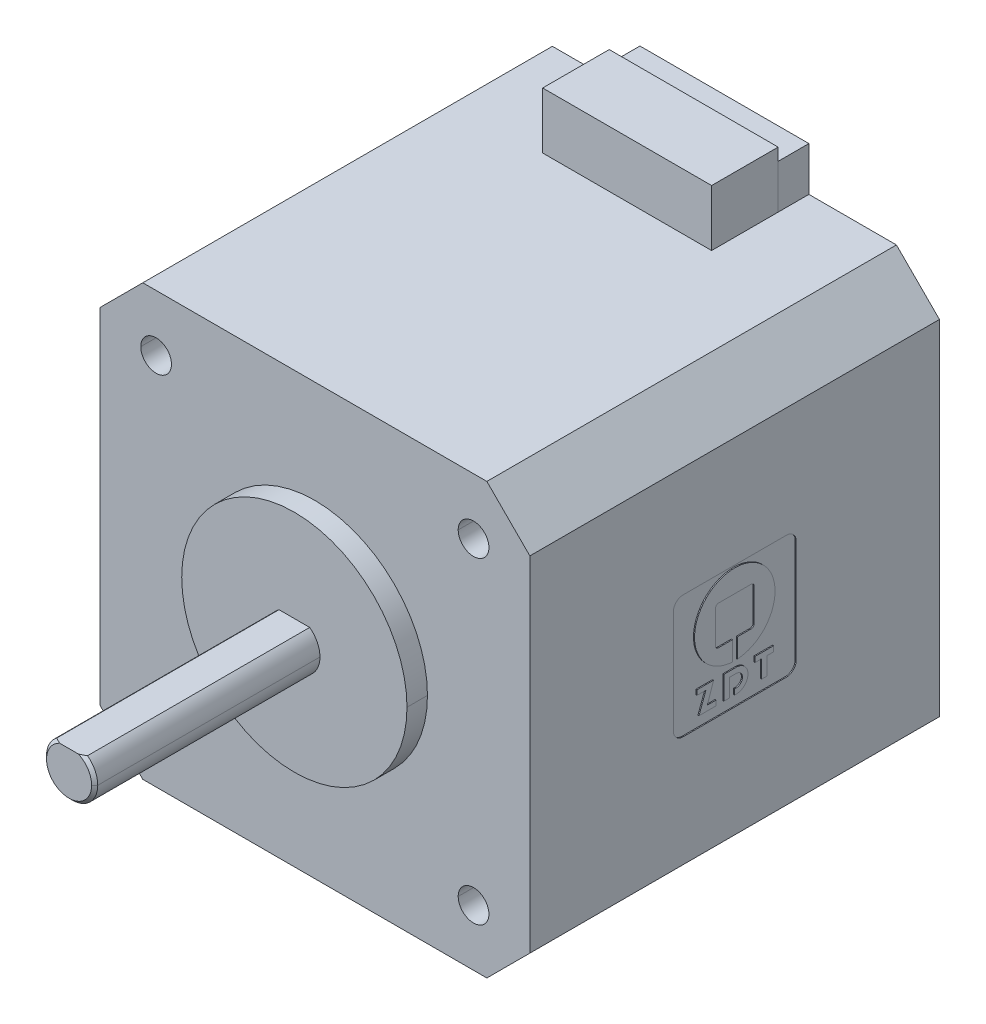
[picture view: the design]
ISO-10303-21;
HEADER;
FILE_DESCRIPTION(('STEP AP214'),'2;1');
FILE_NAME('part.step','',(''),(''),'','','');
FILE_SCHEMA(('AUTOMOTIVE_DESIGN { 1 0 10303 214 1 1 1 1 }'));
ENDSEC;
DATA;
#1=APPLICATION_CONTEXT('core data for automotive mechanical design processes');
#2=APPLICATION_PROTOCOL_DEFINITION('international standard','automotive_design',2000,#1);
#3=PRODUCT_CONTEXT('',#1,'mechanical');
#4=PRODUCT('Part','Part','',(#3));
#5=PRODUCT_RELATED_PRODUCT_CATEGORY('part','',(#4));
#6=PRODUCT_DEFINITION_FORMATION('','',#4);
#7=PRODUCT_DEFINITION_CONTEXT('part definition',#1,'design');
#8=PRODUCT_DEFINITION('design','',#6,#7);
#9=PRODUCT_DEFINITION_SHAPE('','',#8);
#10=(LENGTH_UNIT() NAMED_UNIT(*) SI_UNIT(.MILLI.,.METRE.));
#11=(NAMED_UNIT(*) PLANE_ANGLE_UNIT() SI_UNIT($,.RADIAN.));
#12=(NAMED_UNIT(*) SI_UNIT($,.STERADIAN.) SOLID_ANGLE_UNIT());
#13=UNCERTAINTY_MEASURE_WITH_UNIT(LENGTH_MEASURE(1.E-05),#10,'distance_accuracy_value','');
#14=(GEOMETRIC_REPRESENTATION_CONTEXT(3) GLOBAL_UNCERTAINTY_ASSIGNED_CONTEXT((#13)) GLOBAL_UNIT_ASSIGNED_CONTEXT((#10,
#11,#12)) REPRESENTATION_CONTEXT('',''));
#15=CARTESIAN_POINT('',(0.,0.,0.));
#16=DIRECTION('',(0.,0.,1.));
#17=DIRECTION('',(1.,0.,0.));
#18=AXIS2_PLACEMENT_3D('',#15,#16,#17);
#19=CARTESIAN_POINT('',(0.,21.,0.));
#20=DIRECTION('',(0.,1.,0.));
#21=DIRECTION('',(1.,0.,0.));
#22=AXIS2_PLACEMENT_3D('',#19,#20,#21);
#23=PLANE('',#22);
#24=DIRECTION('',(1.,0.,0.));
#25=VECTOR('',#24,1.);
#26=CARTESIAN_POINT('',(0.,21.,3.));
#27=LINE('',#26,#25);
#28=CARTESIAN_POINT('',(-8.25,21.,3.));
#29=VERTEX_POINT('',#28);
#30=CARTESIAN_POINT('',(8.25,21.,3.));
#31=VERTEX_POINT('',#30);
#32=EDGE_CURVE('P0_E73',#29,#31,#27,.T.);
#33=ORIENTED_EDGE('',*,*,#32,.T.);
#34=DIRECTION('',(0.,0.,1.));
#35=VECTOR('',#34,1.);
#36=CARTESIAN_POINT('',(8.25,21.,0.));
#37=LINE('',#36,#35);
#38=CARTESIAN_POINT('',(8.25,21.,9.5));
#39=VERTEX_POINT('',#38);
#40=EDGE_CURVE('P0_E25',#31,#39,#37,.T.);
#41=ORIENTED_EDGE('',*,*,#40,.T.);
#42=DIRECTION('',(1.,0.,0.));
#43=VECTOR('',#42,1.);
#44=CARTESIAN_POINT('',(0.,21.,9.5));
#45=LINE('',#44,#43);
#46=CARTESIAN_POINT('',(-8.25,21.,9.5));
#47=VERTEX_POINT('',#46);
#48=EDGE_CURVE('P0_E74',#47,#39,#45,.T.);
#49=ORIENTED_EDGE('',*,*,#48,.F.);
#50=DIRECTION('',(0.,0.,1.));
#51=VECTOR('',#50,1.);
#52=CARTESIAN_POINT('',(-8.25,21.,0.));
#53=LINE('',#52,#51);
#54=EDGE_CURVE('P0_E69',#29,#47,#53,.T.);
#55=ORIENTED_EDGE('',*,*,#54,.F.);
#56=EDGE_LOOP('',(#33,#41,#49,#55));
#57=FACE_BOUND('',#56,.T.);
#58=ADVANCED_FACE('P0_F17',(#57),#23,.F.);
#59=CARTESIAN_POINT('',(0.,26.5,0.));
#60=DIRECTION('',(0.,1.,0.));
#61=DIRECTION('',(1.,0.,0.));
#62=AXIS2_PLACEMENT_3D('',#59,#60,#61);
#63=PLANE('',#62);
#64=DIRECTION('',(1.,0.,0.));
#65=VECTOR('',#64,1.);
#66=CARTESIAN_POINT('',(0.,26.5,3.));
#67=LINE('',#66,#65);
#68=CARTESIAN_POINT('',(-8.25,26.5,3.));
#69=VERTEX_POINT('',#68);
#70=CARTESIAN_POINT('',(8.25,26.5,3.));
#71=VERTEX_POINT('',#70);
#72=EDGE_CURVE('P0_E95',#69,#71,#67,.T.);
#73=ORIENTED_EDGE('',*,*,#72,.F.);
#74=DIRECTION('',(0.,0.,1.));
#75=VECTOR('',#74,1.);
#76=CARTESIAN_POINT('',(-8.25,26.5,0.));
#77=LINE('',#76,#75);
#78=CARTESIAN_POINT('',(-8.25,26.5,9.5));
#79=VERTEX_POINT('',#78);
#80=EDGE_CURVE('P0_E87',#69,#79,#77,.T.);
#81=ORIENTED_EDGE('',*,*,#80,.T.);
#82=DIRECTION('',(1.,0.,0.));
#83=VECTOR('',#82,1.);
#84=CARTESIAN_POINT('',(0.,26.5,9.5));
#85=LINE('',#84,#83);
#86=CARTESIAN_POINT('',(8.25,26.5,9.5));
#87=VERTEX_POINT('',#86);
#88=EDGE_CURVE('P0_E111',#79,#87,#85,.T.);
#89=ORIENTED_EDGE('',*,*,#88,.T.);
#90=DIRECTION('',(0.,0.,1.));
#91=VECTOR('',#90,1.);
#92=CARTESIAN_POINT('',(8.25,26.5,0.));
#93=LINE('',#92,#91);
#94=EDGE_CURVE('P0_E11',#71,#87,#93,.T.);
#95=ORIENTED_EDGE('',*,*,#94,.F.);
#96=EDGE_LOOP('',(#73,#81,#89,#95));
#97=FACE_BOUND('',#96,.T.);
#98=ADVANCED_FACE('P0_F165',(#97),#63,.T.);
#99=CARTESIAN_POINT('',(8.25,26.5,0.));
#100=DIRECTION('',(1.,0.,0.));
#101=DIRECTION('',(0.,1.,0.));
#102=AXIS2_PLACEMENT_3D('',#99,#100,#101);
#103=PLANE('',#102);
#104=ORIENTED_EDGE('',*,*,#40,.F.);
#105=DIRECTION('',(0.,-1.,0.));
#106=VECTOR('',#105,1.);
#107=CARTESIAN_POINT('',(8.25,26.5,3.));
#108=LINE('',#107,#106);
#109=EDGE_CURVE('P0_E81',#71,#31,#108,.T.);
#110=ORIENTED_EDGE('',*,*,#109,.F.);
#111=ORIENTED_EDGE('',*,*,#94,.T.);
#112=DIRECTION('',(0.,-1.,0.));
#113=VECTOR('',#112,1.);
#114=CARTESIAN_POINT('',(8.25,26.5,9.5));
#115=LINE('',#114,#113);
#116=EDGE_CURVE('P0_E112',#87,#39,#115,.T.);
#117=ORIENTED_EDGE('',*,*,#116,.T.);
#118=EDGE_LOOP('',(#104,#110,#111,#117));
#119=FACE_BOUND('',#118,.T.);
#120=ADVANCED_FACE('P0_F155',(#119),#103,.T.);
#121=CARTESIAN_POINT('',(0.,26.5,9.5));
#122=DIRECTION('',(0.,0.,-1.));
#123=DIRECTION('',(-1.,0.,0.));
#124=AXIS2_PLACEMENT_3D('',#121,#122,#123);
#125=PLANE('',#124);
#126=ORIENTED_EDGE('',*,*,#48,.T.);
#127=ORIENTED_EDGE('',*,*,#116,.F.);
#128=ORIENTED_EDGE('',*,*,#88,.F.);
#129=DIRECTION('',(0.,-1.,0.));
#130=VECTOR('',#129,1.);
#131=CARTESIAN_POINT('',(-8.25,26.5,9.5));
#132=LINE('',#131,#130);
#133=EDGE_CURVE('P0_E79',#79,#47,#132,.T.);
#134=ORIENTED_EDGE('',*,*,#133,.T.);
#135=EDGE_LOOP('',(#126,#127,#128,#134));
#136=FACE_BOUND('',#135,.T.);
#137=ADVANCED_FACE('P0_F141',(#136),#125,.F.);
#138=CARTESIAN_POINT('',(-8.25,26.5,0.));
#139=DIRECTION('',(1.,0.,0.));
#140=DIRECTION('',(0.,0.,-1.));
#141=AXIS2_PLACEMENT_3D('',#138,#139,#140);
#142=PLANE('',#141);
#143=ORIENTED_EDGE('',*,*,#54,.T.);
#144=ORIENTED_EDGE('',*,*,#133,.F.);
#145=ORIENTED_EDGE('',*,*,#80,.F.);
#146=DIRECTION('',(0.,-1.,0.));
#147=VECTOR('',#146,1.);
#148=CARTESIAN_POINT('',(-8.25,26.5,3.));
#149=LINE('',#148,#147);
#150=EDGE_CURVE('P0_E82',#69,#29,#149,.T.);
#151=ORIENTED_EDGE('',*,*,#150,.T.);
#152=EDGE_LOOP('',(#143,#144,#145,#151));
#153=FACE_BOUND('',#152,.T.);
#154=ADVANCED_FACE('P0_F84',(#153),#142,.F.);
#155=CARTESIAN_POINT('',(0.,26.5,3.));
#156=DIRECTION('',(0.,0.,-1.));
#157=DIRECTION('',(-1.,0.,0.));
#158=AXIS2_PLACEMENT_3D('',#155,#156,#157);
#159=PLANE('',#158);
#160=ORIENTED_EDGE('',*,*,#32,.F.);
#161=ORIENTED_EDGE('',*,*,#150,.F.);
#162=ORIENTED_EDGE('',*,*,#72,.T.);
#163=ORIENTED_EDGE('',*,*,#109,.T.);
#164=EDGE_LOOP('',(#160,#161,#162,#163));
#165=FACE_BOUND('',#164,.T.);
#166=ADVANCED_FACE('P0_F92',(#165),#159,.T.);
#167=CLOSED_SHELL('',(#58,#98,#120,#137,#154,#166));
#168=MANIFOLD_SOLID_BREP('P0_B1',#167);
#169=CARTESIAN_POINT('',(21.,16.8,40.));
#170=DIRECTION('',(-1.,0.,0.));
#171=DIRECTION('',(0.,1.,0.));
#172=AXIS2_PLACEMENT_3D('',#169,#170,#171);
#173=PLANE('',#172);
#174=DIRECTION('',(0.,0.,1.));
#175=VECTOR('',#174,1.);
#176=CARTESIAN_POINT('',(21.,-2.68631850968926,22.0616));
#177=LINE('',#176,#175);
#178=CARTESIAN_POINT('',(21.,-2.68631850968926,22.0616));
#179=VERTEX_POINT('',#178);
#180=CARTESIAN_POINT('',(21.,-2.68631850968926,23.6787));
#181=VERTEX_POINT('',#180);
#182=EDGE_CURVE('P1_E995',#179,#181,#177,.T.);
#183=ORIENTED_EDGE('',*,*,#182,.T.);
#184=DIRECTION('',(0.,-1.,0.));
#185=VECTOR('',#184,1.);
#186=CARTESIAN_POINT('',(21.,-2.68631850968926,23.6787));
#187=LINE('',#186,#185);
#188=CARTESIAN_POINT('',(21.,-3.15601850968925,23.6787));
#189=VERTEX_POINT('',#188);
#190=EDGE_CURVE('P1_E11',#181,#189,#187,.T.);
#191=ORIENTED_EDGE('',*,*,#190,.T.);
#192=DIRECTION('',(0.,0.,-1.));
#193=VECTOR('',#192,1.);
#194=CARTESIAN_POINT('',(21.,-3.15601850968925,23.6787));
#195=LINE('',#194,#193);
#196=CARTESIAN_POINT('',(21.,-3.15601850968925,22.8051));
#197=VERTEX_POINT('',#196);
#198=EDGE_CURVE('P1_E48',#189,#197,#195,.T.);
#199=ORIENTED_EDGE('',*,*,#198,.T.);
#200=DIRECTION('',(0.,-0.936094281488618,0.351749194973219));
#201=VECTOR('',#200,1.);
#202=CARTESIAN_POINT('',(21.,-3.15601850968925,22.8051));
#203=LINE('',#202,#201);
#204=CARTESIAN_POINT('',(21.,-4.97551850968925,23.4888));
#205=VERTEX_POINT('',#204);
#206=EDGE_CURVE('P1_E1090',#197,#205,#203,.T.);
#207=ORIENTED_EDGE('',*,*,#206,.T.);
#208=DIRECTION('',(0.,0.,-1.));
#209=VECTOR('',#208,1.);
#210=CARTESIAN_POINT('',(21.,-4.97551850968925,23.4888));
#211=LINE('',#210,#209);
#212=CARTESIAN_POINT('',(21.,-4.97551850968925,21.8183));
#213=VERTEX_POINT('',#212);
#214=EDGE_CURVE('P1_E1079',#205,#213,#211,.T.);
#215=ORIENTED_EDGE('',*,*,#214,.T.);
#216=DIRECTION('',(0.,1.,0.));
#217=VECTOR('',#216,1.);
#218=CARTESIAN_POINT('',(21.,-4.97551850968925,21.8183));
#219=LINE('',#218,#217);
#220=CARTESIAN_POINT('',(21.,-4.48721850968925,21.8183));
#221=VERTEX_POINT('',#220);
#222=EDGE_CURVE('P1_E1074',#213,#221,#219,.T.);
#223=ORIENTED_EDGE('',*,*,#222,.T.);
#224=DIRECTION('',(0.,0.,1.));
#225=VECTOR('',#224,1.);
#226=CARTESIAN_POINT('',(21.,-4.48721850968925,21.8183));
#227=LINE('',#226,#225);
#228=CARTESIAN_POINT('',(21.,-4.48721850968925,22.6607));
#229=VERTEX_POINT('',#228);
#230=EDGE_CURVE('P1_E1067',#221,#229,#227,.T.);
#231=ORIENTED_EDGE('',*,*,#230,.T.);
#232=DIRECTION('',(0.,0.948882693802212,-0.315628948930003));
#233=VECTOR('',#232,1.);
#234=CARTESIAN_POINT('',(21.,-4.48721850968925,22.6607));
#235=LINE('',#234,#233);
#236=CARTESIAN_POINT('',(21.,-3.15601850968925,22.2179));
#237=VERTEX_POINT('',#236);
#238=EDGE_CURVE('P1_E1065',#229,#237,#235,.T.);
#239=ORIENTED_EDGE('',*,*,#238,.T.);
#240=DIRECTION('',(0.,0.948844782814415,-0.315742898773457));
#241=VECTOR('',#240,1.);
#242=CARTESIAN_POINT('',(21.,-3.15601850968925,22.2179));
#243=LINE('',#242,#241);
#244=EDGE_CURVE('P1_E1053',#237,#179,#243,.T.);
#245=ORIENTED_EDGE('',*,*,#244,.T.);
#246=EDGE_LOOP('',(#183,#191,#199,#207,#215,#223,#231,#239,#245));
#247=FACE_BOUND('',#246,.T.);
#248=ADVANCED_FACE('P1_F18',(#247),#173,.F.);
#249=CARTESIAN_POINT('',(21.,16.8,40.));
#250=DIRECTION('',(-1.,0.,0.));
#251=DIRECTION('',(0.,1.,0.));
#252=AXIS2_PLACEMENT_3D('',#249,#250,#251);
#253=PLANE('',#252);
#254=CARTESIAN_POINT('',(21.,-3.21791850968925,19.8494));
#255=CARTESIAN_POINT('',(21.,-3.21791850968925,19.5131));
#256=CARTESIAN_POINT('',(21.,-3.49311850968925,19.2382));
#257=CARTESIAN_POINT('',(21.,-3.82921850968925,19.2382));
#258=(BOUNDED_CURVE() B_SPLINE_CURVE(3,(#254,#255,#256,#257),.UNSPECIFIED.,.F.,
.F.) B_SPLINE_CURVE_WITH_KNOTS((4,4),(0.4375,0.5),
.UNSPECIFIED.) CURVE() GEOMETRIC_REPRESENTATION_ITEM() RATIONAL_B_SPLINE_CURVE((1.,1.,1.,1.)) REPRESENTATION_ITEM(''));
#259=CARTESIAN_POINT('',(21.,-3.21791850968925,19.8494));
#260=VERTEX_POINT('',#259);
#261=CARTESIAN_POINT('',(21.,-3.82921850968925,19.2382));
#262=VERTEX_POINT('',#261);
#263=EDGE_CURVE('P1_E768',#260,#262,#258,.T.);
#264=ORIENTED_EDGE('',*,*,#263,.T.);
#265=CARTESIAN_POINT('',(21.,-3.82921850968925,19.2382));
#266=CARTESIAN_POINT('',(21.,-4.16521850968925,19.2382));
#267=CARTESIAN_POINT('',(21.,-4.44041850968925,19.5131));
#268=CARTESIAN_POINT('',(21.,-4.44041850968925,19.8494));
#269=(BOUNDED_CURVE() B_SPLINE_CURVE(3,(#265,#266,#267,#268),.UNSPECIFIED.,.F.,
.F.) B_SPLINE_CURVE_WITH_KNOTS((4,4),(0.5,0.5625),
.UNSPECIFIED.) CURVE() GEOMETRIC_REPRESENTATION_ITEM() RATIONAL_B_SPLINE_CURVE((1.,1.,1.,1.)) REPRESENTATION_ITEM(''));
#270=CARTESIAN_POINT('',(21.,-4.44041850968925,19.8494));
#271=VERTEX_POINT('',#270);
#272=EDGE_CURVE('P1_E862',#262,#271,#269,.T.);
#273=ORIENTED_EDGE('',*,*,#272,.T.);
#274=DIRECTION('',(0.,0.,1.));
#275=VECTOR('',#274,1.);
#276=CARTESIAN_POINT('',(21.,-4.44041850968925,19.8494));
#277=LINE('',#276,#275);
#278=CARTESIAN_POINT('',(21.,-4.44041850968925,20.));
#279=VERTEX_POINT('',#278);
#280=EDGE_CURVE('P1_E853',#271,#279,#277,.T.);
#281=ORIENTED_EDGE('',*,*,#280,.T.);
#282=DIRECTION('',(0.,-1.,0.));
#283=VECTOR('',#282,1.);
#284=CARTESIAN_POINT('',(21.,-4.44041850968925,20.));
#285=LINE('',#284,#283);
#286=CARTESIAN_POINT('',(21.,-4.96361850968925,20.));
#287=VERTEX_POINT('',#286);
#288=EDGE_CURVE('P1_E813',#279,#287,#285,.T.);
#289=ORIENTED_EDGE('',*,*,#288,.T.);
#290=DIRECTION('',(0.,0.,-1.));
#291=VECTOR('',#290,1.);
#292=CARTESIAN_POINT('',(21.,-4.96361850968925,20.));
#293=LINE('',#292,#291);
#294=CARTESIAN_POINT('',(21.,-4.96361850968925,19.8307));
#295=VERTEX_POINT('',#294);
#296=EDGE_CURVE('P1_E812',#287,#295,#293,.T.);
#297=ORIENTED_EDGE('',*,*,#296,.T.);
#298=CARTESIAN_POINT('',(21.,-4.96361850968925,19.8307));
#299=CARTESIAN_POINT('',(21.,-4.96361850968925,19.2067));
#300=CARTESIAN_POINT('',(21.,-4.45321850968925,18.6962));
#301=CARTESIAN_POINT('',(21.,-3.82921850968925,18.6962));
#302=(BOUNDED_CURVE() B_SPLINE_CURVE(3,(#298,#299,#300,#301),.UNSPECIFIED.,.F.,
.F.) B_SPLINE_CURVE_WITH_KNOTS((4,4),(0.75,0.8125),
.UNSPECIFIED.) CURVE() GEOMETRIC_REPRESENTATION_ITEM() RATIONAL_B_SPLINE_CURVE((1.,1.,1.,1.)) REPRESENTATION_ITEM(''));
#303=CARTESIAN_POINT('',(21.,-3.82921850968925,18.6962));
#304=VERTEX_POINT('',#303);
#305=EDGE_CURVE('P1_E828',#295,#304,#302,.T.);
#306=ORIENTED_EDGE('',*,*,#305,.T.);
#307=CARTESIAN_POINT('',(21.,-3.82921850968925,18.6962));
#308=CARTESIAN_POINT('',(21.,-3.20521850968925,18.6962));
#309=CARTESIAN_POINT('',(21.,-2.69471850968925,19.2067));
#310=CARTESIAN_POINT('',(21.,-2.69471850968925,19.8307));
#311=(BOUNDED_CURVE() B_SPLINE_CURVE(3,(#307,#308,#309,#310),.UNSPECIFIED.,.F.,
.F.) B_SPLINE_CURVE_WITH_KNOTS((4,4),(0.875,0.9375),
.UNSPECIFIED.) CURVE() GEOMETRIC_REPRESENTATION_ITEM() RATIONAL_B_SPLINE_CURVE((1.,1.,1.,1.)) REPRESENTATION_ITEM(''));
#312=CARTESIAN_POINT('',(21.,-2.69471850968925,19.8307));
#313=VERTEX_POINT('',#312);
#314=EDGE_CURVE('P1_E818',#304,#313,#311,.T.);
#315=ORIENTED_EDGE('',*,*,#314,.T.);
#316=DIRECTION('',(0.,0.,1.));
#317=VECTOR('',#316,1.);
#318=CARTESIAN_POINT('',(21.,-2.69471850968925,19.8307));
#319=LINE('',#318,#317);
#320=CARTESIAN_POINT('',(21.,-2.69471850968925,21.0456));
#321=VERTEX_POINT('',#320);
#322=EDGE_CURVE('P1_E804',#313,#321,#319,.T.);
#323=ORIENTED_EDGE('',*,*,#322,.T.);
#324=DIRECTION('',(0.,-1.,0.));
#325=VECTOR('',#324,1.);
#326=CARTESIAN_POINT('',(21.,-2.69471850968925,21.0456));
#327=LINE('',#326,#325);
#328=CARTESIAN_POINT('',(21.,-4.96361850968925,21.0456));
#329=VERTEX_POINT('',#328);
#330=EDGE_CURVE('P1_E799',#321,#329,#327,.T.);
#331=ORIENTED_EDGE('',*,*,#330,.T.);
#332=DIRECTION('',(0.,0.,-1.));
#333=VECTOR('',#332,1.);
#334=CARTESIAN_POINT('',(21.,-4.96361850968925,21.0456));
#335=LINE('',#334,#333);
#336=CARTESIAN_POINT('',(21.,-4.96361850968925,20.5036));
#337=VERTEX_POINT('',#336);
#338=EDGE_CURVE('P1_E791',#329,#337,#335,.T.);
#339=ORIENTED_EDGE('',*,*,#338,.T.);
#340=DIRECTION('',(0.,1.,0.));
#341=VECTOR('',#340,1.);
#342=CARTESIAN_POINT('',(21.,-4.05351850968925,20.5036));
#343=LINE('',#342,#341);
#344=CARTESIAN_POINT('',(21.,-3.21791850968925,20.5036));
#345=VERTEX_POINT('',#344);
#346=EDGE_CURVE('P1_E694',#337,#345,#343,.T.);
#347=ORIENTED_EDGE('',*,*,#346,.T.);
#348=DIRECTION('',(0.,0.,-1.));
#349=VECTOR('',#348,1.);
#350=CARTESIAN_POINT('',(21.,-3.21791850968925,20.5036));
#351=LINE('',#350,#349);
#352=EDGE_CURVE('P1_E693',#345,#260,#351,.T.);
#353=ORIENTED_EDGE('',*,*,#352,.T.);
#354=EDGE_LOOP('',(#264,#273,#281,#289,#297,#306,#315,#323,#331,#339,#347,#353));
#355=FACE_BOUND('',#354,.T.);
#356=ADVANCED_FACE('P1_F1170',(#355),#253,.F.);
#357=CARTESIAN_POINT('',(21.,16.8,40.));
#358=DIRECTION('',(-1.,0.,0.));
#359=DIRECTION('',(0.,1.,0.));
#360=AXIS2_PLACEMENT_3D('',#357,#358,#359);
#361=PLANE('',#360);
#362=CARTESIAN_POINT('',(21.,-2.06441850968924,19.7418));
#363=CARTESIAN_POINT('',(21.,-1.93761850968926,17.6866));
#364=CARTESIAN_POINT('',(21.,-0.23111850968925,16.0587));
#365=CARTESIAN_POINT('',(21.,1.85608149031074,16.0587));
#366=(BOUNDED_CURVE() B_SPLINE_CURVE(3,(#362,#363,#364,#365),.UNSPECIFIED.,.F.,
.F.) B_SPLINE_CURVE_WITH_KNOTS((4,4),(0.125,0.1875),
.UNSPECIFIED.) CURVE() GEOMETRIC_REPRESENTATION_ITEM() RATIONAL_B_SPLINE_CURVE((1.,1.,1.,1.)) REPRESENTATION_ITEM(''));
#367=CARTESIAN_POINT('',(21.,-2.06441850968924,19.7418));
#368=VERTEX_POINT('',#367);
#369=CARTESIAN_POINT('',(21.,1.85608149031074,16.0587));
#370=VERTEX_POINT('',#369);
#371=EDGE_CURVE('P1_E869',#368,#370,#366,.T.);
#372=ORIENTED_EDGE('',*,*,#371,.T.);
#373=CARTESIAN_POINT('',(21.,1.85608149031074,16.0587));
#374=CARTESIAN_POINT('',(21.,4.02578149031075,16.0587));
#375=CARTESIAN_POINT('',(21.,5.78458149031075,17.8178));
#376=CARTESIAN_POINT('',(21.,5.78458149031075,19.9874));
#377=(BOUNDED_CURVE() B_SPLINE_CURVE(3,(#373,#374,#375,#376),.UNSPECIFIED.,.F.,
.F.) B_SPLINE_CURVE_WITH_KNOTS((4,4),(0.1875,0.25),
.UNSPECIFIED.) CURVE() GEOMETRIC_REPRESENTATION_ITEM() RATIONAL_B_SPLINE_CURVE((1.,1.,1.,1.)) REPRESENTATION_ITEM(''));
#378=CARTESIAN_POINT('',(21.,5.78458149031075,19.9874));
#379=VERTEX_POINT('',#378);
#380=EDGE_CURVE('P1_E861',#370,#379,#377,.T.);
#381=ORIENTED_EDGE('',*,*,#380,.T.);
#382=CARTESIAN_POINT('',(21.,5.78458149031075,19.9874));
#383=CARTESIAN_POINT('',(21.,5.78458149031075,22.1568));
#384=CARTESIAN_POINT('',(21.,4.02578149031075,23.9159));
#385=CARTESIAN_POINT('',(21.,1.85608149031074,23.9159));
#386=(BOUNDED_CURVE() B_SPLINE_CURVE(3,(#382,#383,#384,#385),.UNSPECIFIED.,.F.,
.F.) B_SPLINE_CURVE_WITH_KNOTS((4,4),(0.25,0.3125),
.UNSPECIFIED.) CURVE() GEOMETRIC_REPRESENTATION_ITEM() RATIONAL_B_SPLINE_CURVE((1.,1.,1.,1.)) REPRESENTATION_ITEM(''));
#387=CARTESIAN_POINT('',(21.,1.85608149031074,23.9159));
#388=VERTEX_POINT('',#387);
#389=EDGE_CURVE('P1_E864',#379,#388,#386,.T.);
#390=ORIENTED_EDGE('',*,*,#389,.T.);
#391=CARTESIAN_POINT('',(21.,1.85608149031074,23.9159));
#392=CARTESIAN_POINT('',(21.,-0.23111850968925,23.9159));
#393=CARTESIAN_POINT('',(21.,-1.93761850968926,22.288));
#394=CARTESIAN_POINT('',(21.,-2.06441850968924,20.2328));
#395=(BOUNDED_CURVE() B_SPLINE_CURVE(3,(#391,#392,#393,#394),.UNSPECIFIED.,.F.,
.F.) B_SPLINE_CURVE_WITH_KNOTS((4,4),(0.3125,0.375),
.UNSPECIFIED.) CURVE() GEOMETRIC_REPRESENTATION_ITEM() RATIONAL_B_SPLINE_CURVE((1.,1.,1.,1.)) REPRESENTATION_ITEM(''));
#396=CARTESIAN_POINT('',(21.,-2.06441850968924,20.2328));
#397=VERTEX_POINT('',#396);
#398=EDGE_CURVE('P1_E990',#388,#397,#395,.T.);
#399=ORIENTED_EDGE('',*,*,#398,.T.);
#400=DIRECTION('',(0.,1.,0.));
#401=VECTOR('',#400,1.);
#402=CARTESIAN_POINT('',(21.,-2.06441850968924,20.2328));
#403=LINE('',#402,#401);
#404=CARTESIAN_POINT('',(21.,-0.175218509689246,20.2328));
#405=VERTEX_POINT('',#404);
#406=EDGE_CURVE('P1_E985',#397,#405,#403,.T.);
#407=ORIENTED_EDGE('',*,*,#406,.T.);
#408=DIRECTION('',(0.,0.,1.));
#409=VECTOR('',#408,1.);
#410=CARTESIAN_POINT('',(21.,-0.175218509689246,20.2328));
#411=LINE('',#410,#409);
#412=CARTESIAN_POINT('',(21.,-0.175218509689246,21.5695));
#413=VERTEX_POINT('',#412);
#414=EDGE_CURVE('P1_E972',#405,#413,#411,.T.);
#415=ORIENTED_EDGE('',*,*,#414,.T.);
#416=CARTESIAN_POINT('',(21.,-0.175218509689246,21.5695));
#417=CARTESIAN_POINT('',(21.,-0.175218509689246,21.7375));
#418=CARTESIAN_POINT('',(21.,-0.0379185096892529,21.8747));
#419=CARTESIAN_POINT('',(21.,0.129781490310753,21.8747));
#420=(BOUNDED_CURVE() B_SPLINE_CURVE(3,(#416,#417,#418,#419),.UNSPECIFIED.,.F.,
.F.) B_SPLINE_CURVE_WITH_KNOTS((4,4),(0.5,0.5625),
.UNSPECIFIED.) CURVE() GEOMETRIC_REPRESENTATION_ITEM() RATIONAL_B_SPLINE_CURVE((1.,1.,1.,1.)) REPRESENTATION_ITEM(''));
#421=CARTESIAN_POINT('',(21.,0.129781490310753,21.8747));
#422=VERTEX_POINT('',#421);
#423=EDGE_CURVE('P1_E964',#413,#422,#420,.T.);
#424=ORIENTED_EDGE('',*,*,#423,.T.);
#425=DIRECTION('',(0.,1.,0.));
#426=VECTOR('',#425,1.);
#427=CARTESIAN_POINT('',(21.,0.129781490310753,21.8747));
#428=LINE('',#427,#426);
#429=CARTESIAN_POINT('',(21.,3.29448149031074,21.8747));
#430=VERTEX_POINT('',#429);
#431=EDGE_CURVE('P1_E910',#422,#430,#428,.T.);
#432=ORIENTED_EDGE('',*,*,#431,.T.);
#433=CARTESIAN_POINT('',(21.,3.29448149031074,21.8747));
#434=CARTESIAN_POINT('',(21.,3.46218149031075,21.8747));
#435=CARTESIAN_POINT('',(21.,3.59968149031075,21.7375));
#436=CARTESIAN_POINT('',(21.,3.59968149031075,21.5695));
#437=(BOUNDED_CURVE() B_SPLINE_CURVE(3,(#433,#434,#435,#436),.UNSPECIFIED.,.F.,
.F.) B_SPLINE_CURVE_WITH_KNOTS((4,4),(0.625,0.6875),
.UNSPECIFIED.) CURVE() GEOMETRIC_REPRESENTATION_ITEM() RATIONAL_B_SPLINE_CURVE((1.,1.,1.,1.)) REPRESENTATION_ITEM(''));
#438=CARTESIAN_POINT('',(21.,3.59968149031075,21.5695));
#439=VERTEX_POINT('',#438);
#440=EDGE_CURVE('P1_E947',#430,#439,#437,.T.);
#441=ORIENTED_EDGE('',*,*,#440,.T.);
#442=DIRECTION('',(0.,0.,-1.));
#443=VECTOR('',#442,1.);
#444=CARTESIAN_POINT('',(21.,3.59968149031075,21.5695));
#445=LINE('',#444,#443);
#446=CARTESIAN_POINT('',(21.,3.59968149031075,18.4051));
#447=VERTEX_POINT('',#446);
#448=EDGE_CURVE('P1_E940',#439,#447,#445,.T.);
#449=ORIENTED_EDGE('',*,*,#448,.T.);
#450=CARTESIAN_POINT('',(21.,3.59968149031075,18.4051));
#451=CARTESIAN_POINT('',(21.,3.59968149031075,18.2371));
#452=CARTESIAN_POINT('',(21.,3.46218149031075,18.0999));
#453=CARTESIAN_POINT('',(21.,3.29448149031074,18.0999));
#454=(BOUNDED_CURVE() B_SPLINE_CURVE(3,(#450,#451,#452,#453),.UNSPECIFIED.,.F.,
.F.) B_SPLINE_CURVE_WITH_KNOTS((4,4),(0.75,0.8125),
.UNSPECIFIED.) CURVE() GEOMETRIC_REPRESENTATION_ITEM() RATIONAL_B_SPLINE_CURVE((1.,1.,1.,1.)) REPRESENTATION_ITEM(''));
#455=CARTESIAN_POINT('',(21.,3.29448149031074,18.0999));
#456=VERTEX_POINT('',#455);
#457=EDGE_CURVE('P1_E924',#447,#456,#454,.T.);
#458=ORIENTED_EDGE('',*,*,#457,.T.);
#459=DIRECTION('',(0.,-1.,0.));
#460=VECTOR('',#459,1.);
#461=CARTESIAN_POINT('',(21.,3.29448149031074,18.0999));
#462=LINE('',#461,#460);
#463=CARTESIAN_POINT('',(21.,0.129781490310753,18.0999));
#464=VERTEX_POINT('',#463);
#465=EDGE_CURVE('P1_E916',#456,#464,#462,.T.);
#466=ORIENTED_EDGE('',*,*,#465,.T.);
#467=CARTESIAN_POINT('',(21.,0.129781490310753,18.0999));
#468=CARTESIAN_POINT('',(21.,-0.0379185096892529,18.0999));
#469=CARTESIAN_POINT('',(21.,-0.175218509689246,18.2371));
#470=CARTESIAN_POINT('',(21.,-0.175218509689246,18.4051));
#471=(BOUNDED_CURVE() B_SPLINE_CURVE(3,(#467,#468,#469,#470),.UNSPECIFIED.,.F.,
.F.) B_SPLINE_CURVE_WITH_KNOTS((4,4),(0.875,0.9375),
.UNSPECIFIED.) CURVE() GEOMETRIC_REPRESENTATION_ITEM() RATIONAL_B_SPLINE_CURVE((1.,1.,1.,1.)) REPRESENTATION_ITEM(''));
#472=CARTESIAN_POINT('',(21.,-0.175218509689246,18.4051));
#473=VERTEX_POINT('',#472);
#474=EDGE_CURVE('P1_E901',#464,#473,#471,.T.);
#475=ORIENTED_EDGE('',*,*,#474,.T.);
#476=DIRECTION('',(0.,0.,1.));
#477=VECTOR('',#476,1.);
#478=CARTESIAN_POINT('',(21.,-0.175218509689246,18.4051));
#479=LINE('',#478,#477);
#480=CARTESIAN_POINT('',(21.,-0.175218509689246,19.7418));
#481=VERTEX_POINT('',#480);
#482=EDGE_CURVE('P1_E896',#473,#481,#479,.T.);
#483=ORIENTED_EDGE('',*,*,#482,.T.);
#484=DIRECTION('',(0.,-1.,0.));
#485=VECTOR('',#484,1.);
#486=CARTESIAN_POINT('',(21.,-0.175218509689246,19.7418));
#487=LINE('',#486,#485);
#488=EDGE_CURVE('P1_E890',#481,#368,#487,.T.);
#489=ORIENTED_EDGE('',*,*,#488,.T.);
#490=EDGE_LOOP('',(#372,#381,#390,#399,#407,#415,#424,#432,#441,#449,#458,#466,#475,#483,#489));
#491=FACE_BOUND('',#490,.T.);
#492=ADVANCED_FACE('P1_F1163',(#491),#361,.F.);
#493=CARTESIAN_POINT('',(21.,16.8,40.));
#494=DIRECTION('',(-1.,0.,0.));
#495=DIRECTION('',(0.,1.,0.));
#496=AXIS2_PLACEMENT_3D('',#493,#494,#495);
#497=PLANE('',#496);
#498=DIRECTION('',(0.,0.,1.));
#499=VECTOR('',#498,1.);
#500=CARTESIAN_POINT('',(21.,-2.69881850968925,16.1943));
#501=LINE('',#500,#499);
#502=CARTESIAN_POINT('',(21.,-2.69881850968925,16.1943));
#503=VERTEX_POINT('',#502);
#504=CARTESIAN_POINT('',(21.,-2.69881850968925,18.0146));
#505=VERTEX_POINT('',#504);
#506=EDGE_CURVE('P1_E1001',#503,#505,#501,.T.);
#507=ORIENTED_EDGE('',*,*,#506,.T.);
#508=DIRECTION('',(0.,-1.,0.));
#509=VECTOR('',#508,1.);
#510=CARTESIAN_POINT('',(21.,-2.69881850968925,18.0146));
#511=LINE('',#510,#509);
#512=CARTESIAN_POINT('',(21.,-3.21521850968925,18.0146));
#513=VERTEX_POINT('',#512);
#514=EDGE_CURVE('P1_E996',#505,#513,#511,.T.);
#515=ORIENTED_EDGE('',*,*,#514,.T.);
#516=DIRECTION('',(0.,0.,-1.));
#517=VECTOR('',#516,1.);
#518=CARTESIAN_POINT('',(21.,-3.21521850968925,18.0146));
#519=LINE('',#518,#517);
#520=CARTESIAN_POINT('',(21.,-3.21521850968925,17.3627));
#521=VERTEX_POINT('',#520);
#522=EDGE_CURVE('P1_E939',#513,#521,#519,.T.);
#523=ORIENTED_EDGE('',*,*,#522,.T.);
#524=DIRECTION('',(0.,-1.,0.));
#525=VECTOR('',#524,1.);
#526=CARTESIAN_POINT('',(21.,-3.21521850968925,17.3627));
#527=LINE('',#526,#525);
#528=CARTESIAN_POINT('',(21.,-4.94241850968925,17.3627));
#529=VERTEX_POINT('',#528);
#530=EDGE_CURVE('P1_E1028',#521,#529,#527,.T.);
#531=ORIENTED_EDGE('',*,*,#530,.T.);
#532=DIRECTION('',(0.,0.,-1.));
#533=VECTOR('',#532,1.);
#534=CARTESIAN_POINT('',(21.,-4.94241850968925,17.3627));
#535=LINE('',#534,#533);
#536=CARTESIAN_POINT('',(21.,-4.94241850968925,16.8462));
#537=VERTEX_POINT('',#536);
#538=EDGE_CURVE('P1_E1033',#529,#537,#535,.T.);
#539=ORIENTED_EDGE('',*,*,#538,.T.);
#540=DIRECTION('',(0.,1.,0.));
#541=VECTOR('',#540,1.);
#542=CARTESIAN_POINT('',(21.,-4.94241850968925,16.8462));
#543=LINE('',#542,#541);
#544=CARTESIAN_POINT('',(21.,-3.21521850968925,16.8462));
#545=VERTEX_POINT('',#544);
#546=EDGE_CURVE('P1_E1022',#537,#545,#543,.T.);
#547=ORIENTED_EDGE('',*,*,#546,.T.);
#548=DIRECTION('',(0.,0.,-1.));
#549=VECTOR('',#548,1.);
#550=CARTESIAN_POINT('',(21.,-3.21521850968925,16.8462));
#551=LINE('',#550,#549);
#552=CARTESIAN_POINT('',(21.,-3.21521850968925,16.1943));
#553=VERTEX_POINT('',#552);
#554=EDGE_CURVE('P1_E841',#545,#553,#551,.T.);
#555=ORIENTED_EDGE('',*,*,#554,.T.);
#556=DIRECTION('',(0.,1.,0.));
#557=VECTOR('',#556,1.);
#558=CARTESIAN_POINT('',(21.,-3.21521850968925,16.1943));
#559=LINE('',#558,#557);
#560=EDGE_CURVE('P1_E1012',#553,#503,#559,.T.);
#561=ORIENTED_EDGE('',*,*,#560,.T.);
#562=EDGE_LOOP('',(#507,#515,#523,#531,#539,#547,#555,#561));
#563=FACE_BOUND('',#562,.T.);
#564=ADVANCED_FACE('P1_F20',(#563),#497,.F.);
#565=CARTESIAN_POINT('',(20.9,-2.68631850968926,23.6787));
#566=DIRECTION('',(0.,0.,1.));
#567=DIRECTION('',(1.,0.,0.));
#568=AXIS2_PLACEMENT_3D('',#565,#566,#567);
#569=PLANE('',#568);
#570=ORIENTED_EDGE('',*,*,#190,.F.);
#571=DIRECTION('',(1.,0.,0.));
#572=VECTOR('',#571,1.);
#573=CARTESIAN_POINT('',(20.9,-2.68631850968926,23.6787));
#574=LINE('',#573,#572);
#575=CARTESIAN_POINT('',(20.9,-2.68631850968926,23.6787));
#576=VERTEX_POINT('',#575);
#577=EDGE_CURVE('P1_E1048',#576,#181,#574,.T.);
#578=ORIENTED_EDGE('',*,*,#577,.F.);
#579=DIRECTION('',(0.,-1.,0.));
#580=VECTOR('',#579,1.);
#581=CARTESIAN_POINT('',(20.9,-2.68631850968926,23.6787));
#582=LINE('',#581,#580);
#583=CARTESIAN_POINT('',(20.9,-3.15601850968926,23.6787));
#584=VERTEX_POINT('',#583);
#585=EDGE_CURVE('P1_E1623',#576,#584,#582,.T.);
#586=ORIENTED_EDGE('',*,*,#585,.T.);
#587=DIRECTION('',(1.,0.,0.));
#588=VECTOR('',#587,1.);
#589=CARTESIAN_POINT('',(20.9,-3.15601850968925,23.6787));
#590=LINE('',#589,#588);
#591=EDGE_CURVE('P1_E29',#584,#189,#590,.T.);
#592=ORIENTED_EDGE('',*,*,#591,.T.);
#593=EDGE_LOOP('',(#570,#578,#586,#592));
#594=FACE_BOUND('',#593,.T.);
#595=ADVANCED_FACE('P1_F1190',(#594),#569,.T.);
#596=CARTESIAN_POINT('',(20.9,-3.15601850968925,23.6787));
#597=DIRECTION('',(0.,-1.,0.));
#598=DIRECTION('',(0.,0.,-1.));
#599=AXIS2_PLACEMENT_3D('',#596,#597,#598);
#600=PLANE('',#599);
#601=ORIENTED_EDGE('',*,*,#198,.F.);
#602=ORIENTED_EDGE('',*,*,#591,.F.);
#603=DIRECTION('',(0.,0.,-1.));
#604=VECTOR('',#603,1.);
#605=CARTESIAN_POINT('',(20.9,-3.15601850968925,23.6787));
#606=LINE('',#605,#604);
#607=CARTESIAN_POINT('',(20.9,-3.15601850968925,22.8051));
#608=VERTEX_POINT('',#607);
#609=EDGE_CURVE('P1_E1454',#584,#608,#606,.T.);
#610=ORIENTED_EDGE('',*,*,#609,.T.);
#611=DIRECTION('',(1.,0.,0.));
#612=VECTOR('',#611,1.);
#613=CARTESIAN_POINT('',(20.9,-3.15601850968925,22.8051));
#614=LINE('',#613,#612);
#615=EDGE_CURVE('P1_E1084',#608,#197,#614,.T.);
#616=ORIENTED_EDGE('',*,*,#615,.T.);
#617=EDGE_LOOP('',(#601,#602,#610,#616));
#618=FACE_BOUND('',#617,.T.);
#619=ADVANCED_FACE('P1_F1195',(#618),#600,.T.);
#620=CARTESIAN_POINT('',(20.9,-3.15601850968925,22.8051));
#621=DIRECTION('',(0.,0.351749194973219,0.936094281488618));
#622=DIRECTION('',(1.,0.,0.));
#623=AXIS2_PLACEMENT_3D('',#620,#621,#622);
#624=PLANE('',#623);
#625=ORIENTED_EDGE('',*,*,#206,.F.);
#626=ORIENTED_EDGE('',*,*,#615,.F.);
#627=DIRECTION('',(0.,-0.936094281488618,0.351749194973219));
#628=VECTOR('',#627,1.);
#629=CARTESIAN_POINT('',(20.9,-3.15601850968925,22.8051));
#630=LINE('',#629,#628);
#631=CARTESIAN_POINT('',(20.9,-4.97551850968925,23.4888));
#632=VERTEX_POINT('',#631);
#633=EDGE_CURVE('P1_E1451',#608,#632,#630,.T.);
#634=ORIENTED_EDGE('',*,*,#633,.T.);
#635=DIRECTION('',(1.,0.,0.));
#636=VECTOR('',#635,1.);
#637=CARTESIAN_POINT('',(20.9,-4.97551850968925,23.4888));
#638=LINE('',#637,#636);
#639=EDGE_CURVE('P1_E1081',#632,#205,#638,.T.);
#640=ORIENTED_EDGE('',*,*,#639,.T.);
#641=EDGE_LOOP('',(#625,#626,#634,#640));
#642=FACE_BOUND('',#641,.T.);
#643=ADVANCED_FACE('P1_F3212',(#642),#624,.T.);
#644=CARTESIAN_POINT('',(20.9,-4.97551850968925,23.4888));
#645=DIRECTION('',(0.,-1.,0.));
#646=DIRECTION('',(0.,0.,-1.));
#647=AXIS2_PLACEMENT_3D('',#644,#645,#646);
#648=PLANE('',#647);
#649=ORIENTED_EDGE('',*,*,#214,.F.);
#650=ORIENTED_EDGE('',*,*,#639,.F.);
#651=DIRECTION('',(0.,0.,-1.));
#652=VECTOR('',#651,1.);
#653=CARTESIAN_POINT('',(20.9,-4.97551850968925,23.4888));
#654=LINE('',#653,#652);
#655=CARTESIAN_POINT('',(20.9,-4.97551850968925,21.8183));
#656=VERTEX_POINT('',#655);
#657=EDGE_CURVE('P1_E1457',#632,#656,#654,.T.);
#658=ORIENTED_EDGE('',*,*,#657,.T.);
#659=DIRECTION('',(1.,0.,0.));
#660=VECTOR('',#659,1.);
#661=CARTESIAN_POINT('',(20.9,-4.97551850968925,21.8183));
#662=LINE('',#661,#660);
#663=EDGE_CURVE('P1_E1078',#656,#213,#662,.T.);
#664=ORIENTED_EDGE('',*,*,#663,.T.);
#665=EDGE_LOOP('',(#649,#650,#658,#664));
#666=FACE_BOUND('',#665,.T.);
#667=ADVANCED_FACE('P1_F3220',(#666),#648,.T.);
#668=CARTESIAN_POINT('',(20.9,-4.97551850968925,21.8183));
#669=DIRECTION('',(0.,0.,-1.));
#670=DIRECTION('',(0.,-1.,0.));
#671=AXIS2_PLACEMENT_3D('',#668,#669,#670);
#672=PLANE('',#671);
#673=ORIENTED_EDGE('',*,*,#222,.F.);
#674=ORIENTED_EDGE('',*,*,#663,.F.);
#675=DIRECTION('',(0.,1.,0.));
#676=VECTOR('',#675,1.);
#677=CARTESIAN_POINT('',(20.9,-4.97551850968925,21.8183));
#678=LINE('',#677,#676);
#679=CARTESIAN_POINT('',(20.9,-4.48721850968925,21.8183));
#680=VERTEX_POINT('',#679);
#681=EDGE_CURVE('P1_E1566',#656,#680,#678,.T.);
#682=ORIENTED_EDGE('',*,*,#681,.T.);
#683=DIRECTION('',(1.,0.,0.));
#684=VECTOR('',#683,1.);
#685=CARTESIAN_POINT('',(20.9,-4.48721850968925,21.8183));
#686=LINE('',#685,#684);
#687=EDGE_CURVE('P1_E1068',#680,#221,#686,.T.);
#688=ORIENTED_EDGE('',*,*,#687,.T.);
#689=EDGE_LOOP('',(#673,#674,#682,#688));
#690=FACE_BOUND('',#689,.T.);
#691=ADVANCED_FACE('P1_F3372',(#690),#672,.T.);
#692=CARTESIAN_POINT('',(20.9,-4.48721850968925,21.8183));
#693=DIRECTION('',(0.,1.,0.));
#694=DIRECTION('',(1.,0.,0.));
#695=AXIS2_PLACEMENT_3D('',#692,#693,#694);
#696=PLANE('',#695);
#697=ORIENTED_EDGE('',*,*,#230,.F.);
#698=ORIENTED_EDGE('',*,*,#687,.F.);
#699=DIRECTION('',(0.,0.,1.));
#700=VECTOR('',#699,1.);
#701=CARTESIAN_POINT('',(20.9,-4.48721850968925,21.8183));
#702=LINE('',#701,#700);
#703=CARTESIAN_POINT('',(20.9,-4.48721850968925,22.6607));
#704=VERTEX_POINT('',#703);
#705=EDGE_CURVE('P1_E1610',#680,#704,#702,.T.);
#706=ORIENTED_EDGE('',*,*,#705,.T.);
#707=DIRECTION('',(1.,0.,0.));
#708=VECTOR('',#707,1.);
#709=CARTESIAN_POINT('',(20.9,-4.48721850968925,22.6607));
#710=LINE('',#709,#708);
#711=EDGE_CURVE('P1_E1062',#704,#229,#710,.T.);
#712=ORIENTED_EDGE('',*,*,#711,.T.);
#713=EDGE_LOOP('',(#697,#698,#706,#712));
#714=FACE_BOUND('',#713,.T.);
#715=ADVANCED_FACE('P1_F3365',(#714),#696,.T.);
#716=CARTESIAN_POINT('',(20.9,-4.48721850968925,22.6607));
#717=DIRECTION('',(0.,-0.315628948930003,-0.948882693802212));
#718=DIRECTION('',(0.,-0.948882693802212,0.315628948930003));
#719=AXIS2_PLACEMENT_3D('',#716,#717,#718);
#720=PLANE('',#719);
#721=ORIENTED_EDGE('',*,*,#238,.F.);
#722=ORIENTED_EDGE('',*,*,#711,.F.);
#723=DIRECTION('',(0.,0.948882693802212,-0.315628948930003));
#724=VECTOR('',#723,1.);
#725=CARTESIAN_POINT('',(20.9,-4.48721850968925,22.6607));
#726=LINE('',#725,#724);
#727=CARTESIAN_POINT('',(20.9,-3.15601850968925,22.2179));
#728=VERTEX_POINT('',#727);
#729=EDGE_CURVE('P1_E1606',#704,#728,#726,.T.);
#730=ORIENTED_EDGE('',*,*,#729,.T.);
#731=DIRECTION('',(1.,0.,0.));
#732=VECTOR('',#731,1.);
#733=CARTESIAN_POINT('',(20.9,-3.15601850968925,22.2179));
#734=LINE('',#733,#732);
#735=EDGE_CURVE('P1_E1060',#728,#237,#734,.T.);
#736=ORIENTED_EDGE('',*,*,#735,.T.);
#737=EDGE_LOOP('',(#721,#722,#730,#736));
#738=FACE_BOUND('',#737,.T.);
#739=ADVANCED_FACE('P1_F1254',(#738),#720,.T.);
#740=CARTESIAN_POINT('',(20.9,-3.15601850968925,22.2179));
#741=DIRECTION('',(0.,-0.315742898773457,-0.948844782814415));
#742=DIRECTION('',(0.,-0.948844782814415,0.315742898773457));
#743=AXIS2_PLACEMENT_3D('',#740,#741,#742);
#744=PLANE('',#743);
#745=ORIENTED_EDGE('',*,*,#244,.F.);
#746=ORIENTED_EDGE('',*,*,#735,.F.);
#747=DIRECTION('',(0.,0.948844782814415,-0.315742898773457));
#748=VECTOR('',#747,1.);
#749=CARTESIAN_POINT('',(20.9,-3.15601850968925,22.2179));
#750=LINE('',#749,#748);
#751=CARTESIAN_POINT('',(20.9,-2.68631850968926,22.0616));
#752=VERTEX_POINT('',#751);
#753=EDGE_CURVE('P1_E1602',#728,#752,#750,.T.);
#754=ORIENTED_EDGE('',*,*,#753,.T.);
#755=DIRECTION('',(1.,0.,0.));
#756=VECTOR('',#755,1.);
#757=CARTESIAN_POINT('',(20.9,-2.68631850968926,22.0616));
#758=LINE('',#757,#756);
#759=EDGE_CURVE('P1_E993',#752,#179,#758,.T.);
#760=ORIENTED_EDGE('',*,*,#759,.T.);
#761=EDGE_LOOP('',(#745,#746,#754,#760));
#762=FACE_BOUND('',#761,.T.);
#763=ADVANCED_FACE('P1_F1251',(#762),#744,.T.);
#764=CARTESIAN_POINT('',(20.9,-2.68631850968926,22.0616));
#765=DIRECTION('',(0.,1.,0.));
#766=DIRECTION('',(1.,0.,0.));
#767=AXIS2_PLACEMENT_3D('',#764,#765,#766);
#768=PLANE('',#767);
#769=ORIENTED_EDGE('',*,*,#182,.F.);
#770=ORIENTED_EDGE('',*,*,#759,.F.);
#771=DIRECTION('',(0.,0.,1.));
#772=VECTOR('',#771,1.);
#773=CARTESIAN_POINT('',(20.9,-2.68631850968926,22.0616));
#774=LINE('',#773,#772);
#775=EDGE_CURVE('P1_E1628',#752,#576,#774,.T.);
#776=ORIENTED_EDGE('',*,*,#775,.T.);
#777=ORIENTED_EDGE('',*,*,#577,.T.);
#778=EDGE_LOOP('',(#769,#770,#776,#777));
#779=FACE_BOUND('',#778,.T.);
#780=ADVANCED_FACE('P1_F1252',(#779),#768,.T.);
#781=CARTESIAN_POINT('',(20.9,-2.69881850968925,18.0146));
#782=DIRECTION('',(0.,0.,1.));
#783=DIRECTION('',(1.,0.,0.));
#784=AXIS2_PLACEMENT_3D('',#781,#782,#783);
#785=PLANE('',#784);
#786=ORIENTED_EDGE('',*,*,#514,.F.);
#787=DIRECTION('',(1.,0.,0.));
#788=VECTOR('',#787,1.);
#789=CARTESIAN_POINT('',(20.9,-2.69881850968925,18.0146));
#790=LINE('',#789,#788);
#791=CARTESIAN_POINT('',(20.9,-2.69881850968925,18.0146));
#792=VERTEX_POINT('',#791);
#793=EDGE_CURVE('P1_E1015',#792,#505,#790,.T.);
#794=ORIENTED_EDGE('',*,*,#793,.F.);
#795=DIRECTION('',(0.,-1.,0.));
#796=VECTOR('',#795,1.);
#797=CARTESIAN_POINT('',(20.9,-2.69881850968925,18.0146));
#798=LINE('',#797,#796);
#799=CARTESIAN_POINT('',(20.9,-3.21521850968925,18.0146));
#800=VERTEX_POINT('',#799);
#801=EDGE_CURVE('P1_E1425',#792,#800,#798,.T.);
#802=ORIENTED_EDGE('',*,*,#801,.T.);
#803=DIRECTION('',(1.,0.,0.));
#804=VECTOR('',#803,1.);
#805=CARTESIAN_POINT('',(20.9,-3.21521850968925,18.0146));
#806=LINE('',#805,#804);
#807=EDGE_CURVE('P1_E941',#800,#513,#806,.T.);
#808=ORIENTED_EDGE('',*,*,#807,.T.);
#809=EDGE_LOOP('',(#786,#794,#802,#808));
#810=FACE_BOUND('',#809,.T.);
#811=ADVANCED_FACE('P1_F3337',(#810),#785,.T.);
#812=CARTESIAN_POINT('',(20.9,-3.21521850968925,18.0146));
#813=DIRECTION('',(0.,-1.,0.));
#814=DIRECTION('',(0.,0.,-1.));
#815=AXIS2_PLACEMENT_3D('',#812,#813,#814);
#816=PLANE('',#815);
#817=ORIENTED_EDGE('',*,*,#522,.F.);
#818=ORIENTED_EDGE('',*,*,#807,.F.);
#819=DIRECTION('',(0.,0.,-1.));
#820=VECTOR('',#819,1.);
#821=CARTESIAN_POINT('',(20.9,-3.21521850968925,18.0146));
#822=LINE('',#821,#820);
#823=CARTESIAN_POINT('',(20.9,-3.21521850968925,17.3627));
#824=VERTEX_POINT('',#823);
#825=EDGE_CURVE('P1_E1641',#800,#824,#822,.T.);
#826=ORIENTED_EDGE('',*,*,#825,.T.);
#827=DIRECTION('',(1.,0.,0.));
#828=VECTOR('',#827,1.);
#829=CARTESIAN_POINT('',(20.9,-3.21521850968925,17.3627));
#830=LINE('',#829,#828);
#831=EDGE_CURVE('P1_E942',#824,#521,#830,.T.);
#832=ORIENTED_EDGE('',*,*,#831,.T.);
#833=EDGE_LOOP('',(#817,#818,#826,#832));
#834=FACE_BOUND('',#833,.T.);
#835=ADVANCED_FACE('P1_F3333',(#834),#816,.T.);
#836=CARTESIAN_POINT('',(20.9,-3.21521850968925,17.3627));
#837=DIRECTION('',(0.,0.,1.));
#838=DIRECTION('',(1.,0.,0.));
#839=AXIS2_PLACEMENT_3D('',#836,#837,#838);
#840=PLANE('',#839);
#841=ORIENTED_EDGE('',*,*,#530,.F.);
#842=ORIENTED_EDGE('',*,*,#831,.F.);
#843=DIRECTION('',(0.,-1.,0.));
#844=VECTOR('',#843,1.);
#845=CARTESIAN_POINT('',(20.9,-3.21521850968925,17.3627));
#846=LINE('',#845,#844);
#847=CARTESIAN_POINT('',(20.9,-4.94241850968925,17.3627));
#848=VERTEX_POINT('',#847);
#849=EDGE_CURVE('P1_E1640',#824,#848,#846,.T.);
#850=ORIENTED_EDGE('',*,*,#849,.T.);
#851=DIRECTION('',(1.,0.,0.));
#852=VECTOR('',#851,1.);
#853=CARTESIAN_POINT('',(20.9,-4.94241850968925,17.3627));
#854=LINE('',#853,#852);
#855=EDGE_CURVE('P1_E1036',#848,#529,#854,.T.);
#856=ORIENTED_EDGE('',*,*,#855,.T.);
#857=EDGE_LOOP('',(#841,#842,#850,#856));
#858=FACE_BOUND('',#857,.T.);
#859=ADVANCED_FACE('P1_F3030',(#858),#840,.T.);
#860=CARTESIAN_POINT('',(20.9,-4.94241850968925,17.3627));
#861=DIRECTION('',(0.,-1.,0.));
#862=DIRECTION('',(0.,0.,-1.));
#863=AXIS2_PLACEMENT_3D('',#860,#861,#862);
#864=PLANE('',#863);
#865=ORIENTED_EDGE('',*,*,#538,.F.);
#866=ORIENTED_EDGE('',*,*,#855,.F.);
#867=DIRECTION('',(0.,0.,-1.));
#868=VECTOR('',#867,1.);
#869=CARTESIAN_POINT('',(20.9,-4.94241850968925,17.3627));
#870=LINE('',#869,#868);
#871=CARTESIAN_POINT('',(20.9,-4.94241850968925,16.8462));
#872=VERTEX_POINT('',#871);
#873=EDGE_CURVE('P1_E1632',#848,#872,#870,.T.);
#874=ORIENTED_EDGE('',*,*,#873,.T.);
#875=DIRECTION('',(1.,0.,0.));
#876=VECTOR('',#875,1.);
#877=CARTESIAN_POINT('',(20.9,-4.94241850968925,16.8462));
#878=LINE('',#877,#876);
#879=EDGE_CURVE('P1_E1029',#872,#537,#878,.T.);
#880=ORIENTED_EDGE('',*,*,#879,.T.);
#881=EDGE_LOOP('',(#865,#866,#874,#880));
#882=FACE_BOUND('',#881,.T.);
#883=ADVANCED_FACE('P1_F3022',(#882),#864,.T.);
#884=CARTESIAN_POINT('',(20.9,-4.94241850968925,16.8462));
#885=DIRECTION('',(0.,0.,-1.));
#886=DIRECTION('',(0.,-1.,0.));
#887=AXIS2_PLACEMENT_3D('',#884,#885,#886);
#888=PLANE('',#887);
#889=ORIENTED_EDGE('',*,*,#546,.F.);
#890=ORIENTED_EDGE('',*,*,#879,.F.);
#891=DIRECTION('',(0.,1.,0.));
#892=VECTOR('',#891,1.);
#893=CARTESIAN_POINT('',(20.9,-4.94241850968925,16.8462));
#894=LINE('',#893,#892);
#895=CARTESIAN_POINT('',(20.9,-3.21521850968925,16.8462));
#896=VERTEX_POINT('',#895);
#897=EDGE_CURVE('P1_E1633',#872,#896,#894,.T.);
#898=ORIENTED_EDGE('',*,*,#897,.T.);
#899=DIRECTION('',(1.,0.,0.));
#900=VECTOR('',#899,1.);
#901=CARTESIAN_POINT('',(20.9,-3.21521850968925,16.8462));
#902=LINE('',#901,#900);
#903=EDGE_CURVE('P1_E844',#896,#545,#902,.T.);
#904=ORIENTED_EDGE('',*,*,#903,.T.);
#905=EDGE_LOOP('',(#889,#890,#898,#904));
#906=FACE_BOUND('',#905,.T.);
#907=ADVANCED_FACE('P1_F1228',(#906),#888,.T.);
#908=CARTESIAN_POINT('',(20.9,-3.21521850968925,16.8462));
#909=DIRECTION('',(0.,-1.,0.));
#910=DIRECTION('',(0.,0.,-1.));
#911=AXIS2_PLACEMENT_3D('',#908,#909,#910);
#912=PLANE('',#911);
#913=ORIENTED_EDGE('',*,*,#554,.F.);
#914=ORIENTED_EDGE('',*,*,#903,.F.);
#915=DIRECTION('',(0.,0.,-1.));
#916=VECTOR('',#915,1.);
#917=CARTESIAN_POINT('',(20.9,-3.21521850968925,16.8462));
#918=LINE('',#917,#916);
#919=CARTESIAN_POINT('',(20.9,-3.21521850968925,16.1943));
#920=VERTEX_POINT('',#919);
#921=EDGE_CURVE('P1_E1636',#896,#920,#918,.T.);
#922=ORIENTED_EDGE('',*,*,#921,.T.);
#923=DIRECTION('',(1.,0.,0.));
#924=VECTOR('',#923,1.);
#925=CARTESIAN_POINT('',(20.9,-3.21521850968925,16.1943));
#926=LINE('',#925,#924);
#927=EDGE_CURVE('P1_E846',#920,#553,#926,.T.);
#928=ORIENTED_EDGE('',*,*,#927,.T.);
#929=EDGE_LOOP('',(#913,#914,#922,#928));
#930=FACE_BOUND('',#929,.T.);
#931=ADVANCED_FACE('P1_F1222',(#930),#912,.T.);
#932=CARTESIAN_POINT('',(20.9,-3.21521850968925,16.1943));
#933=DIRECTION('',(0.,0.,-1.));
#934=DIRECTION('',(0.,-1.,0.));
#935=AXIS2_PLACEMENT_3D('',#932,#933,#934);
#936=PLANE('',#935);
#937=ORIENTED_EDGE('',*,*,#560,.F.);
#938=ORIENTED_EDGE('',*,*,#927,.F.);
#939=DIRECTION('',(0.,1.,0.));
#940=VECTOR('',#939,1.);
#941=CARTESIAN_POINT('',(20.9,-3.21521850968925,16.1943));
#942=LINE('',#941,#940);
#943=CARTESIAN_POINT('',(20.9,-2.69881850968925,16.1943));
#944=VERTEX_POINT('',#943);
#945=EDGE_CURVE('P1_E1629',#920,#944,#942,.T.);
#946=ORIENTED_EDGE('',*,*,#945,.T.);
#947=DIRECTION('',(1.,0.,0.));
#948=VECTOR('',#947,1.);
#949=CARTESIAN_POINT('',(20.9,-2.69881850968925,16.1943));
#950=LINE('',#949,#948);
#951=EDGE_CURVE('P1_E1008',#944,#503,#950,.T.);
#952=ORIENTED_EDGE('',*,*,#951,.T.);
#953=EDGE_LOOP('',(#937,#938,#946,#952));
#954=FACE_BOUND('',#953,.T.);
#955=ADVANCED_FACE('P1_F1226',(#954),#936,.T.);
#956=CARTESIAN_POINT('',(20.9,-2.69881850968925,16.1943));
#957=DIRECTION('',(0.,1.,0.));
#958=DIRECTION('',(1.,0.,0.));
#959=AXIS2_PLACEMENT_3D('',#956,#957,#958);
#960=PLANE('',#959);
#961=ORIENTED_EDGE('',*,*,#506,.F.);
#962=ORIENTED_EDGE('',*,*,#951,.F.);
#963=DIRECTION('',(0.,0.,1.));
#964=VECTOR('',#963,1.);
#965=CARTESIAN_POINT('',(20.9,-2.69881850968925,16.1943));
#966=LINE('',#965,#964);
#967=EDGE_CURVE('P1_E1420',#944,#792,#966,.T.);
#968=ORIENTED_EDGE('',*,*,#967,.T.);
#969=ORIENTED_EDGE('',*,*,#793,.T.);
#970=EDGE_LOOP('',(#961,#962,#968,#969));
#971=FACE_BOUND('',#970,.T.);
#972=ADVANCED_FACE('P1_F1260',(#971),#960,.T.);
#973=CARTESIAN_POINT('',(20.9,1.85608149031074,16.0587));
#974=CARTESIAN_POINT('',(21.,1.85608149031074,16.0587));
#975=CARTESIAN_POINT('',(20.9,4.02578149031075,16.0587));
#976=CARTESIAN_POINT('',(21.,4.02578149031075,16.0587));
#977=CARTESIAN_POINT('',(20.9,5.78458149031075,17.8178));
#978=CARTESIAN_POINT('',(21.,5.78458149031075,17.8178));
#979=CARTESIAN_POINT('',(20.9,5.78458149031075,19.9874));
#980=CARTESIAN_POINT('',(21.,5.78458149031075,19.9874));
#981=(BOUNDED_SURFACE() B_SPLINE_SURFACE(3,1,((#973,#974),(#975,#976),(#977,#978),(#979,#980)),
.UNSPECIFIED.,.F.,.F.,.F.) B_SPLINE_SURFACE_WITH_KNOTS((4,4),(2,2),(0.1875,0.25),(0.,1.),
.UNSPECIFIED.) GEOMETRIC_REPRESENTATION_ITEM() RATIONAL_B_SPLINE_SURFACE(((1.,1.),(1.,1.),(1.,
1.),(1.,1.))) REPRESENTATION_ITEM('') SURFACE());
#982=DIRECTION('',(1.,0.,0.));
#983=VECTOR('',#982,1.);
#984=CARTESIAN_POINT('',(20.9,1.85608149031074,16.0587));
#985=LINE('',#984,#983);
#986=CARTESIAN_POINT('',(20.9,1.85608149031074,16.0587));
#987=VERTEX_POINT('',#986);
#988=EDGE_CURVE('P1_E886',#987,#370,#985,.T.);
#989=CARTESIAN_POINT('',(20.9,1.85608149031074,16.0587));
#990=CARTESIAN_POINT('',(20.9,4.02578149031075,16.0587));
#991=CARTESIAN_POINT('',(20.9,5.78458149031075,17.8178));
#992=CARTESIAN_POINT('',(20.9,5.78458149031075,19.9874));
#993=(BOUNDED_CURVE() B_SPLINE_CURVE(3,(#989,#990,#991,#992),.UNSPECIFIED.,.F.,
.F.) B_SPLINE_CURVE_WITH_KNOTS((4,4),(0.1875,0.25),
.UNSPECIFIED.) CURVE() GEOMETRIC_REPRESENTATION_ITEM() RATIONAL_B_SPLINE_CURVE((1.,1.,1.,1.)) REPRESENTATION_ITEM(''));
#994=CARTESIAN_POINT('',(20.9,5.78458149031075,19.9874));
#995=VERTEX_POINT('',#994);
#996=EDGE_CURVE('P1_E721',#987,#995,#993,.T.);
#997=DIRECTION('',(1.,0.,0.));
#998=VECTOR('',#997,1.);
#999=CARTESIAN_POINT('',(20.9,5.78458149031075,19.9874));
#1000=LINE('',#999,#998);
#1001=EDGE_CURVE('P1_E860',#995,#379,#1000,.T.);
#1002=ORIENTED_EDGE('',*,*,#380,.F.);
#1003=ORIENTED_EDGE('',*,*,#988,.F.);
#1004=ORIENTED_EDGE('',*,*,#996,.T.);
#1005=ORIENTED_EDGE('',*,*,#1001,.T.);
#1006=EDGE_LOOP('',(#1002,#1003,#1004,#1005));
#1007=FACE_BOUND('',#1006,.T.);
#1008=ADVANCED_FACE('P1_F1259',(#1007),#981,.T.);
#1009=CARTESIAN_POINT('',(20.9,5.78458149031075,19.9874));
#1010=CARTESIAN_POINT('',(21.,5.78458149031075,19.9874));
#1011=CARTESIAN_POINT('',(20.9,5.78458149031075,22.1568));
#1012=CARTESIAN_POINT('',(21.,5.78458149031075,22.1568));
#1013=CARTESIAN_POINT('',(20.9,4.02578149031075,23.9159));
#1014=CARTESIAN_POINT('',(21.,4.02578149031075,23.9159));
#1015=CARTESIAN_POINT('',(20.9,1.85608149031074,23.9159));
#1016=CARTESIAN_POINT('',(21.,1.85608149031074,23.9159));
#1017=(BOUNDED_SURFACE() B_SPLINE_SURFACE(3,1,((#1009,#1010),(#1011,#1012),(#1013,#1014),(#1015,
#1016)),.UNSPECIFIED.,.F.,.F.,.F.) B_SPLINE_SURFACE_WITH_KNOTS((4,4),(2,2),(0.25,0.3125),(0.,
1.),.UNSPECIFIED.) GEOMETRIC_REPRESENTATION_ITEM() RATIONAL_B_SPLINE_SURFACE(((1.,1.),(1.,1.),
(1.,1.),(1.,1.))) REPRESENTATION_ITEM('') SURFACE());
#1018=CARTESIAN_POINT('',(20.9,5.78458149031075,19.9874));
#1019=CARTESIAN_POINT('',(20.9,5.78458149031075,22.1568));
#1020=CARTESIAN_POINT('',(20.9,4.02578149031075,23.9159));
#1021=CARTESIAN_POINT('',(20.9,1.85608149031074,23.9159));
#1022=(BOUNDED_CURVE() B_SPLINE_CURVE(3,(#1018,#1019,#1020,#1021),.UNSPECIFIED.,.F.,
.F.) B_SPLINE_CURVE_WITH_KNOTS((4,4),(0.25,0.3125),
.UNSPECIFIED.) CURVE() GEOMETRIC_REPRESENTATION_ITEM() RATIONAL_B_SPLINE_CURVE((1.,1.,1.,1.)) REPRESENTATION_ITEM(''));
#1023=CARTESIAN_POINT('',(20.9,1.85608149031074,23.9159));
#1024=VERTEX_POINT('',#1023);
#1025=EDGE_CURVE('P1_E1693',#995,#1024,#1022,.T.);
#1026=DIRECTION('',(1.,0.,0.));
#1027=VECTOR('',#1026,1.);
#1028=CARTESIAN_POINT('',(20.9,1.85608149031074,23.9159));
#1029=LINE('',#1028,#1027);
#1030=EDGE_CURVE('P1_E987',#1024,#388,#1029,.T.);
#1031=ORIENTED_EDGE('',*,*,#389,.F.);
#1032=ORIENTED_EDGE('',*,*,#1001,.F.);
#1033=ORIENTED_EDGE('',*,*,#1025,.T.);
#1034=ORIENTED_EDGE('',*,*,#1030,.T.);
#1035=EDGE_LOOP('',(#1031,#1032,#1033,#1034));
#1036=FACE_BOUND('',#1035,.T.);
#1037=ADVANCED_FACE('P1_F1731',(#1036),#1017,.T.);
#1038=CARTESIAN_POINT('',(20.9,1.85608149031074,23.9159));
#1039=CARTESIAN_POINT('',(21.,1.85608149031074,23.9159));
#1040=CARTESIAN_POINT('',(20.9,-0.23111850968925,23.9159));
#1041=CARTESIAN_POINT('',(21.,-0.23111850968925,23.9159));
#1042=CARTESIAN_POINT('',(20.9,-1.93761850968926,22.288));
#1043=CARTESIAN_POINT('',(21.,-1.93761850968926,22.288));
#1044=CARTESIAN_POINT('',(20.9,-2.06441850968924,20.2328));
#1045=CARTESIAN_POINT('',(21.,-2.06441850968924,20.2328));
#1046=(BOUNDED_SURFACE() B_SPLINE_SURFACE(3,1,((#1038,#1039),(#1040,#1041),(#1042,#1043),(#1044,
#1045)),.UNSPECIFIED.,.F.,.F.,.F.) B_SPLINE_SURFACE_WITH_KNOTS((4,4),(2,2),(0.3125,0.375),(0.,
1.),.UNSPECIFIED.) GEOMETRIC_REPRESENTATION_ITEM() RATIONAL_B_SPLINE_SURFACE(((1.,1.),(1.,1.),
(1.,1.),(1.,1.))) REPRESENTATION_ITEM('') SURFACE());
#1047=CARTESIAN_POINT('',(20.9,1.85608149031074,23.9159));
#1048=CARTESIAN_POINT('',(20.9,-0.23111850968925,23.9159));
#1049=CARTESIAN_POINT('',(20.9,-1.93761850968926,22.288));
#1050=CARTESIAN_POINT('',(20.9,-2.06441850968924,20.2328));
#1051=(BOUNDED_CURVE() B_SPLINE_CURVE(3,(#1047,#1048,#1049,#1050),.UNSPECIFIED.,.F.,
.F.) B_SPLINE_CURVE_WITH_KNOTS((4,4),(0.3125,0.375),
.UNSPECIFIED.) CURVE() GEOMETRIC_REPRESENTATION_ITEM() RATIONAL_B_SPLINE_CURVE((1.,1.,1.,1.)) REPRESENTATION_ITEM(''));
#1052=CARTESIAN_POINT('',(20.9,-2.06441850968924,20.2328));
#1053=VERTEX_POINT('',#1052);
#1054=EDGE_CURVE('P1_E1391',#1024,#1053,#1051,.T.);
#1055=DIRECTION('',(1.,0.,0.));
#1056=VECTOR('',#1055,1.);
#1057=CARTESIAN_POINT('',(20.9,-2.06441850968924,20.2328));
#1058=LINE('',#1057,#1056);
#1059=EDGE_CURVE('P1_E983',#1053,#397,#1058,.T.);
#1060=ORIENTED_EDGE('',*,*,#398,.F.);
#1061=ORIENTED_EDGE('',*,*,#1030,.F.);
#1062=ORIENTED_EDGE('',*,*,#1054,.T.);
#1063=ORIENTED_EDGE('',*,*,#1059,.T.);
#1064=EDGE_LOOP('',(#1060,#1061,#1062,#1063));
#1065=FACE_BOUND('',#1064,.T.);
#1066=ADVANCED_FACE('P1_F2950',(#1065),#1046,.T.);
#1067=CARTESIAN_POINT('',(20.9,-2.06441850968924,20.2328));
#1068=DIRECTION('',(0.,0.,-1.));
#1069=DIRECTION('',(0.,-1.,0.));
#1070=AXIS2_PLACEMENT_3D('',#1067,#1068,#1069);
#1071=PLANE('',#1070);
#1072=ORIENTED_EDGE('',*,*,#406,.F.);
#1073=ORIENTED_EDGE('',*,*,#1059,.F.);
#1074=DIRECTION('',(0.,1.,0.));
#1075=VECTOR('',#1074,1.);
#1076=CARTESIAN_POINT('',(20.9,-2.06441850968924,20.2328));
#1077=LINE('',#1076,#1075);
#1078=CARTESIAN_POINT('',(20.9,-0.175218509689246,20.2328));
#1079=VERTEX_POINT('',#1078);
#1080=EDGE_CURVE('P1_E1388',#1053,#1079,#1077,.T.);
#1081=ORIENTED_EDGE('',*,*,#1080,.T.);
#1082=DIRECTION('',(1.,0.,0.));
#1083=VECTOR('',#1082,1.);
#1084=CARTESIAN_POINT('',(20.9,-0.175218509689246,20.2328));
#1085=LINE('',#1084,#1083);
#1086=EDGE_CURVE('P1_E978',#1079,#405,#1085,.T.);
#1087=ORIENTED_EDGE('',*,*,#1086,.T.);
#1088=EDGE_LOOP('',(#1072,#1073,#1081,#1087));
#1089=FACE_BOUND('',#1088,.T.);
#1090=ADVANCED_FACE('P1_F3281',(#1089),#1071,.T.);
#1091=CARTESIAN_POINT('',(20.9,-0.175218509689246,20.2328));
#1092=DIRECTION('',(0.,1.,0.));
#1093=DIRECTION('',(1.,0.,0.));
#1094=AXIS2_PLACEMENT_3D('',#1091,#1092,#1093);
#1095=PLANE('',#1094);
#1096=ORIENTED_EDGE('',*,*,#414,.F.);
#1097=ORIENTED_EDGE('',*,*,#1086,.F.);
#1098=DIRECTION('',(0.,0.,1.));
#1099=VECTOR('',#1098,1.);
#1100=CARTESIAN_POINT('',(20.9,-0.175218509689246,20.2328));
#1101=LINE('',#1100,#1099);
#1102=CARTESIAN_POINT('',(20.9,-0.175218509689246,21.5695));
#1103=VERTEX_POINT('',#1102);
#1104=EDGE_CURVE('P1_E1393',#1079,#1103,#1101,.T.);
#1105=ORIENTED_EDGE('',*,*,#1104,.T.);
#1106=DIRECTION('',(1.,0.,0.));
#1107=VECTOR('',#1106,1.);
#1108=CARTESIAN_POINT('',(20.9,-0.175218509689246,21.5695));
#1109=LINE('',#1108,#1107);
#1110=EDGE_CURVE('P1_E966',#1103,#413,#1109,.T.);
#1111=ORIENTED_EDGE('',*,*,#1110,.T.);
#1112=EDGE_LOOP('',(#1096,#1097,#1105,#1111));
#1113=FACE_BOUND('',#1112,.T.);
#1114=ADVANCED_FACE('P1_F3069',(#1113),#1095,.T.);
#1115=CARTESIAN_POINT('',(20.9,-0.175218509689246,21.5695));
#1116=CARTESIAN_POINT('',(21.,-0.175218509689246,21.5695));
#1117=CARTESIAN_POINT('',(20.9,-0.175218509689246,21.7375));
#1118=CARTESIAN_POINT('',(21.,-0.175218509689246,21.7375));
#1119=CARTESIAN_POINT('',(20.9,-0.0379185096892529,21.8747));
#1120=CARTESIAN_POINT('',(21.,-0.0379185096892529,21.8747));
#1121=CARTESIAN_POINT('',(20.9,0.129781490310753,21.8747));
#1122=CARTESIAN_POINT('',(21.,0.129781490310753,21.8747));
#1123=(BOUNDED_SURFACE() B_SPLINE_SURFACE(3,1,((#1115,#1116),(#1117,#1118),(#1119,#1120),(#1121,
#1122)),.UNSPECIFIED.,.F.,.F.,.F.) B_SPLINE_SURFACE_WITH_KNOTS((4,4),(2,2),(0.5,0.5625),(0.,1.),
.UNSPECIFIED.) GEOMETRIC_REPRESENTATION_ITEM() RATIONAL_B_SPLINE_SURFACE(((1.,1.),(1.,1.),(1.,
1.),(1.,1.))) REPRESENTATION_ITEM('') SURFACE());
#1124=CARTESIAN_POINT('',(20.9,-0.175218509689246,21.5695));
#1125=CARTESIAN_POINT('',(20.9,-0.175218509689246,21.7375));
#1126=CARTESIAN_POINT('',(20.9,-0.0379185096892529,21.8747));
#1127=CARTESIAN_POINT('',(20.9,0.129781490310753,21.8747));
#1128=(BOUNDED_CURVE() B_SPLINE_CURVE(3,(#1124,#1125,#1126,#1127),.UNSPECIFIED.,.F.,
.F.) B_SPLINE_CURVE_WITH_KNOTS((4,4),(0.5,0.5625),
.UNSPECIFIED.) CURVE() GEOMETRIC_REPRESENTATION_ITEM() RATIONAL_B_SPLINE_CURVE((1.,1.,1.,1.)) REPRESENTATION_ITEM(''));
#1129=CARTESIAN_POINT('',(20.9,0.129781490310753,21.8747));
#1130=VERTEX_POINT('',#1129);
#1131=EDGE_CURVE('P1_E1678',#1103,#1130,#1128,.T.);
#1132=DIRECTION('',(1.,0.,0.));
#1133=VECTOR('',#1132,1.);
#1134=CARTESIAN_POINT('',(20.9,0.129781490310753,21.8747));
#1135=LINE('',#1134,#1133);
#1136=EDGE_CURVE('P1_E911',#1130,#422,#1135,.T.);
#1137=ORIENTED_EDGE('',*,*,#423,.F.);
#1138=ORIENTED_EDGE('',*,*,#1110,.F.);
#1139=ORIENTED_EDGE('',*,*,#1131,.T.);
#1140=ORIENTED_EDGE('',*,*,#1136,.T.);
#1141=EDGE_LOOP('',(#1137,#1138,#1139,#1140));
#1142=FACE_BOUND('',#1141,.T.);
#1143=ADVANCED_FACE('P1_F3062',(#1142),#1123,.T.);
#1144=CARTESIAN_POINT('',(20.9,0.129781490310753,21.8747));
#1145=DIRECTION('',(0.,0.,-1.));
#1146=DIRECTION('',(0.,-1.,0.));
#1147=AXIS2_PLACEMENT_3D('',#1144,#1145,#1146);
#1148=PLANE('',#1147);
#1149=ORIENTED_EDGE('',*,*,#431,.F.);
#1150=ORIENTED_EDGE('',*,*,#1136,.F.);
#1151=DIRECTION('',(0.,1.,0.));
#1152=VECTOR('',#1151,1.);
#1153=CARTESIAN_POINT('',(20.9,0.129781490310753,21.8747));
#1154=LINE('',#1153,#1152);
#1155=CARTESIAN_POINT('',(20.9,3.29448149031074,21.8747));
#1156=VERTEX_POINT('',#1155);
#1157=EDGE_CURVE('P1_E1548',#1130,#1156,#1154,.T.);
#1158=ORIENTED_EDGE('',*,*,#1157,.T.);
#1159=DIRECTION('',(1.,0.,0.));
#1160=VECTOR('',#1159,1.);
#1161=CARTESIAN_POINT('',(20.9,3.29448149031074,21.8747));
#1162=LINE('',#1161,#1160);
#1163=EDGE_CURVE('P1_E915',#1156,#430,#1162,.T.);
#1164=ORIENTED_EDGE('',*,*,#1163,.T.);
#1165=EDGE_LOOP('',(#1149,#1150,#1158,#1164));
#1166=FACE_BOUND('',#1165,.T.);
#1167=ADVANCED_FACE('P1_F3067',(#1166),#1148,.T.);
#1168=CARTESIAN_POINT('',(20.9,3.29448149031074,21.8747));
#1169=CARTESIAN_POINT('',(21.,3.29448149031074,21.8747));
#1170=CARTESIAN_POINT('',(20.9,3.46218149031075,21.8747));
#1171=CARTESIAN_POINT('',(21.,3.46218149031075,21.8747));
#1172=CARTESIAN_POINT('',(20.9,3.59968149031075,21.7375));
#1173=CARTESIAN_POINT('',(21.,3.59968149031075,21.7375));
#1174=CARTESIAN_POINT('',(20.9,3.59968149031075,21.5695));
#1175=CARTESIAN_POINT('',(21.,3.59968149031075,21.5695));
#1176=(BOUNDED_SURFACE() B_SPLINE_SURFACE(3,1,((#1168,#1169),(#1170,#1171),(#1172,#1173),(#1174,
#1175)),.UNSPECIFIED.,.F.,.F.,.F.) B_SPLINE_SURFACE_WITH_KNOTS((4,4),(2,2),(0.625,0.6875),(0.,
1.),.UNSPECIFIED.) GEOMETRIC_REPRESENTATION_ITEM() RATIONAL_B_SPLINE_SURFACE(((1.,1.),(1.,1.),
(1.,1.),(1.,1.))) REPRESENTATION_ITEM('') SURFACE());
#1177=CARTESIAN_POINT('',(20.9,3.29448149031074,21.8747));
#1178=CARTESIAN_POINT('',(20.9,3.46218149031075,21.8747));
#1179=CARTESIAN_POINT('',(20.9,3.59968149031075,21.7375));
#1180=CARTESIAN_POINT('',(20.9,3.59968149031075,21.5695));
#1181=(BOUNDED_CURVE() B_SPLINE_CURVE(3,(#1177,#1178,#1179,#1180),.UNSPECIFIED.,.F.,
.F.) B_SPLINE_CURVE_WITH_KNOTS((4,4),(0.625,0.6875),
.UNSPECIFIED.) CURVE() GEOMETRIC_REPRESENTATION_ITEM() RATIONAL_B_SPLINE_CURVE((1.,1.,1.,1.)) REPRESENTATION_ITEM(''));
#1182=CARTESIAN_POINT('',(20.9,3.59968149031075,21.5695));
#1183=VERTEX_POINT('',#1182);
#1184=EDGE_CURVE('P1_E1544',#1156,#1183,#1181,.T.);
#1185=DIRECTION('',(1.,0.,0.));
#1186=VECTOR('',#1185,1.);
#1187=CARTESIAN_POINT('',(20.9,3.59968149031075,21.5695));
#1188=LINE('',#1187,#1186);
#1189=EDGE_CURVE('P1_E945',#1183,#439,#1188,.T.);
#1190=ORIENTED_EDGE('',*,*,#440,.F.);
#1191=ORIENTED_EDGE('',*,*,#1163,.F.);
#1192=ORIENTED_EDGE('',*,*,#1184,.T.);
#1193=ORIENTED_EDGE('',*,*,#1189,.T.);
#1194=EDGE_LOOP('',(#1190,#1191,#1192,#1193));
#1195=FACE_BOUND('',#1194,.T.);
#1196=ADVANCED_FACE('P1_F3258',(#1195),#1176,.T.);
#1197=CARTESIAN_POINT('',(20.9,3.59968149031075,21.5695));
#1198=DIRECTION('',(0.,-1.,0.));
#1199=DIRECTION('',(0.,0.,-1.));
#1200=AXIS2_PLACEMENT_3D('',#1197,#1198,#1199);
#1201=PLANE('',#1200);
#1202=ORIENTED_EDGE('',*,*,#448,.F.);
#1203=ORIENTED_EDGE('',*,*,#1189,.F.);
#1204=DIRECTION('',(0.,0.,-1.));
#1205=VECTOR('',#1204,1.);
#1206=CARTESIAN_POINT('',(20.9,3.59968149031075,21.5695));
#1207=LINE('',#1206,#1205);
#1208=CARTESIAN_POINT('',(20.9,3.59968149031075,18.4051));
#1209=VERTEX_POINT('',#1208);
#1210=EDGE_CURVE('P1_E1550',#1183,#1209,#1207,.T.);
#1211=ORIENTED_EDGE('',*,*,#1210,.T.);
#1212=DIRECTION('',(1.,0.,0.));
#1213=VECTOR('',#1212,1.);
#1214=CARTESIAN_POINT('',(20.9,3.59968149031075,18.4051));
#1215=LINE('',#1214,#1213);
#1216=EDGE_CURVE('P1_E929',#1209,#447,#1215,.T.);
#1217=ORIENTED_EDGE('',*,*,#1216,.T.);
#1218=EDGE_LOOP('',(#1202,#1203,#1211,#1217));
#1219=FACE_BOUND('',#1218,.T.);
#1220=ADVANCED_FACE('P1_F3094',(#1219),#1201,.T.);
#1221=CARTESIAN_POINT('',(20.9,3.59968149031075,18.4051));
#1222=CARTESIAN_POINT('',(21.,3.59968149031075,18.4051));
#1223=CARTESIAN_POINT('',(20.9,3.59968149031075,18.2371));
#1224=CARTESIAN_POINT('',(21.,3.59968149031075,18.2371));
#1225=CARTESIAN_POINT('',(20.9,3.46218149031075,18.0999));
#1226=CARTESIAN_POINT('',(21.,3.46218149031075,18.0999));
#1227=CARTESIAN_POINT('',(20.9,3.29448149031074,18.0999));
#1228=CARTESIAN_POINT('',(21.,3.29448149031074,18.0999));
#1229=(BOUNDED_SURFACE() B_SPLINE_SURFACE(3,1,((#1221,#1222),(#1223,#1224),(#1225,#1226),(#1227,
#1228)),.UNSPECIFIED.,.F.,.F.,.F.) B_SPLINE_SURFACE_WITH_KNOTS((4,4),(2,2),(0.75,0.8125),(0.,
1.),.UNSPECIFIED.) GEOMETRIC_REPRESENTATION_ITEM() RATIONAL_B_SPLINE_SURFACE(((1.,1.),(1.,1.),
(1.,1.),(1.,1.))) REPRESENTATION_ITEM('') SURFACE());
#1230=CARTESIAN_POINT('',(20.9,3.59968149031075,18.4051));
#1231=CARTESIAN_POINT('',(20.9,3.59968149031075,18.2371));
#1232=CARTESIAN_POINT('',(20.9,3.46218149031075,18.0999));
#1233=CARTESIAN_POINT('',(20.9,3.29448149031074,18.0999));
#1234=(BOUNDED_CURVE() B_SPLINE_CURVE(3,(#1230,#1231,#1232,#1233),.UNSPECIFIED.,.F.,
.F.) B_SPLINE_CURVE_WITH_KNOTS((4,4),(0.75,0.8125),
.UNSPECIFIED.) CURVE() GEOMETRIC_REPRESENTATION_ITEM() RATIONAL_B_SPLINE_CURVE((1.,1.,1.,1.)) REPRESENTATION_ITEM(''));
#1235=CARTESIAN_POINT('',(20.9,3.29448149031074,18.0999));
#1236=VERTEX_POINT('',#1235);
#1237=EDGE_CURVE('P1_E1663',#1209,#1236,#1234,.T.);
#1238=DIRECTION('',(1.,0.,0.));
#1239=VECTOR('',#1238,1.);
#1240=CARTESIAN_POINT('',(20.9,3.29448149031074,18.0999));
#1241=LINE('',#1240,#1239);
#1242=EDGE_CURVE('P1_E921',#1236,#456,#1241,.T.);
#1243=ORIENTED_EDGE('',*,*,#457,.F.);
#1244=ORIENTED_EDGE('',*,*,#1216,.F.);
#1245=ORIENTED_EDGE('',*,*,#1237,.T.);
#1246=ORIENTED_EDGE('',*,*,#1242,.T.);
#1247=EDGE_LOOP('',(#1243,#1244,#1245,#1246));
#1248=FACE_BOUND('',#1247,.T.);
#1249=ADVANCED_FACE('P1_F3090',(#1248),#1229,.T.);
#1250=CARTESIAN_POINT('',(20.9,3.29448149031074,18.0999));
#1251=DIRECTION('',(0.,0.,1.));
#1252=DIRECTION('',(1.,0.,0.));
#1253=AXIS2_PLACEMENT_3D('',#1250,#1251,#1252);
#1254=PLANE('',#1253);
#1255=ORIENTED_EDGE('',*,*,#465,.F.);
#1256=ORIENTED_EDGE('',*,*,#1242,.F.);
#1257=DIRECTION('',(0.,-1.,0.));
#1258=VECTOR('',#1257,1.);
#1259=CARTESIAN_POINT('',(20.9,3.29448149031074,18.0999));
#1260=LINE('',#1259,#1258);
#1261=CARTESIAN_POINT('',(20.9,0.129781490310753,18.0999));
#1262=VERTEX_POINT('',#1261);
#1263=EDGE_CURVE('P1_E1654',#1236,#1262,#1260,.T.);
#1264=ORIENTED_EDGE('',*,*,#1263,.T.);
#1265=DIRECTION('',(1.,0.,0.));
#1266=VECTOR('',#1265,1.);
#1267=CARTESIAN_POINT('',(20.9,0.129781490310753,18.0999));
#1268=LINE('',#1267,#1266);
#1269=EDGE_CURVE('P1_E907',#1262,#464,#1268,.T.);
#1270=ORIENTED_EDGE('',*,*,#1269,.T.);
#1271=EDGE_LOOP('',(#1255,#1256,#1264,#1270));
#1272=FACE_BOUND('',#1271,.T.);
#1273=ADVANCED_FACE('P1_F3092',(#1272),#1254,.T.);
#1274=CARTESIAN_POINT('',(20.9,0.129781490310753,18.0999));
#1275=CARTESIAN_POINT('',(21.,0.129781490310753,18.0999));
#1276=CARTESIAN_POINT('',(20.9,-0.0379185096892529,18.0999));
#1277=CARTESIAN_POINT('',(21.,-0.0379185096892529,18.0999));
#1278=CARTESIAN_POINT('',(20.9,-0.175218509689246,18.2371));
#1279=CARTESIAN_POINT('',(21.,-0.175218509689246,18.2371));
#1280=CARTESIAN_POINT('',(20.9,-0.175218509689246,18.4051));
#1281=CARTESIAN_POINT('',(21.,-0.175218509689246,18.4051));
#1282=(BOUNDED_SURFACE() B_SPLINE_SURFACE(3,1,((#1274,#1275),(#1276,#1277),(#1278,#1279),(#1280,
#1281)),.UNSPECIFIED.,.F.,.F.,.F.) B_SPLINE_SURFACE_WITH_KNOTS((4,4),(2,2),(0.875,0.9375),(0.,
1.),.UNSPECIFIED.) GEOMETRIC_REPRESENTATION_ITEM() RATIONAL_B_SPLINE_SURFACE(((1.,1.),(1.,1.),
(1.,1.),(1.,1.))) REPRESENTATION_ITEM('') SURFACE());
#1283=CARTESIAN_POINT('',(20.9,0.129781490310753,18.0999));
#1284=CARTESIAN_POINT('',(20.9,-0.0379185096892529,18.0999));
#1285=CARTESIAN_POINT('',(20.9,-0.175218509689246,18.2371));
#1286=CARTESIAN_POINT('',(20.9,-0.175218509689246,18.4051));
#1287=(BOUNDED_CURVE() B_SPLINE_CURVE(3,(#1283,#1284,#1285,#1286),.UNSPECIFIED.,.F.,
.F.) B_SPLINE_CURVE_WITH_KNOTS((4,4),(0.875,0.9375),
.UNSPECIFIED.) CURVE() GEOMETRIC_REPRESENTATION_ITEM() RATIONAL_B_SPLINE_CURVE((1.,1.,1.,1.)) REPRESENTATION_ITEM(''));
#1288=CARTESIAN_POINT('',(20.9,-0.175218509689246,18.4051));
#1289=VERTEX_POINT('',#1288);
#1290=EDGE_CURVE('P1_E1446',#1262,#1289,#1287,.T.);
#1291=DIRECTION('',(1.,0.,0.));
#1292=VECTOR('',#1291,1.);
#1293=CARTESIAN_POINT('',(20.9,-0.175218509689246,18.4051));
#1294=LINE('',#1293,#1292);
#1295=EDGE_CURVE('P1_E899',#1289,#473,#1294,.T.);
#1296=ORIENTED_EDGE('',*,*,#474,.F.);
#1297=ORIENTED_EDGE('',*,*,#1269,.F.);
#1298=ORIENTED_EDGE('',*,*,#1290,.T.);
#1299=ORIENTED_EDGE('',*,*,#1295,.T.);
#1300=EDGE_LOOP('',(#1296,#1297,#1298,#1299));
#1301=FACE_BOUND('',#1300,.T.);
#1302=ADVANCED_FACE('P1_F3185',(#1301),#1282,.T.);
#1303=CARTESIAN_POINT('',(20.9,-0.175218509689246,18.4051));
#1304=DIRECTION('',(0.,1.,0.));
#1305=DIRECTION('',(1.,0.,0.));
#1306=AXIS2_PLACEMENT_3D('',#1303,#1304,#1305);
#1307=PLANE('',#1306);
#1308=ORIENTED_EDGE('',*,*,#482,.F.);
#1309=ORIENTED_EDGE('',*,*,#1295,.F.);
#1310=DIRECTION('',(0.,0.,1.));
#1311=VECTOR('',#1310,1.);
#1312=CARTESIAN_POINT('',(20.9,-0.175218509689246,18.4051));
#1313=LINE('',#1312,#1311);
#1314=CARTESIAN_POINT('',(20.9,-0.175218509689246,19.7418));
#1315=VERTEX_POINT('',#1314);
#1316=EDGE_CURVE('P1_E1443',#1289,#1315,#1313,.T.);
#1317=ORIENTED_EDGE('',*,*,#1316,.T.);
#1318=DIRECTION('',(1.,0.,0.));
#1319=VECTOR('',#1318,1.);
#1320=CARTESIAN_POINT('',(20.9,-0.175218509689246,19.7418));
#1321=LINE('',#1320,#1319);
#1322=EDGE_CURVE('P1_E893',#1315,#481,#1321,.T.);
#1323=ORIENTED_EDGE('',*,*,#1322,.T.);
#1324=EDGE_LOOP('',(#1308,#1309,#1317,#1323));
#1325=FACE_BOUND('',#1324,.T.);
#1326=ADVANCED_FACE('P1_F3233',(#1325),#1307,.T.);
#1327=CARTESIAN_POINT('',(20.9,-0.175218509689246,19.7418));
#1328=DIRECTION('',(0.,0.,1.));
#1329=DIRECTION('',(1.,0.,0.));
#1330=AXIS2_PLACEMENT_3D('',#1327,#1328,#1329);
#1331=PLANE('',#1330);
#1332=ORIENTED_EDGE('',*,*,#488,.F.);
#1333=ORIENTED_EDGE('',*,*,#1322,.F.);
#1334=DIRECTION('',(0.,-1.,0.));
#1335=VECTOR('',#1334,1.);
#1336=CARTESIAN_POINT('',(20.9,-0.175218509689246,19.7418));
#1337=LINE('',#1336,#1335);
#1338=CARTESIAN_POINT('',(20.9,-2.06441850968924,19.7418));
#1339=VERTEX_POINT('',#1338);
#1340=EDGE_CURVE('P1_E1421',#1315,#1339,#1337,.T.);
#1341=ORIENTED_EDGE('',*,*,#1340,.T.);
#1342=DIRECTION('',(1.,0.,0.));
#1343=VECTOR('',#1342,1.);
#1344=CARTESIAN_POINT('',(20.9,-2.06441850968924,19.7418));
#1345=LINE('',#1344,#1343);
#1346=EDGE_CURVE('P1_E878',#1339,#368,#1345,.T.);
#1347=ORIENTED_EDGE('',*,*,#1346,.T.);
#1348=EDGE_LOOP('',(#1332,#1333,#1341,#1347));
#1349=FACE_BOUND('',#1348,.T.);
#1350=ADVANCED_FACE('P1_F2894',(#1349),#1331,.T.);
#1351=CARTESIAN_POINT('',(20.9,-2.06441850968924,19.7418));
#1352=CARTESIAN_POINT('',(21.,-2.06441850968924,19.7418));
#1353=CARTESIAN_POINT('',(20.9,-1.93761850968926,17.6866));
#1354=CARTESIAN_POINT('',(21.,-1.93761850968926,17.6866));
#1355=CARTESIAN_POINT('',(20.9,-0.23111850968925,16.0587));
#1356=CARTESIAN_POINT('',(21.,-0.23111850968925,16.0587));
#1357=CARTESIAN_POINT('',(20.9,1.85608149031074,16.0587));
#1358=CARTESIAN_POINT('',(21.,1.85608149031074,16.0587));
#1359=(BOUNDED_SURFACE() B_SPLINE_SURFACE(3,1,((#1351,#1352),(#1353,#1354),(#1355,#1356),(#1357,
#1358)),.UNSPECIFIED.,.F.,.F.,.F.) B_SPLINE_SURFACE_WITH_KNOTS((4,4),(2,2),(0.125,0.1875),(0.,
1.),.UNSPECIFIED.) GEOMETRIC_REPRESENTATION_ITEM() RATIONAL_B_SPLINE_SURFACE(((1.,1.),(1.,1.),
(1.,1.),(1.,1.))) REPRESENTATION_ITEM('') SURFACE());
#1360=CARTESIAN_POINT('',(20.9,-2.06441850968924,19.7418));
#1361=CARTESIAN_POINT('',(20.9,-1.93761850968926,17.6866));
#1362=CARTESIAN_POINT('',(20.9,-0.23111850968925,16.0587));
#1363=CARTESIAN_POINT('',(20.9,1.85608149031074,16.0587));
#1364=(BOUNDED_CURVE() B_SPLINE_CURVE(3,(#1360,#1361,#1362,#1363),.UNSPECIFIED.,.F.,
.F.) B_SPLINE_CURVE_WITH_KNOTS((4,4),(0.125,0.1875),
.UNSPECIFIED.) CURVE() GEOMETRIC_REPRESENTATION_ITEM() RATIONAL_B_SPLINE_CURVE((1.,1.,1.,1.)) REPRESENTATION_ITEM(''));
#1365=EDGE_CURVE('P1_E714',#1339,#987,#1364,.T.);
#1366=ORIENTED_EDGE('',*,*,#371,.F.);
#1367=ORIENTED_EDGE('',*,*,#1346,.F.);
#1368=ORIENTED_EDGE('',*,*,#1365,.T.);
#1369=ORIENTED_EDGE('',*,*,#988,.T.);
#1370=EDGE_LOOP('',(#1366,#1367,#1368,#1369));
#1371=FACE_BOUND('',#1370,.T.);
#1372=ADVANCED_FACE('P1_F1120',(#1371),#1359,.T.);
#1373=CARTESIAN_POINT('',(20.9,-3.82921850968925,19.2382));
#1374=CARTESIAN_POINT('',(21.,-3.82921850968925,19.2382));
#1375=CARTESIAN_POINT('',(20.9,-4.16521850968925,19.2382));
#1376=CARTESIAN_POINT('',(21.,-4.16521850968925,19.2382));
#1377=CARTESIAN_POINT('',(20.9,-4.44041850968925,19.5131));
#1378=CARTESIAN_POINT('',(21.,-4.44041850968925,19.5131));
#1379=CARTESIAN_POINT('',(20.9,-4.44041850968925,19.8494));
#1380=CARTESIAN_POINT('',(21.,-4.44041850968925,19.8494));
#1381=(BOUNDED_SURFACE() B_SPLINE_SURFACE(3,1,((#1373,#1374),(#1375,#1376),(#1377,#1378),(#1379,
#1380)),.UNSPECIFIED.,.F.,.F.,.F.) B_SPLINE_SURFACE_WITH_KNOTS((4,4),(2,2),(0.5,0.5625),(0.,1.),
.UNSPECIFIED.) GEOMETRIC_REPRESENTATION_ITEM() RATIONAL_B_SPLINE_SURFACE(((1.,1.),(1.,1.),(1.,
1.),(1.,1.))) REPRESENTATION_ITEM('') SURFACE());
#1382=DIRECTION('',(1.,0.,0.));
#1383=VECTOR('',#1382,1.);
#1384=CARTESIAN_POINT('',(20.9,-3.82921850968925,19.2382));
#1385=LINE('',#1384,#1383);
#1386=CARTESIAN_POINT('',(20.9,-3.82921850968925,19.2382));
#1387=VERTEX_POINT('',#1386);
#1388=EDGE_CURVE('P1_E782',#1387,#262,#1385,.T.);
#1389=CARTESIAN_POINT('',(20.9,-3.82921850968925,19.2382));
#1390=CARTESIAN_POINT('',(20.9,-4.16521850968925,19.2382));
#1391=CARTESIAN_POINT('',(20.9,-4.44041850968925,19.5131));
#1392=CARTESIAN_POINT('',(20.9,-4.44041850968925,19.8494));
#1393=(BOUNDED_CURVE() B_SPLINE_CURVE(3,(#1389,#1390,#1391,#1392),.UNSPECIFIED.,.F.,
.F.) B_SPLINE_CURVE_WITH_KNOTS((4,4),(0.5,0.5625),
.UNSPECIFIED.) CURVE() GEOMETRIC_REPRESENTATION_ITEM() RATIONAL_B_SPLINE_CURVE((1.,1.,1.,1.)) REPRESENTATION_ITEM(''));
#1394=CARTESIAN_POINT('',(20.9,-4.44041850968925,19.8494));
#1395=VERTEX_POINT('',#1394);
#1396=EDGE_CURVE('P1_E756',#1387,#1395,#1393,.T.);
#1397=DIRECTION('',(1.,0.,0.));
#1398=VECTOR('',#1397,1.);
#1399=CARTESIAN_POINT('',(20.9,-4.44041850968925,19.8494));
#1400=LINE('',#1399,#1398);
#1401=EDGE_CURVE('P1_E856',#1395,#271,#1400,.T.);
#1402=ORIENTED_EDGE('',*,*,#272,.F.);
#1403=ORIENTED_EDGE('',*,*,#1388,.F.);
#1404=ORIENTED_EDGE('',*,*,#1396,.T.);
#1405=ORIENTED_EDGE('',*,*,#1401,.T.);
#1406=EDGE_LOOP('',(#1402,#1403,#1404,#1405));
#1407=FACE_BOUND('',#1406,.T.);
#1408=ADVANCED_FACE('P1_F1208',(#1407),#1381,.T.);
#1409=CARTESIAN_POINT('',(20.9,-4.44041850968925,19.8494));
#1410=DIRECTION('',(0.,1.,0.));
#1411=DIRECTION('',(1.,0.,0.));
#1412=AXIS2_PLACEMENT_3D('',#1409,#1410,#1411);
#1413=PLANE('',#1412);
#1414=ORIENTED_EDGE('',*,*,#280,.F.);
#1415=ORIENTED_EDGE('',*,*,#1401,.F.);
#1416=DIRECTION('',(0.,0.,1.));
#1417=VECTOR('',#1416,1.);
#1418=CARTESIAN_POINT('',(20.9,-4.44041850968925,19.8494));
#1419=LINE('',#1418,#1417);
#1420=CARTESIAN_POINT('',(20.9,-4.44041850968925,20.));
#1421=VERTEX_POINT('',#1420);
#1422=EDGE_CURVE('P1_E755',#1395,#1421,#1419,.T.);
#1423=ORIENTED_EDGE('',*,*,#1422,.T.);
#1424=DIRECTION('',(1.,0.,0.));
#1425=VECTOR('',#1424,1.);
#1426=CARTESIAN_POINT('',(20.9,-4.44041850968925,20.));
#1427=LINE('',#1426,#1425);
#1428=EDGE_CURVE('P1_E852',#1421,#279,#1427,.T.);
#1429=ORIENTED_EDGE('',*,*,#1428,.T.);
#1430=EDGE_LOOP('',(#1414,#1415,#1423,#1429));
#1431=FACE_BOUND('',#1430,.T.);
#1432=ADVANCED_FACE('P1_F1211',(#1431),#1413,.T.);
#1433=CARTESIAN_POINT('',(20.9,-4.44041850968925,20.));
#1434=DIRECTION('',(0.,0.,1.));
#1435=DIRECTION('',(1.,0.,0.));
#1436=AXIS2_PLACEMENT_3D('',#1433,#1434,#1435);
#1437=PLANE('',#1436);
#1438=ORIENTED_EDGE('',*,*,#288,.F.);
#1439=ORIENTED_EDGE('',*,*,#1428,.F.);
#1440=DIRECTION('',(0.,-1.,0.));
#1441=VECTOR('',#1440,1.);
#1442=CARTESIAN_POINT('',(20.9,-4.44041850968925,20.));
#1443=LINE('',#1442,#1441);
#1444=CARTESIAN_POINT('',(20.9,-4.96361850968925,20.));
#1445=VERTEX_POINT('',#1444);
#1446=EDGE_CURVE('P1_E753',#1421,#1445,#1443,.T.);
#1447=ORIENTED_EDGE('',*,*,#1446,.T.);
#1448=DIRECTION('',(1.,0.,0.));
#1449=VECTOR('',#1448,1.);
#1450=CARTESIAN_POINT('',(20.9,-4.96361850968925,20.));
#1451=LINE('',#1450,#1449);
#1452=EDGE_CURVE('P1_E809',#1445,#287,#1451,.T.);
#1453=ORIENTED_EDGE('',*,*,#1452,.T.);
#1454=EDGE_LOOP('',(#1438,#1439,#1447,#1453));
#1455=FACE_BOUND('',#1454,.T.);
#1456=ADVANCED_FACE('P1_F3192',(#1455),#1437,.T.);
#1457=CARTESIAN_POINT('',(20.9,-4.96361850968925,20.));
#1458=DIRECTION('',(0.,-1.,0.));
#1459=DIRECTION('',(0.,0.,-1.));
#1460=AXIS2_PLACEMENT_3D('',#1457,#1458,#1459);
#1461=PLANE('',#1460);
#1462=ORIENTED_EDGE('',*,*,#296,.F.);
#1463=ORIENTED_EDGE('',*,*,#1452,.F.);
#1464=DIRECTION('',(0.,0.,-1.));
#1465=VECTOR('',#1464,1.);
#1466=CARTESIAN_POINT('',(20.9,-4.96361850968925,20.));
#1467=LINE('',#1466,#1465);
#1468=CARTESIAN_POINT('',(20.9,-4.96361850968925,19.8307));
#1469=VERTEX_POINT('',#1468);
#1470=EDGE_CURVE('P1_E741',#1445,#1469,#1467,.T.);
#1471=ORIENTED_EDGE('',*,*,#1470,.T.);
#1472=DIRECTION('',(1.,0.,0.));
#1473=VECTOR('',#1472,1.);
#1474=CARTESIAN_POINT('',(20.9,-4.96361850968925,19.8307));
#1475=LINE('',#1474,#1473);
#1476=EDGE_CURVE('P1_E835',#1469,#295,#1475,.T.);
#1477=ORIENTED_EDGE('',*,*,#1476,.T.);
#1478=EDGE_LOOP('',(#1462,#1463,#1471,#1477));
#1479=FACE_BOUND('',#1478,.T.);
#1480=ADVANCED_FACE('P1_F3171',(#1479),#1461,.T.);
#1481=CARTESIAN_POINT('',(20.9,-4.96361850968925,19.8307));
#1482=CARTESIAN_POINT('',(21.,-4.96361850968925,19.8307));
#1483=CARTESIAN_POINT('',(20.9,-4.96361850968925,19.2067));
#1484=CARTESIAN_POINT('',(21.,-4.96361850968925,19.2067));
#1485=CARTESIAN_POINT('',(20.9,-4.45321850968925,18.6962));
#1486=CARTESIAN_POINT('',(21.,-4.45321850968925,18.6962));
#1487=CARTESIAN_POINT('',(20.9,-3.82921850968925,18.6962));
#1488=CARTESIAN_POINT('',(21.,-3.82921850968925,18.6962));
#1489=(BOUNDED_SURFACE() B_SPLINE_SURFACE(3,1,((#1481,#1482),(#1483,#1484),(#1485,#1486),(#1487,
#1488)),.UNSPECIFIED.,.F.,.F.,.F.) B_SPLINE_SURFACE_WITH_KNOTS((4,4),(2,2),(0.75,0.8125),(0.,
1.),.UNSPECIFIED.) GEOMETRIC_REPRESENTATION_ITEM() RATIONAL_B_SPLINE_SURFACE(((1.,1.),(1.,1.),
(1.,1.),(1.,1.))) REPRESENTATION_ITEM('') SURFACE());
#1490=CARTESIAN_POINT('',(20.9,-4.96361850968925,19.8307));
#1491=CARTESIAN_POINT('',(20.9,-4.96361850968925,19.2067));
#1492=CARTESIAN_POINT('',(20.9,-4.45321850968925,18.6962));
#1493=CARTESIAN_POINT('',(20.9,-3.82921850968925,18.6962));
#1494=(BOUNDED_CURVE() B_SPLINE_CURVE(3,(#1490,#1491,#1492,#1493),.UNSPECIFIED.,.F.,
.F.) B_SPLINE_CURVE_WITH_KNOTS((4,4),(0.75,0.8125),
.UNSPECIFIED.) CURVE() GEOMETRIC_REPRESENTATION_ITEM() RATIONAL_B_SPLINE_CURVE((1.,1.,1.,1.)) REPRESENTATION_ITEM(''));
#1495=CARTESIAN_POINT('',(20.9,-3.82921850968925,18.6962));
#1496=VERTEX_POINT('',#1495);
#1497=EDGE_CURVE('P1_E744',#1469,#1496,#1494,.T.);
#1498=DIRECTION('',(1.,0.,0.));
#1499=VECTOR('',#1498,1.);
#1500=CARTESIAN_POINT('',(20.9,-3.82921850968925,18.6962));
#1501=LINE('',#1500,#1499);
#1502=EDGE_CURVE('P1_E822',#1496,#304,#1501,.T.);
#1503=ORIENTED_EDGE('',*,*,#305,.F.);
#1504=ORIENTED_EDGE('',*,*,#1476,.F.);
#1505=ORIENTED_EDGE('',*,*,#1497,.T.);
#1506=ORIENTED_EDGE('',*,*,#1502,.T.);
#1507=EDGE_LOOP('',(#1503,#1504,#1505,#1506));
#1508=FACE_BOUND('',#1507,.T.);
#1509=ADVANCED_FACE('P1_F3161',(#1508),#1489,.T.);
#1510=CARTESIAN_POINT('',(20.9,-3.82921850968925,18.6962));
#1511=CARTESIAN_POINT('',(21.,-3.82921850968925,18.6962));
#1512=CARTESIAN_POINT('',(20.9,-3.20521850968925,18.6962));
#1513=CARTESIAN_POINT('',(21.,-3.20521850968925,18.6962));
#1514=CARTESIAN_POINT('',(20.9,-2.69471850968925,19.2067));
#1515=CARTESIAN_POINT('',(21.,-2.69471850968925,19.2067));
#1516=CARTESIAN_POINT('',(20.9,-2.69471850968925,19.8307));
#1517=CARTESIAN_POINT('',(21.,-2.69471850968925,19.8307));
#1518=(BOUNDED_SURFACE() B_SPLINE_SURFACE(3,1,((#1510,#1511),(#1512,#1513),(#1514,#1515),(#1516,
#1517)),.UNSPECIFIED.,.F.,.F.,.F.) B_SPLINE_SURFACE_WITH_KNOTS((4,4),(2,2),(0.875,0.9375),(0.,
1.),.UNSPECIFIED.) GEOMETRIC_REPRESENTATION_ITEM() RATIONAL_B_SPLINE_SURFACE(((1.,1.),(1.,1.),
(1.,1.),(1.,1.))) REPRESENTATION_ITEM('') SURFACE());
#1519=CARTESIAN_POINT('',(20.9,-3.82921850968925,18.6962));
#1520=CARTESIAN_POINT('',(20.9,-3.20521850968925,18.6962));
#1521=CARTESIAN_POINT('',(20.9,-2.69471850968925,19.2067));
#1522=CARTESIAN_POINT('',(20.9,-2.69471850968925,19.8307));
#1523=(BOUNDED_CURVE() B_SPLINE_CURVE(3,(#1519,#1520,#1521,#1522),.UNSPECIFIED.,.F.,
.F.) B_SPLINE_CURVE_WITH_KNOTS((4,4),(0.875,0.9375),
.UNSPECIFIED.) CURVE() GEOMETRIC_REPRESENTATION_ITEM() RATIONAL_B_SPLINE_CURVE((1.,1.,1.,1.)) REPRESENTATION_ITEM(''));
#1524=CARTESIAN_POINT('',(20.9,-2.69471850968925,19.8307));
#1525=VERTEX_POINT('',#1524);
#1526=EDGE_CURVE('P1_E740',#1496,#1525,#1523,.T.);
#1527=DIRECTION('',(1.,0.,0.));
#1528=VECTOR('',#1527,1.);
#1529=CARTESIAN_POINT('',(20.9,-2.69471850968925,19.8307));
#1530=LINE('',#1529,#1528);
#1531=EDGE_CURVE('P1_E806',#1525,#313,#1530,.T.);
#1532=ORIENTED_EDGE('',*,*,#314,.F.);
#1533=ORIENTED_EDGE('',*,*,#1502,.F.);
#1534=ORIENTED_EDGE('',*,*,#1526,.T.);
#1535=ORIENTED_EDGE('',*,*,#1531,.T.);
#1536=EDGE_LOOP('',(#1532,#1533,#1534,#1535));
#1537=FACE_BOUND('',#1536,.T.);
#1538=ADVANCED_FACE('P1_F3154',(#1537),#1518,.T.);
#1539=CARTESIAN_POINT('',(20.9,-2.69471850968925,19.8307));
#1540=DIRECTION('',(0.,1.,0.));
#1541=DIRECTION('',(1.,0.,0.));
#1542=AXIS2_PLACEMENT_3D('',#1539,#1540,#1541);
#1543=PLANE('',#1542);
#1544=ORIENTED_EDGE('',*,*,#322,.F.);
#1545=ORIENTED_EDGE('',*,*,#1531,.F.);
#1546=DIRECTION('',(0.,0.,1.));
#1547=VECTOR('',#1546,1.);
#1548=CARTESIAN_POINT('',(20.9,-2.69471850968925,19.8307));
#1549=LINE('',#1548,#1547);
#1550=CARTESIAN_POINT('',(20.9,-2.69471850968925,21.0456));
#1551=VERTEX_POINT('',#1550);
#1552=EDGE_CURVE('P1_E733',#1525,#1551,#1549,.T.);
#1553=ORIENTED_EDGE('',*,*,#1552,.T.);
#1554=DIRECTION('',(1.,0.,0.));
#1555=VECTOR('',#1554,1.);
#1556=CARTESIAN_POINT('',(20.9,-2.69471850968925,21.0456));
#1557=LINE('',#1556,#1555);
#1558=EDGE_CURVE('P1_E803',#1551,#321,#1557,.T.);
#1559=ORIENTED_EDGE('',*,*,#1558,.T.);
#1560=EDGE_LOOP('',(#1544,#1545,#1553,#1559));
#1561=FACE_BOUND('',#1560,.T.);
#1562=ADVANCED_FACE('P1_F1233',(#1561),#1543,.T.);
#1563=CARTESIAN_POINT('',(20.9,-2.69471850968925,21.0456));
#1564=DIRECTION('',(0.,0.,1.));
#1565=DIRECTION('',(1.,0.,0.));
#1566=AXIS2_PLACEMENT_3D('',#1563,#1564,#1565);
#1567=PLANE('',#1566);
#1568=ORIENTED_EDGE('',*,*,#330,.F.);
#1569=ORIENTED_EDGE('',*,*,#1558,.F.);
#1570=DIRECTION('',(0.,-1.,0.));
#1571=VECTOR('',#1570,1.);
#1572=CARTESIAN_POINT('',(20.9,-2.69471850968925,21.0456));
#1573=LINE('',#1572,#1571);
#1574=CARTESIAN_POINT('',(20.9,-4.96361850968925,21.0456));
#1575=VERTEX_POINT('',#1574);
#1576=EDGE_CURVE('P1_E727',#1551,#1575,#1573,.T.);
#1577=ORIENTED_EDGE('',*,*,#1576,.T.);
#1578=DIRECTION('',(1.,0.,0.));
#1579=VECTOR('',#1578,1.);
#1580=CARTESIAN_POINT('',(20.9,-4.96361850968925,21.0456));
#1581=LINE('',#1580,#1579);
#1582=EDGE_CURVE('P1_E793',#1575,#329,#1581,.T.);
#1583=ORIENTED_EDGE('',*,*,#1582,.T.);
#1584=EDGE_LOOP('',(#1568,#1569,#1577,#1583));
#1585=FACE_BOUND('',#1584,.T.);
#1586=ADVANCED_FACE('P1_F1229',(#1585),#1567,.T.);
#1587=CARTESIAN_POINT('',(20.9,-4.96361850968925,21.0456));
#1588=DIRECTION('',(0.,-1.,0.));
#1589=DIRECTION('',(0.,0.,-1.));
#1590=AXIS2_PLACEMENT_3D('',#1587,#1588,#1589);
#1591=PLANE('',#1590);
#1592=ORIENTED_EDGE('',*,*,#338,.F.);
#1593=ORIENTED_EDGE('',*,*,#1582,.F.);
#1594=DIRECTION('',(0.,0.,-1.));
#1595=VECTOR('',#1594,1.);
#1596=CARTESIAN_POINT('',(20.9,-4.96361850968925,21.0456));
#1597=LINE('',#1596,#1595);
#1598=CARTESIAN_POINT('',(20.9,-4.96361850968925,20.5036));
#1599=VERTEX_POINT('',#1598);
#1600=EDGE_CURVE('P1_E706',#1575,#1599,#1597,.T.);
#1601=ORIENTED_EDGE('',*,*,#1600,.T.);
#1602=DIRECTION('',(1.,0.,0.));
#1603=VECTOR('',#1602,1.);
#1604=CARTESIAN_POINT('',(20.9,-4.96361850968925,20.5036));
#1605=LINE('',#1604,#1603);
#1606=EDGE_CURVE('P1_E701',#1599,#337,#1605,.T.);
#1607=ORIENTED_EDGE('',*,*,#1606,.T.);
#1608=EDGE_LOOP('',(#1592,#1593,#1601,#1607));
#1609=FACE_BOUND('',#1608,.T.);
#1610=ADVANCED_FACE('P1_F1232',(#1609),#1591,.T.);
#1611=CARTESIAN_POINT('',(20.9,-4.05351850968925,20.5036));
#1612=DIRECTION('',(0.,0.,-1.));
#1613=DIRECTION('',(0.,-1.,0.));
#1614=AXIS2_PLACEMENT_3D('',#1611,#1612,#1613);
#1615=PLANE('',#1614);
#1616=ORIENTED_EDGE('',*,*,#346,.F.);
#1617=ORIENTED_EDGE('',*,*,#1606,.F.);
#1618=DIRECTION('',(0.,1.,0.));
#1619=VECTOR('',#1618,1.);
#1620=CARTESIAN_POINT('',(20.9,-4.96361850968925,20.5036));
#1621=LINE('',#1620,#1619);
#1622=CARTESIAN_POINT('',(20.9,-3.21791850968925,20.5036));
#1623=VERTEX_POINT('',#1622);
#1624=EDGE_CURVE('P1_E696',#1599,#1623,#1621,.T.);
#1625=ORIENTED_EDGE('',*,*,#1624,.T.);
#1626=DIRECTION('',(1.,0.,0.));
#1627=VECTOR('',#1626,1.);
#1628=CARTESIAN_POINT('',(20.9,-3.21791850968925,20.5036));
#1629=LINE('',#1628,#1627);
#1630=EDGE_CURVE('P1_E684',#1623,#345,#1629,.T.);
#1631=ORIENTED_EDGE('',*,*,#1630,.T.);
#1632=EDGE_LOOP('',(#1616,#1617,#1625,#1631));
#1633=FACE_BOUND('',#1632,.T.);
#1634=ADVANCED_FACE('P1_F699',(#1633),#1615,.T.);
#1635=CARTESIAN_POINT('',(20.9,-3.21791850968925,20.5036));
#1636=DIRECTION('',(0.,-1.,0.));
#1637=DIRECTION('',(0.,0.,-1.));
#1638=AXIS2_PLACEMENT_3D('',#1635,#1636,#1637);
#1639=PLANE('',#1638);
#1640=ORIENTED_EDGE('',*,*,#352,.F.);
#1641=ORIENTED_EDGE('',*,*,#1630,.F.);
#1642=DIRECTION('',(0.,0.,-1.));
#1643=VECTOR('',#1642,1.);
#1644=CARTESIAN_POINT('',(20.9,-3.21791850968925,20.5036));
#1645=LINE('',#1644,#1643);
#1646=CARTESIAN_POINT('',(20.9,-3.21791850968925,19.8494));
#1647=VERTEX_POINT('',#1646);
#1648=EDGE_CURVE('P1_E688',#1623,#1647,#1645,.T.);
#1649=ORIENTED_EDGE('',*,*,#1648,.T.);
#1650=DIRECTION('',(1.,0.,0.));
#1651=VECTOR('',#1650,1.);
#1652=CARTESIAN_POINT('',(20.9,-3.21791850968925,19.8494));
#1653=LINE('',#1652,#1651);
#1654=EDGE_CURVE('P1_E779',#1647,#260,#1653,.T.);
#1655=ORIENTED_EDGE('',*,*,#1654,.T.);
#1656=EDGE_LOOP('',(#1640,#1641,#1649,#1655));
#1657=FACE_BOUND('',#1656,.T.);
#1658=ADVANCED_FACE('P1_F690',(#1657),#1639,.T.);
#1659=CARTESIAN_POINT('',(20.9,-3.21791850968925,19.8494));
#1660=CARTESIAN_POINT('',(21.,-3.21791850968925,19.8494));
#1661=CARTESIAN_POINT('',(20.9,-3.21791850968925,19.5131));
#1662=CARTESIAN_POINT('',(21.,-3.21791850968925,19.5131));
#1663=CARTESIAN_POINT('',(20.9,-3.49311850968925,19.2382));
#1664=CARTESIAN_POINT('',(21.,-3.49311850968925,19.2382));
#1665=CARTESIAN_POINT('',(20.9,-3.82921850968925,19.2382));
#1666=CARTESIAN_POINT('',(21.,-3.82921850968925,19.2382));
#1667=(BOUNDED_SURFACE() B_SPLINE_SURFACE(3,1,((#1659,#1660),(#1661,#1662),(#1663,#1664),(#1665,
#1666)),.UNSPECIFIED.,.F.,.F.,.F.) B_SPLINE_SURFACE_WITH_KNOTS((4,4),(2,2),(0.4375,0.5),(0.,1.),
.UNSPECIFIED.) GEOMETRIC_REPRESENTATION_ITEM() RATIONAL_B_SPLINE_SURFACE(((1.,1.),(1.,1.),(1.,
1.),(1.,1.))) REPRESENTATION_ITEM('') SURFACE());
#1668=CARTESIAN_POINT('',(20.9,-3.21791850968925,19.8494));
#1669=CARTESIAN_POINT('',(20.9,-3.21791850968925,19.5131));
#1670=CARTESIAN_POINT('',(20.9,-3.49311850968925,19.2382));
#1671=CARTESIAN_POINT('',(20.9,-3.82921850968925,19.2382));
#1672=(BOUNDED_CURVE() B_SPLINE_CURVE(3,(#1668,#1669,#1670,#1671),.UNSPECIFIED.,.F.,
.F.) B_SPLINE_CURVE_WITH_KNOTS((4,4),(0.4375,0.5),
.UNSPECIFIED.) CURVE() GEOMETRIC_REPRESENTATION_ITEM() RATIONAL_B_SPLINE_CURVE((1.,1.,1.,1.)) REPRESENTATION_ITEM(''));
#1673=EDGE_CURVE('P1_E712',#1647,#1387,#1672,.T.);
#1674=ORIENTED_EDGE('',*,*,#263,.F.);
#1675=ORIENTED_EDGE('',*,*,#1654,.F.);
#1676=ORIENTED_EDGE('',*,*,#1673,.T.);
#1677=ORIENTED_EDGE('',*,*,#1388,.T.);
#1678=EDGE_LOOP('',(#1674,#1675,#1676,#1677));
#1679=FACE_BOUND('',#1678,.T.);
#1680=ADVANCED_FACE('P1_F3113',(#1679),#1667,.T.);
#1681=CARTESIAN_POINT('',(20.9,5.73659399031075,14.2697125));
#1682=DIRECTION('',(1.,0.,0.));
#1683=DIRECTION('',(0.,1.,0.));
#1684=AXIS2_PLACEMENT_3D('',#1681,#1682,#1683);
#1685=PLANE('',#1684);
#1686=ORIENTED_EDGE('',*,*,#1648,.F.);
#1687=ORIENTED_EDGE('',*,*,#1624,.F.);
#1688=ORIENTED_EDGE('',*,*,#1600,.F.);
#1689=ORIENTED_EDGE('',*,*,#1576,.F.);
#1690=ORIENTED_EDGE('',*,*,#1552,.F.);
#1691=ORIENTED_EDGE('',*,*,#1526,.F.);
#1692=ORIENTED_EDGE('',*,*,#1497,.F.);
#1693=ORIENTED_EDGE('',*,*,#1470,.F.);
#1694=ORIENTED_EDGE('',*,*,#1446,.F.);
#1695=ORIENTED_EDGE('',*,*,#1422,.F.);
#1696=ORIENTED_EDGE('',*,*,#1396,.F.);
#1697=ORIENTED_EDGE('',*,*,#1673,.F.);
#1698=EDGE_LOOP('',(#1686,#1687,#1688,#1689,#1690,#1691,#1692,#1693,#1694,#1695,#1696,#1697));
#1699=FACE_BOUND('',#1698,.T.);
#1700=ORIENTED_EDGE('',*,*,#1340,.F.);
#1701=ORIENTED_EDGE('',*,*,#1316,.F.);
#1702=ORIENTED_EDGE('',*,*,#1290,.F.);
#1703=ORIENTED_EDGE('',*,*,#1263,.F.);
#1704=ORIENTED_EDGE('',*,*,#1237,.F.);
#1705=ORIENTED_EDGE('',*,*,#1210,.F.);
#1706=ORIENTED_EDGE('',*,*,#1184,.F.);
#1707=ORIENTED_EDGE('',*,*,#1157,.F.);
#1708=ORIENTED_EDGE('',*,*,#1131,.F.);
#1709=ORIENTED_EDGE('',*,*,#1104,.F.);
#1710=ORIENTED_EDGE('',*,*,#1080,.F.);
#1711=ORIENTED_EDGE('',*,*,#1054,.F.);
#1712=ORIENTED_EDGE('',*,*,#1025,.F.);
#1713=ORIENTED_EDGE('',*,*,#996,.F.);
#1714=ORIENTED_EDGE('',*,*,#1365,.F.);
#1715=EDGE_LOOP('',(#1700,#1701,#1702,#1703,#1704,#1705,#1706,#1707,#1708,#1709,#1710,#1711,
#1712,#1713,#1714));
#1716=FACE_BOUND('',#1715,.T.);
#1717=ORIENTED_EDGE('',*,*,#945,.F.);
#1718=ORIENTED_EDGE('',*,*,#921,.F.);
#1719=ORIENTED_EDGE('',*,*,#897,.F.);
#1720=ORIENTED_EDGE('',*,*,#873,.F.);
#1721=ORIENTED_EDGE('',*,*,#849,.F.);
#1722=ORIENTED_EDGE('',*,*,#825,.F.);
#1723=ORIENTED_EDGE('',*,*,#801,.F.);
#1724=ORIENTED_EDGE('',*,*,#967,.F.);
#1725=EDGE_LOOP('',(#1717,#1718,#1719,#1720,#1721,#1722,#1723,#1724));
#1726=FACE_BOUND('',#1725,.T.);
#1727=ORIENTED_EDGE('',*,*,#753,.F.);
#1728=ORIENTED_EDGE('',*,*,#729,.F.);
#1729=ORIENTED_EDGE('',*,*,#705,.F.);
#1730=ORIENTED_EDGE('',*,*,#681,.F.);
#1731=ORIENTED_EDGE('',*,*,#657,.F.);
#1732=ORIENTED_EDGE('',*,*,#633,.F.);
#1733=ORIENTED_EDGE('',*,*,#609,.F.);
#1734=ORIENTED_EDGE('',*,*,#585,.F.);
#1735=ORIENTED_EDGE('',*,*,#775,.F.);
#1736=EDGE_LOOP('',(#1727,#1728,#1729,#1730,#1731,#1732,#1733,#1734,#1735));
#1737=FACE_BOUND('',#1736,.T.);
#1738=CARTESIAN_POINT('',(20.9,5.05098149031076,13.9846));
#1739=CARTESIAN_POINT('',(20.9,5.58488149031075,13.9846));
#1740=CARTESIAN_POINT('',(20.9,6.02178149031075,14.4214));
#1741=CARTESIAN_POINT('',(20.9,6.02178149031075,14.9551));
#1742=(BOUNDED_CURVE() B_SPLINE_CURVE(3,(#1738,#1739,#1740,#1741),.UNSPECIFIED.,.F.,
.F.) B_SPLINE_CURVE_WITH_KNOTS((4,4),(0.125,0.25),
.UNSPECIFIED.) CURVE() GEOMETRIC_REPRESENTATION_ITEM() RATIONAL_B_SPLINE_CURVE((1.,1.,1.,1.)) REPRESENTATION_ITEM(''));
#1743=CARTESIAN_POINT('',(20.9,5.05098149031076,13.9846));
#1744=VERTEX_POINT('',#1743);
#1745=CARTESIAN_POINT('',(20.9,6.02178149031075,14.9551));
#1746=VERTEX_POINT('',#1745);
#1747=EDGE_CURVE('P1_E1577',#1744,#1746,#1742,.T.);
#1748=ORIENTED_EDGE('',*,*,#1747,.T.);
#1749=DIRECTION('',(0.,0.,1.));
#1750=VECTOR('',#1749,1.);
#1751=CARTESIAN_POINT('',(20.9,6.02178149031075,25.0195));
#1752=LINE('',#1751,#1750);
#1753=CARTESIAN_POINT('',(20.9,6.02178149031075,25.0195));
#1754=VERTEX_POINT('',#1753);
#1755=EDGE_CURVE('P1_E1574',#1746,#1754,#1752,.T.);
#1756=ORIENTED_EDGE('',*,*,#1755,.T.);
#1757=CARTESIAN_POINT('',(20.9,6.02178149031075,25.0195));
#1758=CARTESIAN_POINT('',(20.9,6.02178149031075,25.5532));
#1759=CARTESIAN_POINT('',(20.9,5.58488149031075,25.9903));
#1760=CARTESIAN_POINT('',(20.9,5.05098149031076,25.9903));
#1761=(BOUNDED_CURVE() B_SPLINE_CURVE(3,(#1757,#1758,#1759,#1760),.UNSPECIFIED.,.F.,
.F.) B_SPLINE_CURVE_WITH_KNOTS((4,4),(0.875,1.),
.UNSPECIFIED.) CURVE() GEOMETRIC_REPRESENTATION_ITEM() RATIONAL_B_SPLINE_CURVE((1.,1.,1.,1.)) REPRESENTATION_ITEM(''));
#1762=CARTESIAN_POINT('',(20.9,5.05098149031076,25.9903));
#1763=VERTEX_POINT('',#1762);
#1764=EDGE_CURVE('P1_E1413',#1754,#1763,#1761,.T.);
#1765=ORIENTED_EDGE('',*,*,#1764,.T.);
#1766=DIRECTION('',(0.,-1.,0.));
#1767=VECTOR('',#1766,1.);
#1768=CARTESIAN_POINT('',(20.9,-5.01321850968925,25.9903));
#1769=LINE('',#1768,#1767);
#1770=CARTESIAN_POINT('',(20.9,-5.01321850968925,25.9903));
#1771=VERTEX_POINT('',#1770);
#1772=EDGE_CURVE('P1_E1415',#1763,#1771,#1769,.T.);
#1773=ORIENTED_EDGE('',*,*,#1772,.T.);
#1774=CARTESIAN_POINT('',(20.9,-5.01321850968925,25.9903));
#1775=CARTESIAN_POINT('',(20.9,-5.54711850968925,25.9903));
#1776=CARTESIAN_POINT('',(20.9,-5.98391850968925,25.5532));
#1777=CARTESIAN_POINT('',(20.9,-5.98391850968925,25.0195));
#1778=(BOUNDED_CURVE() B_SPLINE_CURVE(3,(#1774,#1775,#1776,#1777),.UNSPECIFIED.,.F.,
.F.) B_SPLINE_CURVE_WITH_KNOTS((4,4),(0.625,0.75),
.UNSPECIFIED.) CURVE() GEOMETRIC_REPRESENTATION_ITEM() RATIONAL_B_SPLINE_CURVE((1.,1.,1.,1.)) REPRESENTATION_ITEM(''));
#1779=CARTESIAN_POINT('',(20.9,-5.98391850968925,25.0195));
#1780=VERTEX_POINT('',#1779);
#1781=EDGE_CURVE('P1_E1537',#1771,#1780,#1778,.T.);
#1782=ORIENTED_EDGE('',*,*,#1781,.T.);
#1783=DIRECTION('',(0.,0.,-1.));
#1784=VECTOR('',#1783,1.);
#1785=CARTESIAN_POINT('',(20.9,-5.98391850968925,14.9551));
#1786=LINE('',#1785,#1784);
#1787=CARTESIAN_POINT('',(20.9,-5.98391850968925,14.9551));
#1788=VERTEX_POINT('',#1787);
#1789=EDGE_CURVE('P1_E1538',#1780,#1788,#1786,.T.);
#1790=ORIENTED_EDGE('',*,*,#1789,.T.);
#1791=CARTESIAN_POINT('',(20.9,-5.98391850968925,14.9551));
#1792=CARTESIAN_POINT('',(20.9,-5.98391850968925,14.4214));
#1793=CARTESIAN_POINT('',(20.9,-5.54711850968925,13.9846));
#1794=CARTESIAN_POINT('',(20.9,-5.01321850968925,13.9846));
#1795=(BOUNDED_CURVE() B_SPLINE_CURVE(3,(#1791,#1792,#1793,#1794),.UNSPECIFIED.,.F.,
.F.) B_SPLINE_CURVE_WITH_KNOTS((4,4),(0.375,0.5),
.UNSPECIFIED.) CURVE() GEOMETRIC_REPRESENTATION_ITEM() RATIONAL_B_SPLINE_CURVE((1.,1.,1.,1.)) REPRESENTATION_ITEM(''));
#1796=CARTESIAN_POINT('',(20.9,-5.01321850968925,13.9846));
#1797=VERTEX_POINT('',#1796);
#1798=EDGE_CURVE('P1_E1479',#1788,#1797,#1795,.T.);
#1799=ORIENTED_EDGE('',*,*,#1798,.T.);
#1800=DIRECTION('',(0.,1.,0.));
#1801=VECTOR('',#1800,1.);
#1802=CARTESIAN_POINT('',(20.9,5.05098149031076,13.9846));
#1803=LINE('',#1802,#1801);
#1804=EDGE_CURVE('P1_E1481',#1797,#1744,#1803,.T.);
#1805=ORIENTED_EDGE('',*,*,#1804,.T.);
#1806=EDGE_LOOP('',(#1748,#1756,#1765,#1773,#1782,#1790,#1799,#1805));
#1807=FACE_BOUND('',#1806,.T.);
#1808=ADVANCED_FACE('P1_F707',(#1699,#1716,#1726,#1737,#1807),#1685,.T.);
#1809=CARTESIAN_POINT('',(20.9,6.02178149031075,25.0195));
#1810=DIRECTION('',(0.,1.,0.));
#1811=DIRECTION('',(1.,0.,0.));
#1812=AXIS2_PLACEMENT_3D('',#1809,#1810,#1811);
#1813=PLANE('',#1812);
#1814=DIRECTION('',(0.,0.,1.));
#1815=VECTOR('',#1814,1.);
#1816=CARTESIAN_POINT('',(21.,6.02178149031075,25.0195));
#1817=LINE('',#1816,#1815);
#1818=CARTESIAN_POINT('',(21.,6.02178149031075,14.9551));
#1819=VERTEX_POINT('',#1818);
#1820=CARTESIAN_POINT('',(21.,6.02178149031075,25.0195));
#1821=VERTEX_POINT('',#1820);
#1822=EDGE_CURVE('P1_E1439',#1819,#1821,#1817,.T.);
#1823=ORIENTED_EDGE('',*,*,#1822,.T.);
#1824=DIRECTION('',(1.,0.,0.));
#1825=VECTOR('',#1824,1.);
#1826=CARTESIAN_POINT('',(20.9,6.02178149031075,25.0195));
#1827=LINE('',#1826,#1825);
#1828=EDGE_CURVE('P1_E1572',#1754,#1821,#1827,.T.);
#1829=ORIENTED_EDGE('',*,*,#1828,.F.);
#1830=ORIENTED_EDGE('',*,*,#1755,.F.);
#1831=DIRECTION('',(1.,0.,0.));
#1832=VECTOR('',#1831,1.);
#1833=CARTESIAN_POINT('',(20.9,6.02178149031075,14.9551));
#1834=LINE('',#1833,#1832);
#1835=EDGE_CURVE('P1_E1524',#1746,#1819,#1834,.T.);
#1836=ORIENTED_EDGE('',*,*,#1835,.T.);
#1837=EDGE_LOOP('',(#1823,#1829,#1830,#1836));
#1838=FACE_BOUND('',#1837,.T.);
#1839=ADVANCED_FACE('P1_F2013',(#1838),#1813,.F.);
#1840=CARTESIAN_POINT('',(20.9,6.02178149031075,25.0195));
#1841=CARTESIAN_POINT('',(21.,6.02178149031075,25.0195));
#1842=CARTESIAN_POINT('',(20.9,6.02178149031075,25.5532));
#1843=CARTESIAN_POINT('',(21.,6.02178149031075,25.5532));
#1844=CARTESIAN_POINT('',(20.9,5.58488149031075,25.9903));
#1845=CARTESIAN_POINT('',(21.,5.58488149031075,25.9903));
#1846=CARTESIAN_POINT('',(20.9,5.05098149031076,25.9903));
#1847=CARTESIAN_POINT('',(21.,5.05098149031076,25.9903));
#1848=(BOUNDED_SURFACE() B_SPLINE_SURFACE(3,1,((#1840,#1841),(#1842,#1843),(#1844,#1845),(#1846,
#1847)),.UNSPECIFIED.,.F.,.F.,.F.) B_SPLINE_SURFACE_WITH_KNOTS((4,4),(2,2),(0.875,1.),(0.,1.),
.UNSPECIFIED.) GEOMETRIC_REPRESENTATION_ITEM() RATIONAL_B_SPLINE_SURFACE(((1.,1.),(1.,1.),(1.,
1.),(1.,1.))) REPRESENTATION_ITEM('') SURFACE());
#1849=CARTESIAN_POINT('',(21.,6.02178149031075,25.0195));
#1850=CARTESIAN_POINT('',(21.,6.02178149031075,25.5532));
#1851=CARTESIAN_POINT('',(21.,5.58488149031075,25.9903));
#1852=CARTESIAN_POINT('',(21.,5.05098149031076,25.9903));
#1853=(BOUNDED_CURVE() B_SPLINE_CURVE(3,(#1849,#1850,#1851,#1852),.UNSPECIFIED.,.F.,
.F.) B_SPLINE_CURVE_WITH_KNOTS((4,4),(0.875,1.),
.UNSPECIFIED.) CURVE() GEOMETRIC_REPRESENTATION_ITEM() RATIONAL_B_SPLINE_CURVE((1.,1.,1.,1.)) REPRESENTATION_ITEM(''));
#1854=CARTESIAN_POINT('',(21.,5.05098149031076,25.9903));
#1855=VERTEX_POINT('',#1854);
#1856=EDGE_CURVE('P1_E1487',#1821,#1855,#1853,.T.);
#1857=DIRECTION('',(1.,0.,0.));
#1858=VECTOR('',#1857,1.);
#1859=CARTESIAN_POINT('',(20.9,5.05098149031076,25.9903));
#1860=LINE('',#1859,#1858);
#1861=EDGE_CURVE('P1_E1406',#1763,#1855,#1860,.T.);
#1862=ORIENTED_EDGE('',*,*,#1856,.T.);
#1863=ORIENTED_EDGE('',*,*,#1861,.F.);
#1864=ORIENTED_EDGE('',*,*,#1764,.F.);
#1865=ORIENTED_EDGE('',*,*,#1828,.T.);
#1866=EDGE_LOOP('',(#1862,#1863,#1864,#1865));
#1867=FACE_BOUND('',#1866,.T.);
#1868=ADVANCED_FACE('P1_F2009',(#1867),#1848,.F.);
#1869=CARTESIAN_POINT('',(20.9,-5.01321850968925,25.9903));
#1870=DIRECTION('',(0.,0.,1.));
#1871=DIRECTION('',(1.,0.,0.));
#1872=AXIS2_PLACEMENT_3D('',#1869,#1870,#1871);
#1873=PLANE('',#1872);
#1874=DIRECTION('',(0.,-1.,0.));
#1875=VECTOR('',#1874,1.);
#1876=CARTESIAN_POINT('',(21.,-5.01321850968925,25.9903));
#1877=LINE('',#1876,#1875);
#1878=CARTESIAN_POINT('',(21.,-5.01321850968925,25.9903));
#1879=VERTEX_POINT('',#1878);
#1880=EDGE_CURVE('P1_E1485',#1855,#1879,#1877,.T.);
#1881=ORIENTED_EDGE('',*,*,#1880,.T.);
#1882=DIRECTION('',(1.,0.,0.));
#1883=VECTOR('',#1882,1.);
#1884=CARTESIAN_POINT('',(20.9,-5.01321850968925,25.9903));
#1885=LINE('',#1884,#1883);
#1886=EDGE_CURVE('P1_E1600',#1771,#1879,#1885,.T.);
#1887=ORIENTED_EDGE('',*,*,#1886,.F.);
#1888=ORIENTED_EDGE('',*,*,#1772,.F.);
#1889=ORIENTED_EDGE('',*,*,#1861,.T.);
#1890=EDGE_LOOP('',(#1881,#1887,#1888,#1889));
#1891=FACE_BOUND('',#1890,.T.);
#1892=ADVANCED_FACE('P1_F2003',(#1891),#1873,.F.);
#1893=CARTESIAN_POINT('',(20.9,-5.01321850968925,25.9903));
#1894=CARTESIAN_POINT('',(21.,-5.01321850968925,25.9903));
#1895=CARTESIAN_POINT('',(20.9,-5.54711850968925,25.9903));
#1896=CARTESIAN_POINT('',(21.,-5.54711850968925,25.9903));
#1897=CARTESIAN_POINT('',(20.9,-5.98391850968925,25.5532));
#1898=CARTESIAN_POINT('',(21.,-5.98391850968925,25.5532));
#1899=CARTESIAN_POINT('',(20.9,-5.98391850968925,25.0195));
#1900=CARTESIAN_POINT('',(21.,-5.98391850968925,25.0195));
#1901=(BOUNDED_SURFACE() B_SPLINE_SURFACE(3,1,((#1893,#1894),(#1895,#1896),(#1897,#1898),(#1899,
#1900)),.UNSPECIFIED.,.F.,.F.,.F.) B_SPLINE_SURFACE_WITH_KNOTS((4,4),(2,2),(0.625,0.75),(0.,1.),
.UNSPECIFIED.) GEOMETRIC_REPRESENTATION_ITEM() RATIONAL_B_SPLINE_SURFACE(((1.,1.),(1.,1.),(1.,
1.),(1.,1.))) REPRESENTATION_ITEM('') SURFACE());
#1902=CARTESIAN_POINT('',(21.,-5.01321850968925,25.9903));
#1903=CARTESIAN_POINT('',(21.,-5.54711850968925,25.9903));
#1904=CARTESIAN_POINT('',(21.,-5.98391850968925,25.5532));
#1905=CARTESIAN_POINT('',(21.,-5.98391850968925,25.0195));
#1906=(BOUNDED_CURVE() B_SPLINE_CURVE(3,(#1902,#1903,#1904,#1905),.UNSPECIFIED.,.F.,
.F.) B_SPLINE_CURVE_WITH_KNOTS((4,4),(0.625,0.75),
.UNSPECIFIED.) CURVE() GEOMETRIC_REPRESENTATION_ITEM() RATIONAL_B_SPLINE_CURVE((1.,1.,1.,1.)) REPRESENTATION_ITEM(''));
#1907=CARTESIAN_POINT('',(21.,-5.98391850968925,25.0195));
#1908=VERTEX_POINT('',#1907);
#1909=EDGE_CURVE('P1_E1490',#1879,#1908,#1906,.T.);
#1910=DIRECTION('',(1.,0.,0.));
#1911=VECTOR('',#1910,1.);
#1912=CARTESIAN_POINT('',(20.9,-5.98391850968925,25.0195));
#1913=LINE('',#1912,#1911);
#1914=EDGE_CURVE('P1_E1534',#1780,#1908,#1913,.T.);
#1915=ORIENTED_EDGE('',*,*,#1909,.T.);
#1916=ORIENTED_EDGE('',*,*,#1914,.F.);
#1917=ORIENTED_EDGE('',*,*,#1781,.F.);
#1918=ORIENTED_EDGE('',*,*,#1886,.T.);
#1919=EDGE_LOOP('',(#1915,#1916,#1917,#1918));
#1920=FACE_BOUND('',#1919,.T.);
#1921=ADVANCED_FACE('P1_F1999',(#1920),#1901,.F.);
#1922=CARTESIAN_POINT('',(20.9,-5.98391850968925,14.9551));
#1923=DIRECTION('',(0.,-1.,0.));
#1924=DIRECTION('',(0.,0.,-1.));
#1925=AXIS2_PLACEMENT_3D('',#1922,#1923,#1924);
#1926=PLANE('',#1925);
#1927=DIRECTION('',(0.,0.,-1.));
#1928=VECTOR('',#1927,1.);
#1929=CARTESIAN_POINT('',(21.,-5.98391850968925,14.9551));
#1930=LINE('',#1929,#1928);
#1931=CARTESIAN_POINT('',(21.,-5.98391850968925,14.9551));
#1932=VERTEX_POINT('',#1931);
#1933=EDGE_CURVE('P1_E1364',#1908,#1932,#1930,.T.);
#1934=ORIENTED_EDGE('',*,*,#1933,.T.);
#1935=DIRECTION('',(1.,0.,0.));
#1936=VECTOR('',#1935,1.);
#1937=CARTESIAN_POINT('',(20.9,-5.98391850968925,14.9551));
#1938=LINE('',#1937,#1936);
#1939=EDGE_CURVE('P1_E1597',#1788,#1932,#1938,.T.);
#1940=ORIENTED_EDGE('',*,*,#1939,.F.);
#1941=ORIENTED_EDGE('',*,*,#1789,.F.);
#1942=ORIENTED_EDGE('',*,*,#1914,.T.);
#1943=EDGE_LOOP('',(#1934,#1940,#1941,#1942));
#1944=FACE_BOUND('',#1943,.T.);
#1945=ADVANCED_FACE('P1_F1981',(#1944),#1926,.F.);
#1946=CARTESIAN_POINT('',(20.9,-5.98391850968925,14.9551));
#1947=CARTESIAN_POINT('',(21.,-5.98391850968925,14.9551));
#1948=CARTESIAN_POINT('',(20.9,-5.98391850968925,14.4214));
#1949=CARTESIAN_POINT('',(21.,-5.98391850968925,14.4214));
#1950=CARTESIAN_POINT('',(20.9,-5.54711850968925,13.9846));
#1951=CARTESIAN_POINT('',(21.,-5.54711850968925,13.9846));
#1952=CARTESIAN_POINT('',(20.9,-5.01321850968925,13.9846));
#1953=CARTESIAN_POINT('',(21.,-5.01321850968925,13.9846));
#1954=(BOUNDED_SURFACE() B_SPLINE_SURFACE(3,1,((#1946,#1947),(#1948,#1949),(#1950,#1951),(#1952,
#1953)),.UNSPECIFIED.,.F.,.F.,.F.) B_SPLINE_SURFACE_WITH_KNOTS((4,4),(2,2),(0.375,0.5),(0.,1.),
.UNSPECIFIED.) GEOMETRIC_REPRESENTATION_ITEM() RATIONAL_B_SPLINE_SURFACE(((1.,1.),(1.,1.),(1.,
1.),(1.,1.))) REPRESENTATION_ITEM('') SURFACE());
#1955=CARTESIAN_POINT('',(21.,-5.98391850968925,14.9551));
#1956=CARTESIAN_POINT('',(21.,-5.98391850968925,14.4214));
#1957=CARTESIAN_POINT('',(21.,-5.54711850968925,13.9846));
#1958=CARTESIAN_POINT('',(21.,-5.01321850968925,13.9846));
#1959=(BOUNDED_CURVE() B_SPLINE_CURVE(3,(#1955,#1956,#1957,#1958),.UNSPECIFIED.,.F.,
.F.) B_SPLINE_CURVE_WITH_KNOTS((4,4),(0.375,0.5),
.UNSPECIFIED.) CURVE() GEOMETRIC_REPRESENTATION_ITEM() RATIONAL_B_SPLINE_CURVE((1.,1.,1.,1.)) REPRESENTATION_ITEM(''));
#1960=CARTESIAN_POINT('',(21.,-5.01321850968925,13.9846));
#1961=VERTEX_POINT('',#1960);
#1962=EDGE_CURVE('P1_E1357',#1932,#1961,#1959,.T.);
#1963=DIRECTION('',(1.,0.,0.));
#1964=VECTOR('',#1963,1.);
#1965=CARTESIAN_POINT('',(20.9,-5.01321850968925,13.9846));
#1966=LINE('',#1965,#1964);
#1967=EDGE_CURVE('P1_E1480',#1797,#1961,#1966,.T.);
#1968=ORIENTED_EDGE('',*,*,#1962,.T.);
#1969=ORIENTED_EDGE('',*,*,#1967,.F.);
#1970=ORIENTED_EDGE('',*,*,#1798,.F.);
#1971=ORIENTED_EDGE('',*,*,#1939,.T.);
#1972=EDGE_LOOP('',(#1968,#1969,#1970,#1971));
#1973=FACE_BOUND('',#1972,.T.);
#1974=ADVANCED_FACE('P1_F1980',(#1973),#1954,.F.);
#1975=CARTESIAN_POINT('',(20.9,5.05098149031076,13.9846));
#1976=DIRECTION('',(0.,0.,-1.));
#1977=DIRECTION('',(0.,-1.,0.));
#1978=AXIS2_PLACEMENT_3D('',#1975,#1976,#1977);
#1979=PLANE('',#1978);
#1980=DIRECTION('',(0.,1.,0.));
#1981=VECTOR('',#1980,1.);
#1982=CARTESIAN_POINT('',(21.,5.05098149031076,13.9846));
#1983=LINE('',#1982,#1981);
#1984=CARTESIAN_POINT('',(21.,5.05098149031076,13.9846));
#1985=VERTEX_POINT('',#1984);
#1986=EDGE_CURVE('P1_E1366',#1961,#1985,#1983,.T.);
#1987=ORIENTED_EDGE('',*,*,#1986,.T.);
#1988=DIRECTION('',(1.,0.,0.));
#1989=VECTOR('',#1988,1.);
#1990=CARTESIAN_POINT('',(20.9,5.05098149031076,13.9846));
#1991=LINE('',#1990,#1989);
#1992=EDGE_CURVE('P1_E1588',#1744,#1985,#1991,.T.);
#1993=ORIENTED_EDGE('',*,*,#1992,.F.);
#1994=ORIENTED_EDGE('',*,*,#1804,.F.);
#1995=ORIENTED_EDGE('',*,*,#1967,.T.);
#1996=EDGE_LOOP('',(#1987,#1993,#1994,#1995));
#1997=FACE_BOUND('',#1996,.T.);
#1998=ADVANCED_FACE('P1_F1991',(#1997),#1979,.F.);
#1999=CARTESIAN_POINT('',(20.9,5.05098149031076,13.9846));
#2000=CARTESIAN_POINT('',(21.,5.05098149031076,13.9846));
#2001=CARTESIAN_POINT('',(20.9,5.58488149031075,13.9846));
#2002=CARTESIAN_POINT('',(21.,5.58488149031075,13.9846));
#2003=CARTESIAN_POINT('',(20.9,6.02178149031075,14.4214));
#2004=CARTESIAN_POINT('',(21.,6.02178149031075,14.4214));
#2005=CARTESIAN_POINT('',(20.9,6.02178149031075,14.9551));
#2006=CARTESIAN_POINT('',(21.,6.02178149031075,14.9551));
#2007=(BOUNDED_SURFACE() B_SPLINE_SURFACE(3,1,((#1999,#2000),(#2001,#2002),(#2003,#2004),(#2005,
#2006)),.UNSPECIFIED.,.F.,.F.,.F.) B_SPLINE_SURFACE_WITH_KNOTS((4,4),(2,2),(0.125,0.25),(0.,1.),
.UNSPECIFIED.) GEOMETRIC_REPRESENTATION_ITEM() RATIONAL_B_SPLINE_SURFACE(((1.,1.),(1.,1.),(1.,
1.),(1.,1.))) REPRESENTATION_ITEM('') SURFACE());
#2008=CARTESIAN_POINT('',(21.,5.05098149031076,13.9846));
#2009=CARTESIAN_POINT('',(21.,5.58488149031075,13.9846));
#2010=CARTESIAN_POINT('',(21.,6.02178149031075,14.4214));
#2011=CARTESIAN_POINT('',(21.,6.02178149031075,14.9551));
#2012=(BOUNDED_CURVE() B_SPLINE_CURVE(3,(#2008,#2009,#2010,#2011),.UNSPECIFIED.,.F.,
.F.) B_SPLINE_CURVE_WITH_KNOTS((4,4),(0.125,0.25),
.UNSPECIFIED.) CURVE() GEOMETRIC_REPRESENTATION_ITEM() RATIONAL_B_SPLINE_CURVE((1.,1.,1.,1.)) REPRESENTATION_ITEM(''));
#2013=EDGE_CURVE('P1_E1556',#1985,#1819,#2012,.T.);
#2014=ORIENTED_EDGE('',*,*,#2013,.T.);
#2015=ORIENTED_EDGE('',*,*,#1835,.F.);
#2016=ORIENTED_EDGE('',*,*,#1747,.F.);
#2017=ORIENTED_EDGE('',*,*,#1992,.T.);
#2018=EDGE_LOOP('',(#2014,#2015,#2016,#2017));
#2019=FACE_BOUND('',#2018,.T.);
#2020=ADVANCED_FACE('P1_F2011',(#2019),#2007,.F.);
#2021=CARTESIAN_POINT('',(0.,25.3,0.));
#2022=DIRECTION('',(0.,1.,0.));
#2023=DIRECTION('',(1.,0.,0.));
#2024=AXIS2_PLACEMENT_3D('',#2021,#2022,#2023);
#2025=PLANE('',#2024);
#2026=DIRECTION('',(0.,0.,1.));
#2027=VECTOR('',#2026,1.);
#2028=CARTESIAN_POINT('',(-8.25,25.3,0.));
#2029=LINE('',#2028,#2027);
#2030=CARTESIAN_POINT('',(-8.25,25.3,0.));
#2031=VERTEX_POINT('',#2030);
#2032=CARTESIAN_POINT('',(-8.25,25.3,3.));
#2033=VERTEX_POINT('',#2032);
#2034=EDGE_CURVE('P1_E1462',#2031,#2033,#2029,.T.);
#2035=ORIENTED_EDGE('',*,*,#2034,.T.);
#2036=DIRECTION('',(1.,0.,0.));
#2037=VECTOR('',#2036,1.);
#2038=CARTESIAN_POINT('',(0.,25.3,3.));
#2039=LINE('',#2038,#2037);
#2040=CARTESIAN_POINT('',(8.25,25.3,3.));
#2041=VERTEX_POINT('',#2040);
#2042=EDGE_CURVE('P1_E1522',#2033,#2041,#2039,.T.);
#2043=ORIENTED_EDGE('',*,*,#2042,.T.);
#2044=DIRECTION('',(0.,0.,1.));
#2045=VECTOR('',#2044,1.);
#2046=CARTESIAN_POINT('',(8.25,25.3,0.));
#2047=LINE('',#2046,#2045);
#2048=CARTESIAN_POINT('',(8.25,25.3,0.));
#2049=VERTEX_POINT('',#2048);
#2050=EDGE_CURVE('P1_E1523',#2049,#2041,#2047,.T.);
#2051=ORIENTED_EDGE('',*,*,#2050,.F.);
#2052=DIRECTION('',(-1.,0.,0.));
#2053=VECTOR('',#2052,1.);
#2054=CARTESIAN_POINT('',(0.,25.3,0.));
#2055=LINE('',#2054,#2053);
#2056=EDGE_CURVE('P1_E1504',#2049,#2031,#2055,.T.);
#2057=ORIENTED_EDGE('',*,*,#2056,.T.);
#2058=EDGE_LOOP('',(#2035,#2043,#2051,#2057));
#2059=FACE_BOUND('',#2058,.T.);
#2060=ADVANCED_FACE('P1_F2967',(#2059),#2025,.T.);
#2061=CARTESIAN_POINT('',(8.25,25.3,0.));
#2062=DIRECTION('',(1.,0.,0.));
#2063=DIRECTION('',(0.,1.,0.));
#2064=AXIS2_PLACEMENT_3D('',#2061,#2062,#2063);
#2065=PLANE('',#2064);
#2066=DIRECTION('',(0.,0.,1.));
#2067=VECTOR('',#2066,1.);
#2068=CARTESIAN_POINT('',(8.25,21.,0.));
#2069=LINE('',#2068,#2067);
#2070=CARTESIAN_POINT('',(8.25,21.,0.));
#2071=VERTEX_POINT('',#2070);
#2072=CARTESIAN_POINT('',(8.25,21.,3.));
#2073=VERTEX_POINT('',#2072);
#2074=EDGE_CURVE('P1_E1373',#2071,#2073,#2069,.T.);
#2075=ORIENTED_EDGE('',*,*,#2074,.F.);
#2076=DIRECTION('',(0.,-1.,0.));
#2077=VECTOR('',#2076,1.);
#2078=CARTESIAN_POINT('',(8.25,25.3,0.));
#2079=LINE('',#2078,#2077);
#2080=EDGE_CURVE('P1_E1505',#2049,#2071,#2079,.T.);
#2081=ORIENTED_EDGE('',*,*,#2080,.F.);
#2082=ORIENTED_EDGE('',*,*,#2050,.T.);
#2083=DIRECTION('',(0.,-1.,0.));
#2084=VECTOR('',#2083,1.);
#2085=CARTESIAN_POINT('',(8.25,25.3,3.));
#2086=LINE('',#2085,#2084);
#2087=EDGE_CURVE('P1_E1576',#2041,#2073,#2086,.T.);
#2088=ORIENTED_EDGE('',*,*,#2087,.T.);
#2089=EDGE_LOOP('',(#2075,#2081,#2082,#2088));
#2090=FACE_BOUND('',#2089,.T.);
#2091=ADVANCED_FACE('P1_F3004',(#2090),#2065,.T.);
#2092=CARTESIAN_POINT('',(0.,25.3,3.));
#2093=DIRECTION('',(0.,0.,-1.));
#2094=DIRECTION('',(-1.,0.,0.));
#2095=AXIS2_PLACEMENT_3D('',#2092,#2093,#2094);
#2096=PLANE('',#2095);
#2097=DIRECTION('',(1.,0.,0.));
#2098=VECTOR('',#2097,1.);
#2099=CARTESIAN_POINT('',(0.,21.,3.));
#2100=LINE('',#2099,#2098);
#2101=CARTESIAN_POINT('',(-8.25,21.,3.));
#2102=VERTEX_POINT('',#2101);
#2103=EDGE_CURVE('P1_E1380',#2102,#2073,#2100,.T.);
#2104=ORIENTED_EDGE('',*,*,#2103,.T.);
#2105=ORIENTED_EDGE('',*,*,#2087,.F.);
#2106=ORIENTED_EDGE('',*,*,#2042,.F.);
#2107=DIRECTION('',(0.,-1.,0.));
#2108=VECTOR('',#2107,1.);
#2109=CARTESIAN_POINT('',(-8.25,25.3,3.));
#2110=LINE('',#2109,#2108);
#2111=EDGE_CURVE('P1_E1335',#2033,#2102,#2110,.T.);
#2112=ORIENTED_EDGE('',*,*,#2111,.T.);
#2113=EDGE_LOOP('',(#2104,#2105,#2106,#2112));
#2114=FACE_BOUND('',#2113,.T.);
#2115=ADVANCED_FACE('P1_F1276',(#2114),#2096,.F.);
#2116=CARTESIAN_POINT('',(-8.25,25.3,0.));
#2117=DIRECTION('',(1.,0.,0.));
#2118=DIRECTION('',(0.,0.,-1.));
#2119=AXIS2_PLACEMENT_3D('',#2116,#2117,#2118);
#2120=PLANE('',#2119);
#2121=DIRECTION('',(0.,0.,1.));
#2122=VECTOR('',#2121,1.);
#2123=CARTESIAN_POINT('',(-8.25,21.,0.));
#2124=LINE('',#2123,#2122);
#2125=CARTESIAN_POINT('',(-8.25,21.,0.));
#2126=VERTEX_POINT('',#2125);
#2127=EDGE_CURVE('P1_E1771',#2126,#2102,#2124,.T.);
#2128=ORIENTED_EDGE('',*,*,#2127,.T.);
#2129=ORIENTED_EDGE('',*,*,#2111,.F.);
#2130=ORIENTED_EDGE('',*,*,#2034,.F.);
#2131=DIRECTION('',(0.,-1.,0.));
#2132=VECTOR('',#2131,1.);
#2133=CARTESIAN_POINT('',(-8.25,25.3,0.));
#2134=LINE('',#2133,#2132);
#2135=EDGE_CURVE('P1_E1499',#2031,#2126,#2134,.T.);
#2136=ORIENTED_EDGE('',*,*,#2135,.T.);
#2137=EDGE_LOOP('',(#2128,#2129,#2130,#2136));
#2138=FACE_BOUND('',#2137,.T.);
#2139=ADVANCED_FACE('P1_F1274',(#2138),#2120,.F.);
#2140=CARTESIAN_POINT('',(0.,0.,64.));
#2141=DIRECTION('',(0.,0.,-1.));
#2142=DIRECTION('',(-1.,0.,0.));
#2143=AXIS2_PLACEMENT_3D('',#2140,#2141,#2142);
#2144=CONICAL_SURFACE('',#2143,2.20000000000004,0.785398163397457);
#2145=DIRECTION('',(-0.707106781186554,0.,-0.707106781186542));
#2146=VECTOR('',#2145,1.);
#2147=CARTESIAN_POINT('',(-2.20000000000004,0.,64.));
#2148=LINE('',#2147,#2146);
#2149=CARTESIAN_POINT('',(-2.20000000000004,0.,64.));
#2150=VERTEX_POINT('',#2149);
#2151=CARTESIAN_POINT('',(-2.5,0.,63.7));
#2152=VERTEX_POINT('',#2151);
#2153=EDGE_CURVE('P1_E1924',#2150,#2152,#2148,.T.);
#2154=ORIENTED_EDGE('',*,*,#2153,.F.);
#2155=CARTESIAN_POINT('',(0.,0.,64.));
#2156=DIRECTION('',(0.,0.,1.));
#2157=DIRECTION('',(1.,0.,0.));
#2158=AXIS2_PLACEMENT_3D('',#2155,#2156,#2157);
#2159=CIRCLE('',#2158,2.20000000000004);
#2160=CARTESIAN_POINT('',(-0.916515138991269,2.,64.));
#2161=VERTEX_POINT('',#2160);
#2162=EDGE_CURVE('P1_E1322',#2161,#2150,#2159,.T.);
#2163=ORIENTED_EDGE('',*,*,#2162,.F.);
#2164=CARTESIAN_POINT('',(-1.5,2.,63.7));
#2165=CARTESIAN_POINT('',(-1.18963571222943,2.,63.8862185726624));
#2166=CARTESIAN_POINT('',(-0.916515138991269,2.,64.0000000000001));
#2167=B_SPLINE_CURVE_WITH_KNOTS('',2,(#2164,#2165,#2166),.UNSPECIFIED.,.F.,.F.,(3,3),(0.,1.),.UNSPECIFIED.);
#2168=CARTESIAN_POINT('',(-1.5,2.,63.7));
#2169=VERTEX_POINT('',#2168);
#2170=EDGE_CURVE('P1_E1100',#2169,#2161,#2167,.T.);
#2171=ORIENTED_EDGE('',*,*,#2170,.F.);
#2172=CARTESIAN_POINT('',(0.,0.,63.7));
#2173=DIRECTION('',(0.,0.,-1.));
#2174=DIRECTION('',(1.,0.,0.));
#2175=AXIS2_PLACEMENT_3D('',#2172,#2173,#2174);
#2176=CIRCLE('',#2175,2.5);
#2177=EDGE_CURVE('P1_E1313',#2152,#2169,#2176,.T.);
#2178=ORIENTED_EDGE('',*,*,#2177,.F.);
#2179=EDGE_LOOP('',(#2154,#2163,#2171,#2178));
#2180=FACE_BOUND('',#2179,.T.);
#2181=ADVANCED_FACE('P1_F1275',(#2180),#2144,.T.);
#2182=CARTESIAN_POINT('',(0.,0.,64.));
#2183=DIRECTION('',(0.,0.,1.));
#2184=DIRECTION('',(1.,0.,0.));
#2185=AXIS2_PLACEMENT_3D('',#2182,#2183,#2184);
#2186=PLANE('',#2185);
#2187=DIRECTION('',(1.,0.,0.));
#2188=VECTOR('',#2187,1.);
#2189=CARTESIAN_POINT('',(0.,2.,64.));
#2190=LINE('',#2189,#2188);
#2191=CARTESIAN_POINT('',(0.916515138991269,2.,64.));
#2192=VERTEX_POINT('',#2191);
#2193=EDGE_CURVE('P1_E1327',#2161,#2192,#2190,.T.);
#2194=ORIENTED_EDGE('',*,*,#2193,.F.);
#2195=ORIENTED_EDGE('',*,*,#2162,.T.);
#2196=CARTESIAN_POINT('',(0.,0.,64.));
#2197=DIRECTION('',(0.,0.,1.));
#2198=DIRECTION('',(1.,0.,0.));
#2199=AXIS2_PLACEMENT_3D('',#2196,#2197,#2198);
#2200=CIRCLE('',#2199,2.20000000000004);
#2201=CARTESIAN_POINT('',(2.20000000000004,0.,64.));
#2202=VERTEX_POINT('',#2201);
#2203=EDGE_CURVE('P1_E1914',#2150,#2202,#2200,.T.);
#2204=ORIENTED_EDGE('',*,*,#2203,.T.);
#2205=CARTESIAN_POINT('',(0.,0.,64.));
#2206=DIRECTION('',(0.,0.,1.));
#2207=DIRECTION('',(1.,0.,0.));
#2208=AXIS2_PLACEMENT_3D('',#2205,#2206,#2207);
#2209=CIRCLE('',#2208,2.20000000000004);
#2210=EDGE_CURVE('P1_E1146',#2202,#2192,#2209,.T.);
#2211=ORIENTED_EDGE('',*,*,#2210,.T.);
#2212=EDGE_LOOP('',(#2194,#2195,#2204,#2211));
#2213=FACE_BOUND('',#2212,.T.);
#2214=ADVANCED_FACE('P1_F1299',(#2213),#2186,.T.);
#2215=CARTESIAN_POINT('',(0.,0.,92.7268120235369));
#2216=DIRECTION('',(0.,0.,-1.));
#2217=DIRECTION('',(-1.,0.,0.));
#2218=AXIS2_PLACEMENT_3D('',#2215,#2216,#2217);
#2219=CYLINDRICAL_SURFACE('',#2218,2.5);
#2220=DIRECTION('',(0.,0.,-1.));
#2221=VECTOR('',#2220,1.);
#2222=CARTESIAN_POINT('',(-2.5,0.,92.7268120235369));
#2223=LINE('',#2222,#2221);
#2224=CARTESIAN_POINT('',(-2.5,0.,42.));
#2225=VERTEX_POINT('',#2224);
#2226=EDGE_CURVE('P1_E1920',#2152,#2225,#2223,.T.);
#2227=ORIENTED_EDGE('',*,*,#2226,.F.);
#2228=ORIENTED_EDGE('',*,*,#2177,.T.);
#2229=DIRECTION('',(0.,0.,-1.));
#2230=VECTOR('',#2229,1.);
#2231=CARTESIAN_POINT('',(-1.5,2.,92.7268120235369));
#2232=LINE('',#2231,#2230);
#2233=CARTESIAN_POINT('',(-1.5,2.,42.));
#2234=VERTEX_POINT('',#2233);
#2235=EDGE_CURVE('P1_E1321',#2169,#2234,#2232,.T.);
#2236=ORIENTED_EDGE('',*,*,#2235,.T.);
#2237=CARTESIAN_POINT('',(0.,0.,42.));
#2238=DIRECTION('',(0.,0.,1.));
#2239=DIRECTION('',(1.,0.,0.));
#2240=AXIS2_PLACEMENT_3D('',#2237,#2238,#2239);
#2241=CIRCLE('',#2240,2.5);
#2242=EDGE_CURVE('P1_E1340',#2234,#2225,#2241,.T.);
#2243=ORIENTED_EDGE('',*,*,#2242,.T.);
#2244=EDGE_LOOP('',(#2227,#2228,#2236,#2243));
#2245=FACE_BOUND('',#2244,.T.);
#2246=ADVANCED_FACE('P1_F1114',(#2245),#2219,.T.);
#2247=CARTESIAN_POINT('',(0.,2.,92.7268120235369));
#2248=DIRECTION('',(0.,1.,0.));
#2249=DIRECTION('',(1.,0.,0.));
#2250=AXIS2_PLACEMENT_3D('',#2247,#2248,#2249);
#2251=PLANE('',#2250);
#2252=ORIENTED_EDGE('',*,*,#2193,.T.);
#2253=CARTESIAN_POINT('',(0.916515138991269,2.,64.0000000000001));
#2254=CARTESIAN_POINT('',(1.18963571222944,2.,63.8862185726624));
#2255=CARTESIAN_POINT('',(1.5,2.,63.7));
#2256=B_SPLINE_CURVE_WITH_KNOTS('',2,(#2253,#2254,#2255),.UNSPECIFIED.,.F.,.F.,(3,3),(0.,1.),.UNSPECIFIED.);
#2257=CARTESIAN_POINT('',(1.5,2.,63.7));
#2258=VERTEX_POINT('',#2257);
#2259=EDGE_CURVE('P1_E1137',#2192,#2258,#2256,.T.);
#2260=ORIENTED_EDGE('',*,*,#2259,.T.);
#2261=DIRECTION('',(0.,0.,-1.));
#2262=VECTOR('',#2261,1.);
#2263=CARTESIAN_POINT('',(1.5,2.,92.7268120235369));
#2264=LINE('',#2263,#2262);
#2265=CARTESIAN_POINT('',(1.5,2.,42.));
#2266=VERTEX_POINT('',#2265);
#2267=EDGE_CURVE('P1_E1921',#2258,#2266,#2264,.T.);
#2268=ORIENTED_EDGE('',*,*,#2267,.T.);
#2269=DIRECTION('',(-1.,0.,0.));
#2270=VECTOR('',#2269,1.);
#2271=CARTESIAN_POINT('',(-1.5,2.,42.));
#2272=LINE('',#2271,#2270);
#2273=EDGE_CURVE('P1_E1342',#2266,#2234,#2272,.T.);
#2274=ORIENTED_EDGE('',*,*,#2273,.T.);
#2275=ORIENTED_EDGE('',*,*,#2235,.F.);
#2276=ORIENTED_EDGE('',*,*,#2170,.T.);
#2277=EDGE_LOOP('',(#2252,#2260,#2268,#2274,#2275,#2276));
#2278=FACE_BOUND('',#2277,.T.);
#2279=ADVANCED_FACE('P1_F1101',(#2278),#2251,.T.);
#2280=CARTESIAN_POINT('',(0.,0.,42.));
#2281=DIRECTION('',(0.,0.,-1.));
#2282=DIRECTION('',(-1.,0.,0.));
#2283=AXIS2_PLACEMENT_3D('',#2280,#2281,#2282);
#2284=CYLINDRICAL_SURFACE('',#2283,11.);
#2285=DIRECTION('',(0.,0.,-1.));
#2286=VECTOR('',#2285,1.);
#2287=CARTESIAN_POINT('',(11.,0.,42.));
#2288=LINE('',#2287,#2286);
#2289=CARTESIAN_POINT('',(11.,0.,42.));
#2290=VERTEX_POINT('',#2289);
#2291=CARTESIAN_POINT('',(11.,0.,40.));
#2292=VERTEX_POINT('',#2291);
#2293=EDGE_CURVE('P1_E1947',#2290,#2292,#2288,.T.);
#2294=ORIENTED_EDGE('',*,*,#2293,.F.);
#2295=CARTESIAN_POINT('',(0.,0.,42.));
#2296=DIRECTION('',(0.,0.,1.));
#2297=DIRECTION('',(1.,0.,0.));
#2298=AXIS2_PLACEMENT_3D('',#2295,#2296,#2297);
#2299=CIRCLE('',#2298,11.);
#2300=CARTESIAN_POINT('',(-11.,0.,42.));
#2301=VERTEX_POINT('',#2300);
#2302=EDGE_CURVE('P1_E1355',#2301,#2290,#2299,.T.);
#2303=ORIENTED_EDGE('',*,*,#2302,.F.);
#2304=DIRECTION('',(0.,0.,-1.));
#2305=VECTOR('',#2304,1.);
#2306=CARTESIAN_POINT('',(-11.,0.,42.));
#2307=LINE('',#2306,#2305);
#2308=CARTESIAN_POINT('',(-11.,0.,40.));
#2309=VERTEX_POINT('',#2308);
#2310=EDGE_CURVE('P1_E1899',#2301,#2309,#2307,.T.);
#2311=ORIENTED_EDGE('',*,*,#2310,.T.);
#2312=CARTESIAN_POINT('',(0.,0.,40.));
#2313=DIRECTION('',(0.,0.,1.));
#2314=DIRECTION('',(1.,0.,0.));
#2315=AXIS2_PLACEMENT_3D('',#2312,#2313,#2314);
#2316=CIRCLE('',#2315,11.);
#2317=EDGE_CURVE('P1_E1464',#2309,#2292,#2316,.T.);
#2318=ORIENTED_EDGE('',*,*,#2317,.T.);
#2319=EDGE_LOOP('',(#2294,#2303,#2311,#2318));
#2320=FACE_BOUND('',#2319,.T.);
#2321=ADVANCED_FACE('P1_F1112',(#2320),#2284,.T.);
#2322=CARTESIAN_POINT('',(0.,0.,42.));
#2323=DIRECTION('',(0.,0.,1.));
#2324=DIRECTION('',(1.,0.,0.));
#2325=AXIS2_PLACEMENT_3D('',#2322,#2323,#2324);
#2326=PLANE('',#2325);
#2327=ORIENTED_EDGE('',*,*,#2273,.F.);
#2328=CARTESIAN_POINT('',(0.,0.,42.));
#2329=DIRECTION('',(0.,0.,1.));
#2330=DIRECTION('',(1.,0.,0.));
#2331=AXIS2_PLACEMENT_3D('',#2328,#2329,#2330);
#2332=CIRCLE('',#2331,2.5);
#2333=CARTESIAN_POINT('',(2.5,0.,42.));
#2334=VERTEX_POINT('',#2333);
#2335=EDGE_CURVE('P1_E1937',#2334,#2266,#2332,.T.);
#2336=ORIENTED_EDGE('',*,*,#2335,.F.);
#2337=CARTESIAN_POINT('',(0.,0.,42.));
#2338=DIRECTION('',(0.,0.,1.));
#2339=DIRECTION('',(1.,0.,0.));
#2340=AXIS2_PLACEMENT_3D('',#2337,#2338,#2339);
#2341=CIRCLE('',#2340,2.5);
#2342=EDGE_CURVE('P1_E1919',#2225,#2334,#2341,.T.);
#2343=ORIENTED_EDGE('',*,*,#2342,.F.);
#2344=ORIENTED_EDGE('',*,*,#2242,.F.);
#2345=EDGE_LOOP('',(#2327,#2336,#2343,#2344));
#2346=FACE_BOUND('',#2345,.T.);
#2347=ORIENTED_EDGE('',*,*,#2302,.T.);
#2348=CARTESIAN_POINT('',(0.,0.,42.));
#2349=DIRECTION('',(0.,0.,1.));
#2350=DIRECTION('',(1.,0.,0.));
#2351=AXIS2_PLACEMENT_3D('',#2348,#2349,#2350);
#2352=CIRCLE('',#2351,11.);
#2353=EDGE_CURVE('P1_E1936',#2290,#2301,#2352,.T.);
#2354=ORIENTED_EDGE('',*,*,#2353,.T.);
#2355=EDGE_LOOP('',(#2347,#2354));
#2356=FACE_BOUND('',#2355,.T.);
#2357=ADVANCED_FACE('P1_F2940',(#2346,#2356),#2326,.T.);
#2358=CARTESIAN_POINT('',(-15.5,-15.5,40.));
#2359=DIRECTION('',(0.,0.,-1.));
#2360=DIRECTION('',(-1.,0.,0.));
#2361=AXIS2_PLACEMENT_3D('',#2358,#2359,#2360);
#2362=CYLINDRICAL_SURFACE('',#2361,1.5);
#2363=DIRECTION('',(0.,0.,-1.));
#2364=VECTOR('',#2363,1.);
#2365=CARTESIAN_POINT('',(-14.,-15.5,40.));
#2366=LINE('',#2365,#2364);
#2367=CARTESIAN_POINT('',(-14.,-15.5,40.));
#2368=VERTEX_POINT('',#2367);
#2369=CARTESIAN_POINT('',(-14.,-15.5,0.));
#2370=VERTEX_POINT('',#2369);
#2371=EDGE_CURVE('P1_E1871',#2368,#2370,#2366,.T.);
#2372=ORIENTED_EDGE('',*,*,#2371,.F.);
#2373=CARTESIAN_POINT('',(-15.5,-15.5,40.));
#2374=DIRECTION('',(0.,0.,1.));
#2375=DIRECTION('',(1.,0.,0.));
#2376=AXIS2_PLACEMENT_3D('',#2373,#2374,#2375);
#2377=CIRCLE('',#2376,1.5);
#2378=CARTESIAN_POINT('',(-17.,-15.5,40.));
#2379=VERTEX_POINT('',#2378);
#2380=EDGE_CURVE('P1_E1456',#2368,#2379,#2377,.T.);
#2381=ORIENTED_EDGE('',*,*,#2380,.T.);
#2382=DIRECTION('',(0.,0.,-1.));
#2383=VECTOR('',#2382,1.);
#2384=CARTESIAN_POINT('',(-17.,-15.5,40.));
#2385=LINE('',#2384,#2383);
#2386=CARTESIAN_POINT('',(-17.,-15.5,0.));
#2387=VERTEX_POINT('',#2386);
#2388=EDGE_CURVE('P1_E1753',#2379,#2387,#2385,.T.);
#2389=ORIENTED_EDGE('',*,*,#2388,.T.);
#2390=CARTESIAN_POINT('',(-15.5,-15.5,0.));
#2391=DIRECTION('',(0.,0.,1.));
#2392=DIRECTION('',(1.,0.,0.));
#2393=AXIS2_PLACEMENT_3D('',#2390,#2391,#2392);
#2394=CIRCLE('',#2393,1.5);
#2395=EDGE_CURVE('P1_E1512',#2370,#2387,#2394,.T.);
#2396=ORIENTED_EDGE('',*,*,#2395,.F.);
#2397=EDGE_LOOP('',(#2372,#2381,#2389,#2396));
#2398=FACE_BOUND('',#2397,.T.);
#2399=ADVANCED_FACE('P1_F1198',(#2398),#2362,.F.);
#2400=CARTESIAN_POINT('',(15.5,-15.5,40.));
#2401=DIRECTION('',(0.,0.,-1.));
#2402=DIRECTION('',(-1.,0.,0.));
#2403=AXIS2_PLACEMENT_3D('',#2400,#2401,#2402);
#2404=CYLINDRICAL_SURFACE('',#2403,1.5);
#2405=DIRECTION('',(0.,0.,-1.));
#2406=VECTOR('',#2405,1.);
#2407=CARTESIAN_POINT('',(17.,-15.5,40.));
#2408=LINE('',#2407,#2406);
#2409=CARTESIAN_POINT('',(17.,-15.5,40.));
#2410=VERTEX_POINT('',#2409);
#2411=CARTESIAN_POINT('',(17.,-15.5,0.));
#2412=VERTEX_POINT('',#2411);
#2413=EDGE_CURVE('P1_E1761',#2410,#2412,#2408,.T.);
#2414=ORIENTED_EDGE('',*,*,#2413,.F.);
#2415=CARTESIAN_POINT('',(15.5,-15.5,40.));
#2416=DIRECTION('',(0.,0.,1.));
#2417=DIRECTION('',(1.,0.,0.));
#2418=AXIS2_PLACEMENT_3D('',#2415,#2416,#2417);
#2419=CIRCLE('',#2418,1.5);
#2420=CARTESIAN_POINT('',(14.,-15.5,40.));
#2421=VERTEX_POINT('',#2420);
#2422=EDGE_CURVE('P1_E1449',#2410,#2421,#2419,.T.);
#2423=ORIENTED_EDGE('',*,*,#2422,.T.);
#2424=DIRECTION('',(0.,0.,-1.));
#2425=VECTOR('',#2424,1.);
#2426=CARTESIAN_POINT('',(14.,-15.5,40.));
#2427=LINE('',#2426,#2425);
#2428=CARTESIAN_POINT('',(14.,-15.5,0.));
#2429=VERTEX_POINT('',#2428);
#2430=EDGE_CURVE('P1_E1782',#2421,#2429,#2427,.T.);
#2431=ORIENTED_EDGE('',*,*,#2430,.T.);
#2432=CARTESIAN_POINT('',(15.5,-15.5,0.));
#2433=DIRECTION('',(0.,0.,1.));
#2434=DIRECTION('',(1.,0.,0.));
#2435=AXIS2_PLACEMENT_3D('',#2432,#2433,#2434);
#2436=CIRCLE('',#2435,1.5);
#2437=EDGE_CURVE('P1_E1502',#2412,#2429,#2436,.T.);
#2438=ORIENTED_EDGE('',*,*,#2437,.F.);
#2439=EDGE_LOOP('',(#2414,#2423,#2431,#2438));
#2440=FACE_BOUND('',#2439,.T.);
#2441=ADVANCED_FACE('P1_F1194',(#2440),#2404,.F.);
#2442=CARTESIAN_POINT('',(15.5,15.5,40.));
#2443=DIRECTION('',(0.,0.,-1.));
#2444=DIRECTION('',(-1.,0.,0.));
#2445=AXIS2_PLACEMENT_3D('',#2442,#2443,#2444);
#2446=CYLINDRICAL_SURFACE('',#2445,1.5);
#2447=DIRECTION('',(0.,0.,-1.));
#2448=VECTOR('',#2447,1.);
#2449=CARTESIAN_POINT('',(17.,15.5,40.));
#2450=LINE('',#2449,#2448);
#2451=CARTESIAN_POINT('',(17.,15.5,40.));
#2452=VERTEX_POINT('',#2451);
#2453=CARTESIAN_POINT('',(17.,15.5,0.));
#2454=VERTEX_POINT('',#2453);
#2455=EDGE_CURVE('P1_E1793',#2452,#2454,#2450,.T.);
#2456=ORIENTED_EDGE('',*,*,#2455,.F.);
#2457=CARTESIAN_POINT('',(15.5,15.5,40.));
#2458=DIRECTION('',(0.,0.,1.));
#2459=DIRECTION('',(1.,0.,0.));
#2460=AXIS2_PLACEMENT_3D('',#2457,#2458,#2459);
#2461=CIRCLE('',#2460,1.5);
#2462=CARTESIAN_POINT('',(14.,15.5,40.));
#2463=VERTEX_POINT('',#2462);
#2464=EDGE_CURVE('P1_E1445',#2452,#2463,#2461,.T.);
#2465=ORIENTED_EDGE('',*,*,#2464,.T.);
#2466=DIRECTION('',(0.,0.,-1.));
#2467=VECTOR('',#2466,1.);
#2468=CARTESIAN_POINT('',(14.,15.5,40.));
#2469=LINE('',#2468,#2467);
#2470=CARTESIAN_POINT('',(14.,15.5,0.));
#2471=VERTEX_POINT('',#2470);
#2472=EDGE_CURVE('P1_E1808',#2463,#2471,#2469,.T.);
#2473=ORIENTED_EDGE('',*,*,#2472,.T.);
#2474=CARTESIAN_POINT('',(15.5,15.5,0.));
#2475=DIRECTION('',(0.,0.,1.));
#2476=DIRECTION('',(1.,0.,0.));
#2477=AXIS2_PLACEMENT_3D('',#2474,#2475,#2476);
#2478=CIRCLE('',#2477,1.5);
#2479=EDGE_CURVE('P1_E1517',#2454,#2471,#2478,.T.);
#2480=ORIENTED_EDGE('',*,*,#2479,.F.);
#2481=EDGE_LOOP('',(#2456,#2465,#2473,#2480));
#2482=FACE_BOUND('',#2481,.T.);
#2483=ADVANCED_FACE('P1_F1200',(#2482),#2446,.F.);
#2484=CARTESIAN_POINT('',(-15.5,15.5,40.));
#2485=DIRECTION('',(0.,0.,-1.));
#2486=DIRECTION('',(-1.,0.,0.));
#2487=AXIS2_PLACEMENT_3D('',#2484,#2485,#2486);
#2488=CYLINDRICAL_SURFACE('',#2487,1.5);
#2489=DIRECTION('',(0.,0.,-1.));
#2490=VECTOR('',#2489,1.);
#2491=CARTESIAN_POINT('',(-14.,15.5,40.));
#2492=LINE('',#2491,#2490);
#2493=CARTESIAN_POINT('',(-14.,15.5,40.));
#2494=VERTEX_POINT('',#2493);
#2495=CARTESIAN_POINT('',(-14.,15.5,0.));
#2496=VERTEX_POINT('',#2495);
#2497=EDGE_CURVE('P1_E1812',#2494,#2496,#2492,.T.);
#2498=ORIENTED_EDGE('',*,*,#2497,.F.);
#2499=CARTESIAN_POINT('',(-15.5,15.5,40.));
#2500=DIRECTION('',(0.,0.,1.));
#2501=DIRECTION('',(1.,0.,0.));
#2502=AXIS2_PLACEMENT_3D('',#2499,#2500,#2501);
#2503=CIRCLE('',#2502,1.5);
#2504=CARTESIAN_POINT('',(-17.,15.5,40.));
#2505=VERTEX_POINT('',#2504);
#2506=EDGE_CURVE('P1_E1431',#2494,#2505,#2503,.T.);
#2507=ORIENTED_EDGE('',*,*,#2506,.T.);
#2508=DIRECTION('',(0.,0.,-1.));
#2509=VECTOR('',#2508,1.);
#2510=CARTESIAN_POINT('',(-17.,15.5,40.));
#2511=LINE('',#2510,#2509);
#2512=CARTESIAN_POINT('',(-17.,15.5,0.));
#2513=VERTEX_POINT('',#2512);
#2514=EDGE_CURVE('P1_E1780',#2505,#2513,#2511,.T.);
#2515=ORIENTED_EDGE('',*,*,#2514,.T.);
#2516=CARTESIAN_POINT('',(-15.5,15.5,0.));
#2517=DIRECTION('',(0.,0.,1.));
#2518=DIRECTION('',(1.,0.,0.));
#2519=AXIS2_PLACEMENT_3D('',#2516,#2517,#2518);
#2520=CIRCLE('',#2519,1.5);
#2521=EDGE_CURVE('P1_E1516',#2496,#2513,#2520,.T.);
#2522=ORIENTED_EDGE('',*,*,#2521,.F.);
#2523=EDGE_LOOP('',(#2498,#2507,#2515,#2522));
#2524=FACE_BOUND('',#2523,.T.);
#2525=ADVANCED_FACE('P1_F1282',(#2524),#2488,.F.);
#2526=CARTESIAN_POINT('',(16.8,21.,40.));
#2527=DIRECTION('',(-0.707106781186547,-0.707106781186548,0.));
#2528=DIRECTION('',(-0.707106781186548,0.707106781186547,0.));
#2529=AXIS2_PLACEMENT_3D('',#2526,#2527,#2528);
#2530=PLANE('',#2529);
#2531=DIRECTION('',(-0.707106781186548,0.707106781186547,0.));
#2532=VECTOR('',#2531,1.);
#2533=CARTESIAN_POINT('',(16.8,21.,0.));
#2534=LINE('',#2533,#2532);
#2535=CARTESIAN_POINT('',(21.,16.8,0.));
#2536=VERTEX_POINT('',#2535);
#2537=CARTESIAN_POINT('',(16.8,21.,0.));
#2538=VERTEX_POINT('',#2537);
#2539=EDGE_CURVE('P1_E1468',#2536,#2538,#2534,.T.);
#2540=ORIENTED_EDGE('',*,*,#2539,.T.);
#2541=DIRECTION('',(0.,0.,-1.));
#2542=VECTOR('',#2541,1.);
#2543=CARTESIAN_POINT('',(16.8,21.,40.));
#2544=LINE('',#2543,#2542);
#2545=CARTESIAN_POINT('',(16.8,21.,40.));
#2546=VERTEX_POINT('',#2545);
#2547=EDGE_CURVE('P1_E1356',#2546,#2538,#2544,.T.);
#2548=ORIENTED_EDGE('',*,*,#2547,.F.);
#2549=DIRECTION('',(-0.707106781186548,0.707106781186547,0.));
#2550=VECTOR('',#2549,1.);
#2551=CARTESIAN_POINT('',(16.8,21.,40.));
#2552=LINE('',#2551,#2550);
#2553=CARTESIAN_POINT('',(21.,16.8,40.));
#2554=VERTEX_POINT('',#2553);
#2555=EDGE_CURVE('P1_E1427',#2554,#2546,#2552,.T.);
#2556=ORIENTED_EDGE('',*,*,#2555,.F.);
#2557=DIRECTION('',(0.,0.,-1.));
#2558=VECTOR('',#2557,1.);
#2559=CARTESIAN_POINT('',(21.,16.8,40.));
#2560=LINE('',#2559,#2558);
#2561=EDGE_CURVE('P1_E1433',#2554,#2536,#2560,.T.);
#2562=ORIENTED_EDGE('',*,*,#2561,.T.);
#2563=EDGE_LOOP('',(#2540,#2548,#2556,#2562));
#2564=FACE_BOUND('',#2563,.T.);
#2565=ADVANCED_FACE('P1_F1119',(#2564),#2530,.F.);
#2566=CARTESIAN_POINT('',(21.,16.8,40.));
#2567=DIRECTION('',(-1.,0.,0.));
#2568=DIRECTION('',(0.,1.,0.));
#2569=AXIS2_PLACEMENT_3D('',#2566,#2567,#2568);
#2570=PLANE('',#2569);
#2571=ORIENTED_EDGE('',*,*,#1822,.F.);
#2572=ORIENTED_EDGE('',*,*,#2013,.F.);
#2573=ORIENTED_EDGE('',*,*,#1986,.F.);
#2574=ORIENTED_EDGE('',*,*,#1962,.F.);
#2575=ORIENTED_EDGE('',*,*,#1933,.F.);
#2576=ORIENTED_EDGE('',*,*,#1909,.F.);
#2577=ORIENTED_EDGE('',*,*,#1880,.F.);
#2578=ORIENTED_EDGE('',*,*,#1856,.F.);
#2579=EDGE_LOOP('',(#2571,#2572,#2573,#2574,#2575,#2576,#2577,#2578));
#2580=FACE_BOUND('',#2579,.T.);
#2581=DIRECTION('',(0.,1.,0.));
#2582=VECTOR('',#2581,1.);
#2583=CARTESIAN_POINT('',(21.,16.8,0.));
#2584=LINE('',#2583,#2582);
#2585=CARTESIAN_POINT('',(21.,-16.8,0.));
#2586=VERTEX_POINT('',#2585);
#2587=EDGE_CURVE('P1_E1404',#2586,#2536,#2584,.T.);
#2588=ORIENTED_EDGE('',*,*,#2587,.T.);
#2589=ORIENTED_EDGE('',*,*,#2561,.F.);
#2590=DIRECTION('',(0.,1.,0.));
#2591=VECTOR('',#2590,1.);
#2592=CARTESIAN_POINT('',(21.,16.8,40.));
#2593=LINE('',#2592,#2591);
#2594=CARTESIAN_POINT('',(21.,-16.8,40.));
#2595=VERTEX_POINT('',#2594);
#2596=EDGE_CURVE('P1_E1416',#2595,#2554,#2593,.T.);
#2597=ORIENTED_EDGE('',*,*,#2596,.F.);
#2598=DIRECTION('',(0.,0.,-1.));
#2599=VECTOR('',#2598,1.);
#2600=CARTESIAN_POINT('',(21.,-16.8,40.));
#2601=LINE('',#2600,#2599);
#2602=EDGE_CURVE('P1_E1438',#2595,#2586,#2601,.T.);
#2603=ORIENTED_EDGE('',*,*,#2602,.T.);
#2604=EDGE_LOOP('',(#2588,#2589,#2597,#2603));
#2605=FACE_BOUND('',#2604,.T.);
#2606=ADVANCED_FACE('P1_F1271',(#2580,#2605),#2570,.F.);
#2607=CARTESIAN_POINT('',(16.8,-21.,40.));
#2608=DIRECTION('',(-0.707106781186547,0.707106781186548,0.));
#2609=DIRECTION('',(0.,0.,1.));
#2610=AXIS2_PLACEMENT_3D('',#2607,#2608,#2609);
#2611=PLANE('',#2610);
#2612=DIRECTION('',(0.707106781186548,0.707106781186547,0.));
#2613=VECTOR('',#2612,1.);
#2614=CARTESIAN_POINT('',(16.8,-21.,0.));
#2615=LINE('',#2614,#2613);
#2616=CARTESIAN_POINT('',(16.8,-21.,0.));
#2617=VERTEX_POINT('',#2616);
#2618=EDGE_CURVE('P1_E1397',#2617,#2586,#2615,.T.);
#2619=ORIENTED_EDGE('',*,*,#2618,.T.);
#2620=ORIENTED_EDGE('',*,*,#2602,.F.);
#2621=DIRECTION('',(0.707106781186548,0.707106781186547,0.));
#2622=VECTOR('',#2621,1.);
#2623=CARTESIAN_POINT('',(16.8,-21.,40.));
#2624=LINE('',#2623,#2622);
#2625=CARTESIAN_POINT('',(16.8,-21.,40.));
#2626=VERTEX_POINT('',#2625);
#2627=EDGE_CURVE('P1_E1407',#2626,#2595,#2624,.T.);
#2628=ORIENTED_EDGE('',*,*,#2627,.F.);
#2629=DIRECTION('',(0.,0.,-1.));
#2630=VECTOR('',#2629,1.);
#2631=CARTESIAN_POINT('',(16.8,-21.,40.));
#2632=LINE('',#2631,#2630);
#2633=EDGE_CURVE('P1_E1539',#2626,#2617,#2632,.T.);
#2634=ORIENTED_EDGE('',*,*,#2633,.T.);
#2635=EDGE_LOOP('',(#2619,#2620,#2628,#2634));
#2636=FACE_BOUND('',#2635,.T.);
#2637=ADVANCED_FACE('P1_F1270',(#2636),#2611,.F.);
#2638=CARTESIAN_POINT('',(-16.8,-21.,40.));
#2639=DIRECTION('',(0.,1.,0.));
#2640=DIRECTION('',(1.,0.,0.));
#2641=AXIS2_PLACEMENT_3D('',#2638,#2639,#2640);
#2642=PLANE('',#2641);
#2643=DIRECTION('',(1.,0.,0.));
#2644=VECTOR('',#2643,1.);
#2645=CARTESIAN_POINT('',(-16.8,-21.,0.));
#2646=LINE('',#2645,#2644);
#2647=CARTESIAN_POINT('',(-16.8,-21.,0.));
#2648=VERTEX_POINT('',#2647);
#2649=EDGE_CURVE('P1_E1405',#2648,#2617,#2646,.T.);
#2650=ORIENTED_EDGE('',*,*,#2649,.T.);
#2651=ORIENTED_EDGE('',*,*,#2633,.F.);
#2652=DIRECTION('',(1.,0.,0.));
#2653=VECTOR('',#2652,1.);
#2654=CARTESIAN_POINT('',(-16.8,-21.,40.));
#2655=LINE('',#2654,#2653);
#2656=CARTESIAN_POINT('',(-16.8,-21.,40.));
#2657=VERTEX_POINT('',#2656);
#2658=EDGE_CURVE('P1_E1400',#2657,#2626,#2655,.T.);
#2659=ORIENTED_EDGE('',*,*,#2658,.F.);
#2660=DIRECTION('',(0.,0.,-1.));
#2661=VECTOR('',#2660,1.);
#2662=CARTESIAN_POINT('',(-16.8,-21.,40.));
#2663=LINE('',#2662,#2661);
#2664=EDGE_CURVE('P1_E1491',#2657,#2648,#2663,.T.);
#2665=ORIENTED_EDGE('',*,*,#2664,.T.);
#2666=EDGE_LOOP('',(#2650,#2651,#2659,#2665));
#2667=FACE_BOUND('',#2666,.T.);
#2668=ADVANCED_FACE('P1_F1236',(#2667),#2642,.F.);
#2669=CARTESIAN_POINT('',(-21.,-16.8,40.));
#2670=DIRECTION('',(0.707106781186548,0.707106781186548,0.));
#2671=DIRECTION('',(0.,0.,-1.));
#2672=AXIS2_PLACEMENT_3D('',#2669,#2670,#2671);
#2673=PLANE('',#2672);
#2674=DIRECTION('',(0.707106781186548,-0.707106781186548,0.));
#2675=VECTOR('',#2674,1.);
#2676=CARTESIAN_POINT('',(-21.,-16.8,0.));
#2677=LINE('',#2676,#2675);
#2678=CARTESIAN_POINT('',(-21.,-16.8,0.));
#2679=VERTEX_POINT('',#2678);
#2680=EDGE_CURVE('P1_E1475',#2679,#2648,#2677,.T.);
#2681=ORIENTED_EDGE('',*,*,#2680,.T.);
#2682=ORIENTED_EDGE('',*,*,#2664,.F.);
#2683=DIRECTION('',(0.707106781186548,-0.707106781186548,0.));
#2684=VECTOR('',#2683,1.);
#2685=CARTESIAN_POINT('',(-21.,-16.8,40.));
#2686=LINE('',#2685,#2684);
#2687=CARTESIAN_POINT('',(-21.,-16.8,40.));
#2688=VERTEX_POINT('',#2687);
#2689=EDGE_CURVE('P1_E1390',#2688,#2657,#2686,.T.);
#2690=ORIENTED_EDGE('',*,*,#2689,.F.);
#2691=DIRECTION('',(0.,0.,-1.));
#2692=VECTOR('',#2691,1.);
#2693=CARTESIAN_POINT('',(-21.,-16.8,40.));
#2694=LINE('',#2693,#2692);
#2695=EDGE_CURVE('P1_E1489',#2688,#2679,#2694,.T.);
#2696=ORIENTED_EDGE('',*,*,#2695,.T.);
#2697=EDGE_LOOP('',(#2681,#2682,#2690,#2696));
#2698=FACE_BOUND('',#2697,.T.);
#2699=ADVANCED_FACE('P1_F1237',(#2698),#2673,.F.);
#2700=CARTESIAN_POINT('',(-21.,16.8,40.));
#2701=DIRECTION('',(1.,0.,0.));
#2702=DIRECTION('',(0.,1.,0.));
#2703=AXIS2_PLACEMENT_3D('',#2700,#2701,#2702);
#2704=PLANE('',#2703);
#2705=DIRECTION('',(0.,-1.,0.));
#2706=VECTOR('',#2705,1.);
#2707=CARTESIAN_POINT('',(-21.,16.8,0.));
#2708=LINE('',#2707,#2706);
#2709=CARTESIAN_POINT('',(-21.,16.8,0.));
#2710=VERTEX_POINT('',#2709);
#2711=EDGE_CURVE('P1_E1476',#2710,#2679,#2708,.T.);
#2712=ORIENTED_EDGE('',*,*,#2711,.T.);
#2713=ORIENTED_EDGE('',*,*,#2695,.F.);
#2714=DIRECTION('',(0.,-1.,0.));
#2715=VECTOR('',#2714,1.);
#2716=CARTESIAN_POINT('',(-21.,16.8,40.));
#2717=LINE('',#2716,#2715);
#2718=CARTESIAN_POINT('',(-21.,16.8,40.));
#2719=VERTEX_POINT('',#2718);
#2720=EDGE_CURVE('P1_E1384',#2719,#2688,#2717,.T.);
#2721=ORIENTED_EDGE('',*,*,#2720,.F.);
#2722=DIRECTION('',(0.,0.,-1.));
#2723=VECTOR('',#2722,1.);
#2724=CARTESIAN_POINT('',(-21.,16.8,40.));
#2725=LINE('',#2724,#2723);
#2726=EDGE_CURVE('P1_E1492',#2719,#2710,#2725,.T.);
#2727=ORIENTED_EDGE('',*,*,#2726,.T.);
#2728=EDGE_LOOP('',(#2712,#2713,#2721,#2727));
#2729=FACE_BOUND('',#2728,.T.);
#2730=ADVANCED_FACE('P1_F1184',(#2729),#2704,.F.);
#2731=CARTESIAN_POINT('',(-21.,16.8,40.));
#2732=DIRECTION('',(0.707106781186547,-0.707106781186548,0.));
#2733=DIRECTION('',(0.,0.,-1.));
#2734=AXIS2_PLACEMENT_3D('',#2731,#2732,#2733);
#2735=PLANE('',#2734);
#2736=DIRECTION('',(-0.707106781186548,-0.707106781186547,0.));
#2737=VECTOR('',#2736,1.);
#2738=CARTESIAN_POINT('',(-21.,16.8,0.));
#2739=LINE('',#2738,#2737);
#2740=CARTESIAN_POINT('',(-16.8,21.,0.));
#2741=VERTEX_POINT('',#2740);
#2742=EDGE_CURVE('P1_E1496',#2741,#2710,#2739,.T.);
#2743=ORIENTED_EDGE('',*,*,#2742,.T.);
#2744=ORIENTED_EDGE('',*,*,#2726,.F.);
#2745=DIRECTION('',(-0.707106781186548,-0.707106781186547,0.));
#2746=VECTOR('',#2745,1.);
#2747=CARTESIAN_POINT('',(-21.,16.8,40.));
#2748=LINE('',#2747,#2746);
#2749=CARTESIAN_POINT('',(-16.8,21.,40.));
#2750=VERTEX_POINT('',#2749);
#2751=EDGE_CURVE('P1_E1376',#2750,#2719,#2748,.T.);
#2752=ORIENTED_EDGE('',*,*,#2751,.F.);
#2753=DIRECTION('',(0.,0.,-1.));
#2754=VECTOR('',#2753,1.);
#2755=CARTESIAN_POINT('',(-16.8,21.,40.));
#2756=LINE('',#2755,#2754);
#2757=EDGE_CURVE('P1_E1846',#2750,#2741,#2756,.T.);
#2758=ORIENTED_EDGE('',*,*,#2757,.T.);
#2759=EDGE_LOOP('',(#2743,#2744,#2752,#2758));
#2760=FACE_BOUND('',#2759,.T.);
#2761=ADVANCED_FACE('P1_F1162',(#2760),#2735,.F.);
#2762=CARTESIAN_POINT('',(0.,0.,0.));
#2763=DIRECTION('',(0.,0.,-1.));
#2764=DIRECTION('',(0.,-1.,0.));
#2765=AXIS2_PLACEMENT_3D('',#2762,#2763,#2764);
#2766=PLANE('',#2765);
#2767=CARTESIAN_POINT('',(-15.5,-15.5,0.));
#2768=DIRECTION('',(0.,0.,1.));
#2769=DIRECTION('',(1.,0.,0.));
#2770=AXIS2_PLACEMENT_3D('',#2767,#2768,#2769);
#2771=CIRCLE('',#2770,1.5);
#2772=EDGE_CURVE('P1_E1757',#2387,#2370,#2771,.T.);
#2773=ORIENTED_EDGE('',*,*,#2772,.T.);
#2774=ORIENTED_EDGE('',*,*,#2395,.T.);
#2775=EDGE_LOOP('',(#2773,#2774));
#2776=FACE_BOUND('',#2775,.T.);
#2777=CARTESIAN_POINT('',(15.5,15.5,0.));
#2778=DIRECTION('',(0.,0.,1.));
#2779=DIRECTION('',(1.,0.,0.));
#2780=AXIS2_PLACEMENT_3D('',#2777,#2778,#2779);
#2781=CIRCLE('',#2780,1.5);
#2782=EDGE_CURVE('P1_E1801',#2471,#2454,#2781,.T.);
#2783=ORIENTED_EDGE('',*,*,#2782,.T.);
#2784=ORIENTED_EDGE('',*,*,#2479,.T.);
#2785=EDGE_LOOP('',(#2783,#2784));
#2786=FACE_BOUND('',#2785,.T.);
#2787=CARTESIAN_POINT('',(-15.5,15.5,0.));
#2788=DIRECTION('',(0.,0.,1.));
#2789=DIRECTION('',(1.,0.,0.));
#2790=AXIS2_PLACEMENT_3D('',#2787,#2788,#2789);
#2791=CIRCLE('',#2790,1.5);
#2792=EDGE_CURVE('P1_E1820',#2513,#2496,#2791,.T.);
#2793=ORIENTED_EDGE('',*,*,#2792,.T.);
#2794=ORIENTED_EDGE('',*,*,#2521,.T.);
#2795=EDGE_LOOP('',(#2793,#2794));
#2796=FACE_BOUND('',#2795,.T.);
#2797=CARTESIAN_POINT('',(15.5,-15.5,0.));
#2798=DIRECTION('',(0.,0.,1.));
#2799=DIRECTION('',(1.,0.,0.));
#2800=AXIS2_PLACEMENT_3D('',#2797,#2798,#2799);
#2801=CIRCLE('',#2800,1.5);
#2802=EDGE_CURVE('P1_E1770',#2429,#2412,#2801,.T.);
#2803=ORIENTED_EDGE('',*,*,#2802,.T.);
#2804=ORIENTED_EDGE('',*,*,#2437,.T.);
#2805=EDGE_LOOP('',(#2803,#2804));
#2806=FACE_BOUND('',#2805,.T.);
#2807=DIRECTION('',(-1.,0.,0.));
#2808=VECTOR('',#2807,1.);
#2809=CARTESIAN_POINT('',(-16.8,21.,0.));
#2810=LINE('',#2809,#2808);
#2811=EDGE_CURVE('P1_E1370',#2538,#2071,#2810,.T.);
#2812=ORIENTED_EDGE('',*,*,#2811,.F.);
#2813=ORIENTED_EDGE('',*,*,#2539,.F.);
#2814=ORIENTED_EDGE('',*,*,#2587,.F.);
#2815=ORIENTED_EDGE('',*,*,#2618,.F.);
#2816=ORIENTED_EDGE('',*,*,#2649,.F.);
#2817=ORIENTED_EDGE('',*,*,#2680,.F.);
#2818=ORIENTED_EDGE('',*,*,#2711,.F.);
#2819=ORIENTED_EDGE('',*,*,#2742,.F.);
#2820=DIRECTION('',(-1.,0.,0.));
#2821=VECTOR('',#2820,1.);
#2822=CARTESIAN_POINT('',(-16.8,21.,0.));
#2823=LINE('',#2822,#2821);
#2824=EDGE_CURVE('P1_E1774',#2126,#2741,#2823,.T.);
#2825=ORIENTED_EDGE('',*,*,#2824,.F.);
#2826=ORIENTED_EDGE('',*,*,#2135,.F.);
#2827=ORIENTED_EDGE('',*,*,#2056,.F.);
#2828=ORIENTED_EDGE('',*,*,#2080,.T.);
#2829=EDGE_LOOP('',(#2812,#2813,#2814,#2815,#2816,#2817,#2818,#2819,#2825,#2826,#2827,#2828));
#2830=FACE_BOUND('',#2829,.T.);
#2831=ADVANCED_FACE('P1_F1159',(#2776,#2786,#2796,#2806,#2830),#2766,.T.);
#2832=CARTESIAN_POINT('',(0.,0.,40.));
#2833=DIRECTION('',(0.,0.,-1.));
#2834=DIRECTION('',(0.,-1.,0.));
#2835=AXIS2_PLACEMENT_3D('',#2832,#2833,#2834);
#2836=PLANE('',#2835);
#2837=ORIENTED_EDGE('',*,*,#2317,.F.);
#2838=CARTESIAN_POINT('',(0.,0.,40.));
#2839=DIRECTION('',(0.,0.,1.));
#2840=DIRECTION('',(1.,0.,0.));
#2841=AXIS2_PLACEMENT_3D('',#2838,#2839,#2840);
#2842=CIRCLE('',#2841,11.);
#2843=EDGE_CURVE('P1_E1948',#2292,#2309,#2842,.T.);
#2844=ORIENTED_EDGE('',*,*,#2843,.F.);
#2845=EDGE_LOOP('',(#2837,#2844));
#2846=FACE_BOUND('',#2845,.T.);
#2847=CARTESIAN_POINT('',(-15.5,-15.5,40.));
#2848=DIRECTION('',(0.,0.,1.));
#2849=DIRECTION('',(1.,0.,0.));
#2850=AXIS2_PLACEMENT_3D('',#2847,#2848,#2849);
#2851=CIRCLE('',#2850,1.5);
#2852=EDGE_CURVE('P1_E1869',#2379,#2368,#2851,.T.);
#2853=ORIENTED_EDGE('',*,*,#2852,.F.);
#2854=ORIENTED_EDGE('',*,*,#2380,.F.);
#2855=EDGE_LOOP('',(#2853,#2854));
#2856=FACE_BOUND('',#2855,.T.);
#2857=CARTESIAN_POINT('',(15.5,-15.5,40.));
#2858=DIRECTION('',(0.,0.,1.));
#2859=DIRECTION('',(1.,0.,0.));
#2860=AXIS2_PLACEMENT_3D('',#2857,#2858,#2859);
#2861=CIRCLE('',#2860,1.5);
#2862=EDGE_CURVE('P1_E1760',#2421,#2410,#2861,.T.);
#2863=ORIENTED_EDGE('',*,*,#2862,.F.);
#2864=ORIENTED_EDGE('',*,*,#2422,.F.);
#2865=EDGE_LOOP('',(#2863,#2864));
#2866=FACE_BOUND('',#2865,.T.);
#2867=CARTESIAN_POINT('',(15.5,15.5,40.));
#2868=DIRECTION('',(0.,0.,1.));
#2869=DIRECTION('',(1.,0.,0.));
#2870=AXIS2_PLACEMENT_3D('',#2867,#2868,#2869);
#2871=CIRCLE('',#2870,1.5);
#2872=EDGE_CURVE('P1_E1790',#2463,#2452,#2871,.T.);
#2873=ORIENTED_EDGE('',*,*,#2872,.F.);
#2874=ORIENTED_EDGE('',*,*,#2464,.F.);
#2875=EDGE_LOOP('',(#2873,#2874));
#2876=FACE_BOUND('',#2875,.T.);
#2877=CARTESIAN_POINT('',(-15.5,15.5,40.));
#2878=DIRECTION('',(0.,0.,1.));
#2879=DIRECTION('',(1.,0.,0.));
#2880=AXIS2_PLACEMENT_3D('',#2877,#2878,#2879);
#2881=CIRCLE('',#2880,1.5);
#2882=EDGE_CURVE('P1_E1815',#2505,#2494,#2881,.T.);
#2883=ORIENTED_EDGE('',*,*,#2882,.F.);
#2884=ORIENTED_EDGE('',*,*,#2506,.F.);
#2885=EDGE_LOOP('',(#2883,#2884));
#2886=FACE_BOUND('',#2885,.T.);
#2887=DIRECTION('',(-1.,0.,0.));
#2888=VECTOR('',#2887,1.);
#2889=CARTESIAN_POINT('',(-16.8,21.,40.));
#2890=LINE('',#2889,#2888);
#2891=EDGE_CURVE('P1_E1854',#2546,#2750,#2890,.T.);
#2892=ORIENTED_EDGE('',*,*,#2891,.T.);
#2893=ORIENTED_EDGE('',*,*,#2751,.T.);
#2894=ORIENTED_EDGE('',*,*,#2720,.T.);
#2895=ORIENTED_EDGE('',*,*,#2689,.T.);
#2896=ORIENTED_EDGE('',*,*,#2658,.T.);
#2897=ORIENTED_EDGE('',*,*,#2627,.T.);
#2898=ORIENTED_EDGE('',*,*,#2596,.T.);
#2899=ORIENTED_EDGE('',*,*,#2555,.T.);
#2900=EDGE_LOOP('',(#2892,#2893,#2894,#2895,#2896,#2897,#2898,#2899));
#2901=FACE_BOUND('',#2900,.T.);
#2902=ADVANCED_FACE('P1_F1161',(#2846,#2856,#2866,#2876,#2886,#2901),#2836,.F.);
#2903=CARTESIAN_POINT('',(-16.8,21.,40.));
#2904=DIRECTION('',(0.,-1.,0.));
#2905=DIRECTION('',(0.,0.,-1.));
#2906=AXIS2_PLACEMENT_3D('',#2903,#2904,#2905);
#2907=PLANE('',#2906);
#2908=ORIENTED_EDGE('',*,*,#2127,.F.);
#2909=ORIENTED_EDGE('',*,*,#2824,.T.);
#2910=ORIENTED_EDGE('',*,*,#2757,.F.);
#2911=ORIENTED_EDGE('',*,*,#2891,.F.);
#2912=ORIENTED_EDGE('',*,*,#2547,.T.);
#2913=ORIENTED_EDGE('',*,*,#2811,.T.);
#2914=ORIENTED_EDGE('',*,*,#2074,.T.);
#2915=ORIENTED_EDGE('',*,*,#2103,.F.);
#2916=EDGE_LOOP('',(#2908,#2909,#2910,#2911,#2912,#2913,#2914,#2915));
#2917=FACE_BOUND('',#2916,.T.);
#2918=ADVANCED_FACE('P1_F1241',(#2917),#2907,.F.);
#2919=CARTESIAN_POINT('',(-15.5,15.5,40.));
#2920=DIRECTION('',(0.,0.,-1.));
#2921=DIRECTION('',(-1.,0.,0.));
#2922=AXIS2_PLACEMENT_3D('',#2919,#2920,#2921);
#2923=CYLINDRICAL_SURFACE('',#2922,1.5);
#2924=ORIENTED_EDGE('',*,*,#2882,.T.);
#2925=ORIENTED_EDGE('',*,*,#2497,.T.);
#2926=ORIENTED_EDGE('',*,*,#2792,.F.);
#2927=ORIENTED_EDGE('',*,*,#2514,.F.);
#2928=EDGE_LOOP('',(#2924,#2925,#2926,#2927));
#2929=FACE_BOUND('',#2928,.T.);
#2930=ADVANCED_FACE('P1_F1202',(#2929),#2923,.F.);
#2931=CARTESIAN_POINT('',(15.5,15.5,40.));
#2932=DIRECTION('',(0.,0.,-1.));
#2933=DIRECTION('',(-1.,0.,0.));
#2934=AXIS2_PLACEMENT_3D('',#2931,#2932,#2933);
#2935=CYLINDRICAL_SURFACE('',#2934,1.5);
#2936=ORIENTED_EDGE('',*,*,#2872,.T.);
#2937=ORIENTED_EDGE('',*,*,#2455,.T.);
#2938=ORIENTED_EDGE('',*,*,#2782,.F.);
#2939=ORIENTED_EDGE('',*,*,#2472,.F.);
#2940=EDGE_LOOP('',(#2936,#2937,#2938,#2939));
#2941=FACE_BOUND('',#2940,.T.);
#2942=ADVANCED_FACE('P1_F1199',(#2941),#2935,.F.);
#2943=CARTESIAN_POINT('',(15.5,-15.5,40.));
#2944=DIRECTION('',(0.,0.,-1.));
#2945=DIRECTION('',(-1.,0.,0.));
#2946=AXIS2_PLACEMENT_3D('',#2943,#2944,#2945);
#2947=CYLINDRICAL_SURFACE('',#2946,1.5);
#2948=ORIENTED_EDGE('',*,*,#2862,.T.);
#2949=ORIENTED_EDGE('',*,*,#2413,.T.);
#2950=ORIENTED_EDGE('',*,*,#2802,.F.);
#2951=ORIENTED_EDGE('',*,*,#2430,.F.);
#2952=EDGE_LOOP('',(#2948,#2949,#2950,#2951));
#2953=FACE_BOUND('',#2952,.T.);
#2954=ADVANCED_FACE('P1_F1203',(#2953),#2947,.F.);
#2955=CARTESIAN_POINT('',(-15.5,-15.5,40.));
#2956=DIRECTION('',(0.,0.,-1.));
#2957=DIRECTION('',(-1.,0.,0.));
#2958=AXIS2_PLACEMENT_3D('',#2955,#2956,#2957);
#2959=CYLINDRICAL_SURFACE('',#2958,1.5);
#2960=ORIENTED_EDGE('',*,*,#2852,.T.);
#2961=ORIENTED_EDGE('',*,*,#2371,.T.);
#2962=ORIENTED_EDGE('',*,*,#2772,.F.);
#2963=ORIENTED_EDGE('',*,*,#2388,.F.);
#2964=EDGE_LOOP('',(#2960,#2961,#2962,#2963));
#2965=FACE_BOUND('',#2964,.T.);
#2966=ADVANCED_FACE('P1_F1187',(#2965),#2959,.F.);
#2967=CARTESIAN_POINT('',(0.,0.,42.));
#2968=DIRECTION('',(0.,0.,-1.));
#2969=DIRECTION('',(-1.,0.,0.));
#2970=AXIS2_PLACEMENT_3D('',#2967,#2968,#2969);
#2971=CYLINDRICAL_SURFACE('',#2970,11.);
#2972=ORIENTED_EDGE('',*,*,#2353,.F.);
#2973=ORIENTED_EDGE('',*,*,#2293,.T.);
#2974=ORIENTED_EDGE('',*,*,#2843,.T.);
#2975=ORIENTED_EDGE('',*,*,#2310,.F.);
#2976=EDGE_LOOP('',(#2972,#2973,#2974,#2975));
#2977=FACE_BOUND('',#2976,.T.);
#2978=ADVANCED_FACE('P1_F1178',(#2977),#2971,.T.);
#2979=CARTESIAN_POINT('',(0.,0.,92.7268120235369));
#2980=DIRECTION('',(0.,0.,-1.));
#2981=DIRECTION('',(-1.,0.,0.));
#2982=AXIS2_PLACEMENT_3D('',#2979,#2980,#2981);
#2983=CYLINDRICAL_SURFACE('',#2982,2.5);
#2984=DIRECTION('',(0.,0.,-1.));
#2985=VECTOR('',#2984,1.);
#2986=CARTESIAN_POINT('',(2.5,0.,92.7268120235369));
#2987=LINE('',#2986,#2985);
#2988=CARTESIAN_POINT('',(2.5,0.,63.7));
#2989=VERTEX_POINT('',#2988);
#2990=EDGE_CURVE('P1_E1934',#2989,#2334,#2987,.T.);
#2991=ORIENTED_EDGE('',*,*,#2990,.F.);
#2992=CARTESIAN_POINT('',(0.,0.,63.7));
#2993=DIRECTION('',(0.,0.,-1.));
#2994=DIRECTION('',(1.,0.,0.));
#2995=AXIS2_PLACEMENT_3D('',#2992,#2993,#2994);
#2996=CIRCLE('',#2995,2.5);
#2997=EDGE_CURVE('P1_E1926',#2989,#2152,#2996,.T.);
#2998=ORIENTED_EDGE('',*,*,#2997,.T.);
#2999=ORIENTED_EDGE('',*,*,#2226,.T.);
#3000=ORIENTED_EDGE('',*,*,#2342,.T.);
#3001=EDGE_LOOP('',(#2991,#2998,#2999,#3000));
#3002=FACE_BOUND('',#3001,.T.);
#3003=ADVANCED_FACE('P1_F1174',(#3002),#2983,.T.);
#3004=CARTESIAN_POINT('',(0.,0.,92.7268120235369));
#3005=DIRECTION('',(0.,0.,-1.));
#3006=DIRECTION('',(-1.,0.,0.));
#3007=AXIS2_PLACEMENT_3D('',#3004,#3005,#3006);
#3008=CYLINDRICAL_SURFACE('',#3007,2.5);
#3009=CARTESIAN_POINT('',(0.,0.,63.7));
#3010=DIRECTION('',(0.,0.,-1.));
#3011=DIRECTION('',(1.,0.,0.));
#3012=AXIS2_PLACEMENT_3D('',#3009,#3010,#3011);
#3013=CIRCLE('',#3012,2.5);
#3014=EDGE_CURVE('P1_E2022',#2258,#2989,#3013,.T.);
#3015=ORIENTED_EDGE('',*,*,#3014,.T.);
#3016=ORIENTED_EDGE('',*,*,#2990,.T.);
#3017=ORIENTED_EDGE('',*,*,#2335,.T.);
#3018=ORIENTED_EDGE('',*,*,#2267,.F.);
#3019=EDGE_LOOP('',(#3015,#3016,#3017,#3018));
#3020=FACE_BOUND('',#3019,.T.);
#3021=ADVANCED_FACE('P1_F1175',(#3020),#3008,.T.);
#3022=CARTESIAN_POINT('',(0.,0.,64.));
#3023=DIRECTION('',(0.,0.,-1.));
#3024=DIRECTION('',(-1.,0.,0.));
#3025=AXIS2_PLACEMENT_3D('',#3022,#3023,#3024);
#3026=CONICAL_SURFACE('',#3025,2.20000000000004,0.785398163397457);
#3027=DIRECTION('',(0.707106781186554,0.,-0.707106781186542));
#3028=VECTOR('',#3027,1.);
#3029=CARTESIAN_POINT('',(2.20000000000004,0.,64.));
#3030=LINE('',#3029,#3028);
#3031=EDGE_CURVE('P1_E4555',#2202,#2989,#3030,.T.);
#3032=ORIENTED_EDGE('',*,*,#3031,.F.);
#3033=ORIENTED_EDGE('',*,*,#2203,.F.);
#3034=ORIENTED_EDGE('',*,*,#2153,.T.);
#3035=ORIENTED_EDGE('',*,*,#2997,.F.);
#3036=EDGE_LOOP('',(#3032,#3033,#3034,#3035));
#3037=FACE_BOUND('',#3036,.T.);
#3038=ADVANCED_FACE('P1_F1160',(#3037),#3026,.T.);
#3039=CARTESIAN_POINT('',(0.,0.,64.));
#3040=DIRECTION('',(0.,0.,-1.));
#3041=DIRECTION('',(-1.,0.,0.));
#3042=AXIS2_PLACEMENT_3D('',#3039,#3040,#3041);
#3043=CONICAL_SURFACE('',#3042,2.20000000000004,0.785398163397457);
#3044=ORIENTED_EDGE('',*,*,#2210,.F.);
#3045=ORIENTED_EDGE('',*,*,#3031,.T.);
#3046=ORIENTED_EDGE('',*,*,#3014,.F.);
#3047=ORIENTED_EDGE('',*,*,#2259,.F.);
#3048=EDGE_LOOP('',(#3044,#3045,#3046,#3047));
#3049=FACE_BOUND('',#3048,.T.);
#3050=ADVANCED_FACE('P1_F1148',(#3049),#3043,.T.);
#3051=CLOSED_SHELL('',(#248,#356,#492,#564,#595,#619,#643,#667,#691,#715,#739,#763,#780,#811,
#835,#859,#883,#907,#931,#955,#972,#1008,#1037,#1066,#1090,#1114,#1143,#1167,#1196,#1220,#1249,
#1273,#1302,#1326,#1350,#1372,#1408,#1432,#1456,#1480,#1509,#1538,#1562,#1586,#1610,#1634,#1658,
#1680,#1808,#1839,#1868,#1892,#1921,#1945,#1974,#1998,#2020,#2060,#2091,#2115,#2139,#2181,#2214,
#2246,#2279,#2321,#2357,#2399,#2441,#2483,#2525,#2565,#2606,#2637,#2668,#2699,#2730,#2761,#2831,
#2902,#2918,#2930,#2942,#2954,#2966,#2978,#3003,#3021,#3038,#3050));
#3052=MANIFOLD_SOLID_BREP('P1_B1',#3051);
#3053=ADVANCED_BREP_SHAPE_REPRESENTATION('',(#18,#168,#3052),#14);
#3054=SHAPE_DEFINITION_REPRESENTATION(#9,#3053);
ENDSEC;
END-ISO-10303-21;
